VERSION 5.8 ;
BUSBITCHARS "[]" ;
DIVIDERCHAR "/" ;
UNITS
    DATABASE MICRONS 1000 ;
END UNITS

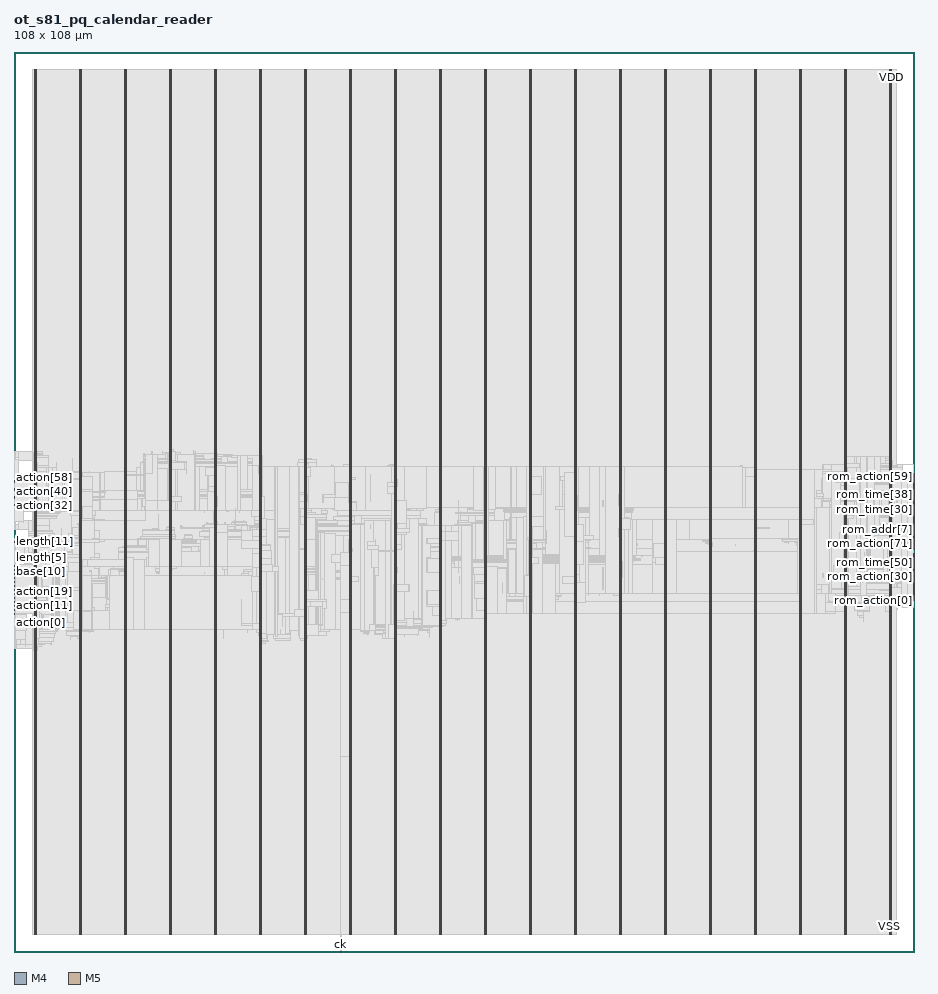
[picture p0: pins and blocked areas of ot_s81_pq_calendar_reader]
MACRO ot_s81_pq_calendar_reader
  FOREIGN ot_s81_pq_calendar_reader 0 0 ;
  CLASS BLOCK ;
  SIZE 108 BY 108 ;
  PIN action[0]
    DIRECTION OUTPUT ;
    USE SIGNAL ;
    PORT
      LAYER M4 ;
        RECT  0 40.464 0.084 40.488 ;
    END
  END action[0]
  PIN action[10]
    DIRECTION OUTPUT ;
    USE SIGNAL ;
    PORT
      LAYER M4 ;
        RECT  0 41.424 0.084 41.448 ;
    END
  END action[10]
  PIN action[11]
    DIRECTION OUTPUT ;
    USE SIGNAL ;
    PORT
      LAYER M4 ;
        RECT  0 41.52 0.084 41.544 ;
    END
  END action[11]
  PIN action[12]
    DIRECTION OUTPUT ;
    USE SIGNAL ;
    PORT
      LAYER M4 ;
        RECT  0 41.616 0.084 41.64 ;
    END
  END action[12]
  PIN action[13]
    DIRECTION OUTPUT ;
    USE SIGNAL ;
    PORT
      LAYER M4 ;
        RECT  0 41.712 0.084 41.736 ;
    END
  END action[13]
  PIN action[14]
    DIRECTION OUTPUT ;
    USE SIGNAL ;
    PORT
      LAYER M4 ;
        RECT  0 41.808 0.084 41.832 ;
    END
  END action[14]
  PIN action[15]
    DIRECTION OUTPUT ;
    USE SIGNAL ;
    PORT
      LAYER M4 ;
        RECT  0 41.904 0.084 41.928 ;
    END
  END action[15]
  PIN action[16]
    DIRECTION OUTPUT ;
    USE SIGNAL ;
    PORT
      LAYER M4 ;
        RECT  0 42 0.084 42.024 ;
    END
  END action[16]
  PIN action[17]
    DIRECTION OUTPUT ;
    USE SIGNAL ;
    PORT
      LAYER M4 ;
        RECT  0 42.096 0.084 42.12 ;
    END
  END action[17]
  PIN action[18]
    DIRECTION OUTPUT ;
    USE SIGNAL ;
    PORT
      LAYER M4 ;
        RECT  0 42.192 0.084 42.216 ;
    END
  END action[18]
  PIN action[19]
    DIRECTION OUTPUT ;
    USE SIGNAL ;
    PORT
      LAYER M4 ;
        RECT  0 42.288 0.084 42.312 ;
    END
  END action[19]
  PIN action[1]
    DIRECTION OUTPUT ;
    USE SIGNAL ;
    PORT
      LAYER M4 ;
        RECT  0 40.56 0.084 40.584 ;
    END
  END action[1]
  PIN action[20]
    DIRECTION OUTPUT ;
    USE SIGNAL ;
    PORT
      LAYER M4 ;
        RECT  0 42.384 0.084 42.408 ;
    END
  END action[20]
  PIN action[21]
    DIRECTION OUTPUT ;
    USE SIGNAL ;
    PORT
      LAYER M4 ;
        RECT  0 42.48 0.084 42.504 ;
    END
  END action[21]
  PIN action[22]
    DIRECTION OUTPUT ;
    USE SIGNAL ;
    PORT
      LAYER M4 ;
        RECT  0 42.576 0.084 42.6 ;
    END
  END action[22]
  PIN action[23]
    DIRECTION OUTPUT ;
    USE SIGNAL ;
    PORT
      LAYER M4 ;
        RECT  0 42.672 0.084 42.696 ;
    END
  END action[23]
  PIN action[24]
    DIRECTION OUTPUT ;
    USE SIGNAL ;
    PORT
      LAYER M4 ;
        RECT  0 42.768 0.084 42.792 ;
    END
  END action[24]
  PIN action[25]
    DIRECTION OUTPUT ;
    USE SIGNAL ;
    PORT
      LAYER M4 ;
        RECT  0 42.864 0.084 42.888 ;
    END
  END action[25]
  PIN action[26]
    DIRECTION OUTPUT ;
    USE SIGNAL ;
    PORT
      LAYER M4 ;
        RECT  0 42.96 0.084 42.984 ;
    END
  END action[26]
  PIN action[27]
    DIRECTION OUTPUT ;
    USE SIGNAL ;
    PORT
      LAYER M4 ;
        RECT  0 43.056 0.084 43.08 ;
    END
  END action[27]
  PIN action[28]
    DIRECTION OUTPUT ;
    USE SIGNAL ;
    PORT
      LAYER M4 ;
        RECT  0 43.152 0.084 43.176 ;
    END
  END action[28]
  PIN action[29]
    DIRECTION OUTPUT ;
    USE SIGNAL ;
    PORT
      LAYER M4 ;
        RECT  0 43.248 0.084 43.272 ;
    END
  END action[29]
  PIN action[2]
    DIRECTION OUTPUT ;
    USE SIGNAL ;
    PORT
      LAYER M4 ;
        RECT  0 40.656 0.084 40.68 ;
    END
  END action[2]
  PIN action[30]
    DIRECTION OUTPUT ;
    USE SIGNAL ;
    PORT
      LAYER M4 ;
        RECT  0 43.344 0.084 43.368 ;
    END
  END action[30]
  PIN action[31]
    DIRECTION OUTPUT ;
    USE SIGNAL ;
    PORT
      LAYER M4 ;
        RECT  0 43.44 0.084 43.464 ;
    END
  END action[31]
  PIN action[32]
    DIRECTION OUTPUT ;
    USE SIGNAL ;
    PORT
      LAYER M4 ;
        RECT  0 53.52 0.084 53.544 ;
    END
  END action[32]
  PIN action[33]
    DIRECTION OUTPUT ;
    USE SIGNAL ;
    PORT
      LAYER M4 ;
        RECT  0 53.616 0.084 53.64 ;
    END
  END action[33]
  PIN action[34]
    DIRECTION OUTPUT ;
    USE SIGNAL ;
    PORT
      LAYER M4 ;
        RECT  0 53.712 0.084 53.736 ;
    END
  END action[34]
  PIN action[35]
    DIRECTION OUTPUT ;
    USE SIGNAL ;
    PORT
      LAYER M4 ;
        RECT  0 53.808 0.084 53.832 ;
    END
  END action[35]
  PIN action[36]
    DIRECTION OUTPUT ;
    USE SIGNAL ;
    PORT
      LAYER M4 ;
        RECT  0 53.904 0.084 53.928 ;
    END
  END action[36]
  PIN action[37]
    DIRECTION OUTPUT ;
    USE SIGNAL ;
    PORT
      LAYER M4 ;
        RECT  0 54 0.084 54.024 ;
    END
  END action[37]
  PIN action[38]
    DIRECTION OUTPUT ;
    USE SIGNAL ;
    PORT
      LAYER M4 ;
        RECT  0 54.096 0.084 54.12 ;
    END
  END action[38]
  PIN action[39]
    DIRECTION OUTPUT ;
    USE SIGNAL ;
    PORT
      LAYER M4 ;
        RECT  0 54.192 0.084 54.216 ;
    END
  END action[39]
  PIN action[3]
    DIRECTION OUTPUT ;
    USE SIGNAL ;
    PORT
      LAYER M4 ;
        RECT  0 40.752 0.084 40.776 ;
    END
  END action[3]
  PIN action[40]
    DIRECTION OUTPUT ;
    USE SIGNAL ;
    PORT
      LAYER M4 ;
        RECT  0 54.288 0.084 54.312 ;
    END
  END action[40]
  PIN action[41]
    DIRECTION OUTPUT ;
    USE SIGNAL ;
    PORT
      LAYER M4 ;
        RECT  0 54.384 0.084 54.408 ;
    END
  END action[41]
  PIN action[42]
    DIRECTION OUTPUT ;
    USE SIGNAL ;
    PORT
      LAYER M4 ;
        RECT  0 54.48 0.084 54.504 ;
    END
  END action[42]
  PIN action[43]
    DIRECTION OUTPUT ;
    USE SIGNAL ;
    PORT
      LAYER M4 ;
        RECT  0 54.576 0.084 54.6 ;
    END
  END action[43]
  PIN action[44]
    DIRECTION OUTPUT ;
    USE SIGNAL ;
    PORT
      LAYER M4 ;
        RECT  0 54.672 0.084 54.696 ;
    END
  END action[44]
  PIN action[45]
    DIRECTION OUTPUT ;
    USE SIGNAL ;
    PORT
      LAYER M4 ;
        RECT  0 54.768 0.084 54.792 ;
    END
  END action[45]
  PIN action[46]
    DIRECTION OUTPUT ;
    USE SIGNAL ;
    PORT
      LAYER M4 ;
        RECT  0 54.864 0.084 54.888 ;
    END
  END action[46]
  PIN action[47]
    DIRECTION OUTPUT ;
    USE SIGNAL ;
    PORT
      LAYER M4 ;
        RECT  0 54.96 0.084 54.984 ;
    END
  END action[47]
  PIN action[48]
    DIRECTION OUTPUT ;
    USE SIGNAL ;
    PORT
      LAYER M4 ;
        RECT  0 55.056 0.084 55.08 ;
    END
  END action[48]
  PIN action[49]
    DIRECTION OUTPUT ;
    USE SIGNAL ;
    PORT
      LAYER M4 ;
        RECT  0 55.152 0.084 55.176 ;
    END
  END action[49]
  PIN action[4]
    DIRECTION OUTPUT ;
    USE SIGNAL ;
    PORT
      LAYER M4 ;
        RECT  0 40.848 0.084 40.872 ;
    END
  END action[4]
  PIN action[50]
    DIRECTION OUTPUT ;
    USE SIGNAL ;
    PORT
      LAYER M4 ;
        RECT  0 55.248 0.084 55.272 ;
    END
  END action[50]
  PIN action[51]
    DIRECTION OUTPUT ;
    USE SIGNAL ;
    PORT
      LAYER M4 ;
        RECT  0 55.344 0.084 55.368 ;
    END
  END action[51]
  PIN action[52]
    DIRECTION OUTPUT ;
    USE SIGNAL ;
    PORT
      LAYER M4 ;
        RECT  0 55.44 0.084 55.464 ;
    END
  END action[52]
  PIN action[53]
    DIRECTION OUTPUT ;
    USE SIGNAL ;
    PORT
      LAYER M4 ;
        RECT  0 55.536 0.084 55.56 ;
    END
  END action[53]
  PIN action[54]
    DIRECTION OUTPUT ;
    USE SIGNAL ;
    PORT
      LAYER M4 ;
        RECT  0 55.632 0.084 55.656 ;
    END
  END action[54]
  PIN action[55]
    DIRECTION OUTPUT ;
    USE SIGNAL ;
    PORT
      LAYER M4 ;
        RECT  0 55.728 0.084 55.752 ;
    END
  END action[55]
  PIN action[56]
    DIRECTION OUTPUT ;
    USE SIGNAL ;
    PORT
      LAYER M4 ;
        RECT  0 55.824 0.084 55.848 ;
    END
  END action[56]
  PIN action[57]
    DIRECTION OUTPUT ;
    USE SIGNAL ;
    PORT
      LAYER M4 ;
        RECT  0 55.92 0.084 55.944 ;
    END
  END action[57]
  PIN action[58]
    DIRECTION OUTPUT ;
    USE SIGNAL ;
    PORT
      LAYER M4 ;
        RECT  0 56.016 0.084 56.04 ;
    END
  END action[58]
  PIN action[59]
    DIRECTION OUTPUT ;
    USE SIGNAL ;
    PORT
      LAYER M4 ;
        RECT  0 56.112 0.084 56.136 ;
    END
  END action[59]
  PIN action[5]
    DIRECTION OUTPUT ;
    USE SIGNAL ;
    PORT
      LAYER M4 ;
        RECT  0 40.944 0.084 40.968 ;
    END
  END action[5]
  PIN action[60]
    DIRECTION OUTPUT ;
    USE SIGNAL ;
    PORT
      LAYER M4 ;
        RECT  0 56.208 0.084 56.232 ;
    END
  END action[60]
  PIN action[61]
    DIRECTION OUTPUT ;
    USE SIGNAL ;
    PORT
      LAYER M4 ;
        RECT  0 56.304 0.084 56.328 ;
    END
  END action[61]
  PIN action[62]
    DIRECTION OUTPUT ;
    USE SIGNAL ;
    PORT
      LAYER M4 ;
        RECT  0 56.4 0.084 56.424 ;
    END
  END action[62]
  PIN action[63]
    DIRECTION OUTPUT ;
    USE SIGNAL ;
    PORT
      LAYER M4 ;
        RECT  0 56.496 0.084 56.52 ;
    END
  END action[63]
  PIN action[64]
    DIRECTION OUTPUT ;
    USE SIGNAL ;
    PORT
      LAYER M4 ;
        RECT  0 43.536 0.084 43.56 ;
    END
  END action[64]
  PIN action[65]
    DIRECTION OUTPUT ;
    USE SIGNAL ;
    PORT
      LAYER M4 ;
        RECT  0 43.632 0.084 43.656 ;
    END
  END action[65]
  PIN action[66]
    DIRECTION OUTPUT ;
    USE SIGNAL ;
    PORT
      LAYER M4 ;
        RECT  0 43.728 0.084 43.752 ;
    END
  END action[66]
  PIN action[67]
    DIRECTION OUTPUT ;
    USE SIGNAL ;
    PORT
      LAYER M4 ;
        RECT  0 43.824 0.084 43.848 ;
    END
  END action[67]
  PIN action[68]
    DIRECTION OUTPUT ;
    USE SIGNAL ;
    PORT
      LAYER M4 ;
        RECT  0 43.92 0.084 43.944 ;
    END
  END action[68]
  PIN action[69]
    DIRECTION OUTPUT ;
    USE SIGNAL ;
    PORT
      LAYER M4 ;
        RECT  0 44.016 0.084 44.04 ;
    END
  END action[69]
  PIN action[6]
    DIRECTION OUTPUT ;
    USE SIGNAL ;
    PORT
      LAYER M4 ;
        RECT  0 41.04 0.084 41.064 ;
    END
  END action[6]
  PIN action[70]
    DIRECTION OUTPUT ;
    USE SIGNAL ;
    PORT
      LAYER M4 ;
        RECT  0 44.112 0.084 44.136 ;
    END
  END action[70]
  PIN action[71]
    DIRECTION OUTPUT ;
    USE SIGNAL ;
    PORT
      LAYER M4 ;
        RECT  0 44.208 0.084 44.232 ;
    END
  END action[71]
  PIN action[72]
    DIRECTION OUTPUT ;
    USE SIGNAL ;
    PORT
      LAYER M4 ;
        RECT  0 44.304 0.084 44.328 ;
    END
  END action[72]
  PIN action[73]
    DIRECTION OUTPUT ;
    USE SIGNAL ;
    PORT
      LAYER M4 ;
        RECT  0 44.4 0.084 44.424 ;
    END
  END action[73]
  PIN action[74]
    DIRECTION OUTPUT ;
    USE SIGNAL ;
    PORT
      LAYER M4 ;
        RECT  0 44.496 0.084 44.52 ;
    END
  END action[74]
  PIN action[7]
    DIRECTION OUTPUT ;
    USE SIGNAL ;
    PORT
      LAYER M4 ;
        RECT  0 41.136 0.084 41.16 ;
    END
  END action[7]
  PIN action[8]
    DIRECTION OUTPUT ;
    USE SIGNAL ;
    PORT
      LAYER M4 ;
        RECT  0 41.232 0.084 41.256 ;
    END
  END action[8]
  PIN action[9]
    DIRECTION OUTPUT ;
    USE SIGNAL ;
    PORT
      LAYER M4 ;
        RECT  0 41.328 0.084 41.352 ;
    END
  END action[9]
  PIN active
    DIRECTION OUTPUT ;
    USE SIGNAL ;
    PORT
      LAYER M4 ;
        RECT  0 44.592 0.084 44.616 ;
    END
  END active
  PIN base[0]
    DIRECTION INPUT ;
    USE SIGNAL ;
    PORT
      LAYER M4 ;
        RECT  0 44.688 0.084 44.712 ;
    END
  END base[0]
  PIN base[10]
    DIRECTION INPUT ;
    USE SIGNAL ;
    PORT
      LAYER M4 ;
        RECT  0 45.648 0.084 45.672 ;
    END
  END base[10]
  PIN base[11]
    DIRECTION INPUT ;
    USE SIGNAL ;
    PORT
      LAYER M4 ;
        RECT  0 45.744 0.084 45.768 ;
    END
  END base[11]
  PIN base[1]
    DIRECTION INPUT ;
    USE SIGNAL ;
    PORT
      LAYER M4 ;
        RECT  0 44.784 0.084 44.808 ;
    END
  END base[1]
  PIN base[2]
    DIRECTION INPUT ;
    USE SIGNAL ;
    PORT
      LAYER M4 ;
        RECT  0 44.88 0.084 44.904 ;
    END
  END base[2]
  PIN base[3]
    DIRECTION INPUT ;
    USE SIGNAL ;
    PORT
      LAYER M4 ;
        RECT  0 44.976 0.084 45 ;
    END
  END base[3]
  PIN base[4]
    DIRECTION INPUT ;
    USE SIGNAL ;
    PORT
      LAYER M4 ;
        RECT  0 45.072 0.084 45.096 ;
    END
  END base[4]
  PIN base[5]
    DIRECTION INPUT ;
    USE SIGNAL ;
    PORT
      LAYER M4 ;
        RECT  0 45.168 0.084 45.192 ;
    END
  END base[5]
  PIN base[6]
    DIRECTION INPUT ;
    USE SIGNAL ;
    PORT
      LAYER M4 ;
        RECT  0 45.264 0.084 45.288 ;
    END
  END base[6]
  PIN base[7]
    DIRECTION INPUT ;
    USE SIGNAL ;
    PORT
      LAYER M4 ;
        RECT  0 45.36 0.084 45.384 ;
    END
  END base[7]
  PIN base[8]
    DIRECTION INPUT ;
    USE SIGNAL ;
    PORT
      LAYER M4 ;
        RECT  0 45.456 0.084 45.48 ;
    END
  END base[8]
  PIN base[9]
    DIRECTION INPUT ;
    USE SIGNAL ;
    PORT
      LAYER M4 ;
        RECT  0 45.552 0.084 45.576 ;
    END
  END base[9]
  PIN ck
    DIRECTION INPUT ;
    USE SIGNAL ;
    PORT
      LAYER M5 ;
        RECT  39.12 0 39.144 0.084 ;
    END
  END ck
  PIN fault
    DIRECTION OUTPUT ;
    USE SIGNAL ;
    PORT
      LAYER M4 ;
        RECT  0 45.84 0.084 45.864 ;
    END
  END fault
  PIN length[0]
    DIRECTION INPUT ;
    USE SIGNAL ;
    PORT
      LAYER M4 ;
        RECT  0 45.936 0.084 45.96 ;
    END
  END length[0]
  PIN length[10]
    DIRECTION INPUT ;
    USE SIGNAL ;
    PORT
      LAYER M4 ;
        RECT  0 49.104 0.084 49.128 ;
    END
  END length[10]
  PIN length[11]
    DIRECTION INPUT ;
    USE SIGNAL ;
    PORT
      LAYER M4 ;
        RECT  0 49.2 0.084 49.224 ;
    END
  END length[11]
  PIN length[12]
    DIRECTION INPUT ;
    USE SIGNAL ;
    PORT
      LAYER M4 ;
        RECT  0 49.296 0.084 49.32 ;
    END
  END length[12]
  PIN length[1]
    DIRECTION INPUT ;
    USE SIGNAL ;
    PORT
      LAYER M4 ;
        RECT  0 46.032 0.084 46.056 ;
    END
  END length[1]
  PIN length[2]
    DIRECTION INPUT ;
    USE SIGNAL ;
    PORT
      LAYER M4 ;
        RECT  0 46.128 0.084 46.152 ;
    END
  END length[2]
  PIN length[3]
    DIRECTION INPUT ;
    USE SIGNAL ;
    PORT
      LAYER M4 ;
        RECT  0 46.224 0.084 46.248 ;
    END
  END length[3]
  PIN length[4]
    DIRECTION INPUT ;
    USE SIGNAL ;
    PORT
      LAYER M4 ;
        RECT  0 46.32 0.084 46.344 ;
    END
  END length[4]
  PIN length[5]
    DIRECTION INPUT ;
    USE SIGNAL ;
    PORT
      LAYER M4 ;
        RECT  0 46.416 0.084 46.44 ;
    END
  END length[5]
  PIN length[6]
    DIRECTION INPUT ;
    USE SIGNAL ;
    PORT
      LAYER M4 ;
        RECT  0 46.512 0.084 46.536 ;
    END
  END length[6]
  PIN length[7]
    DIRECTION INPUT ;
    USE SIGNAL ;
    PORT
      LAYER M4 ;
        RECT  0 48.816 0.084 48.84 ;
    END
  END length[7]
  PIN length[8]
    DIRECTION INPUT ;
    USE SIGNAL ;
    PORT
      LAYER M4 ;
        RECT  0 48.912 0.084 48.936 ;
    END
  END length[8]
  PIN length[9]
    DIRECTION INPUT ;
    USE SIGNAL ;
    PORT
      LAYER M4 ;
        RECT  0 49.008 0.084 49.032 ;
    END
  END length[9]
  PIN prime
    DIRECTION INPUT ;
    USE SIGNAL ;
    PORT
      LAYER M4 ;
        RECT  0 49.392 0.084 49.416 ;
    END
  END prime
  PIN primed
    DIRECTION OUTPUT ;
    USE SIGNAL ;
    PORT
      LAYER M4 ;
        RECT  0 49.488 0.084 49.512 ;
    END
  END primed
  PIN rom_action[0]
    DIRECTION INPUT ;
    USE SIGNAL ;
    PORT
      LAYER M4 ;
        RECT  107.916 42.192 108 42.216 ;
    END
  END rom_action[0]
  PIN rom_action[10]
    DIRECTION INPUT ;
    USE SIGNAL ;
    PORT
      LAYER M4 ;
        RECT  107.916 43.152 108 43.176 ;
    END
  END rom_action[10]
  PIN rom_action[11]
    DIRECTION INPUT ;
    USE SIGNAL ;
    PORT
      LAYER M4 ;
        RECT  107.916 43.248 108 43.272 ;
    END
  END rom_action[11]
  PIN rom_action[12]
    DIRECTION INPUT ;
    USE SIGNAL ;
    PORT
      LAYER M4 ;
        RECT  107.916 43.344 108 43.368 ;
    END
  END rom_action[12]
  PIN rom_action[13]
    DIRECTION INPUT ;
    USE SIGNAL ;
    PORT
      LAYER M4 ;
        RECT  107.916 43.44 108 43.464 ;
    END
  END rom_action[13]
  PIN rom_action[14]
    DIRECTION INPUT ;
    USE SIGNAL ;
    PORT
      LAYER M4 ;
        RECT  107.916 43.536 108 43.56 ;
    END
  END rom_action[14]
  PIN rom_action[15]
    DIRECTION INPUT ;
    USE SIGNAL ;
    PORT
      LAYER M4 ;
        RECT  107.916 43.632 108 43.656 ;
    END
  END rom_action[15]
  PIN rom_action[16]
    DIRECTION INPUT ;
    USE SIGNAL ;
    PORT
      LAYER M4 ;
        RECT  107.916 43.728 108 43.752 ;
    END
  END rom_action[16]
  PIN rom_action[17]
    DIRECTION INPUT ;
    USE SIGNAL ;
    PORT
      LAYER M4 ;
        RECT  107.916 43.824 108 43.848 ;
    END
  END rom_action[17]
  PIN rom_action[18]
    DIRECTION INPUT ;
    USE SIGNAL ;
    PORT
      LAYER M4 ;
        RECT  107.916 43.92 108 43.944 ;
    END
  END rom_action[18]
  PIN rom_action[19]
    DIRECTION INPUT ;
    USE SIGNAL ;
    PORT
      LAYER M4 ;
        RECT  107.916 44.016 108 44.04 ;
    END
  END rom_action[19]
  PIN rom_action[1]
    DIRECTION INPUT ;
    USE SIGNAL ;
    PORT
      LAYER M4 ;
        RECT  107.916 42.288 108 42.312 ;
    END
  END rom_action[1]
  PIN rom_action[20]
    DIRECTION INPUT ;
    USE SIGNAL ;
    PORT
      LAYER M4 ;
        RECT  107.916 44.112 108 44.136 ;
    END
  END rom_action[20]
  PIN rom_action[21]
    DIRECTION INPUT ;
    USE SIGNAL ;
    PORT
      LAYER M4 ;
        RECT  107.916 44.208 108 44.232 ;
    END
  END rom_action[21]
  PIN rom_action[22]
    DIRECTION INPUT ;
    USE SIGNAL ;
    PORT
      LAYER M4 ;
        RECT  107.916 44.304 108 44.328 ;
    END
  END rom_action[22]
  PIN rom_action[23]
    DIRECTION INPUT ;
    USE SIGNAL ;
    PORT
      LAYER M4 ;
        RECT  107.916 44.4 108 44.424 ;
    END
  END rom_action[23]
  PIN rom_action[24]
    DIRECTION INPUT ;
    USE SIGNAL ;
    PORT
      LAYER M4 ;
        RECT  107.916 44.496 108 44.52 ;
    END
  END rom_action[24]
  PIN rom_action[25]
    DIRECTION INPUT ;
    USE SIGNAL ;
    PORT
      LAYER M4 ;
        RECT  107.916 44.592 108 44.616 ;
    END
  END rom_action[25]
  PIN rom_action[26]
    DIRECTION INPUT ;
    USE SIGNAL ;
    PORT
      LAYER M4 ;
        RECT  107.916 44.688 108 44.712 ;
    END
  END rom_action[26]
  PIN rom_action[27]
    DIRECTION INPUT ;
    USE SIGNAL ;
    PORT
      LAYER M4 ;
        RECT  107.916 44.784 108 44.808 ;
    END
  END rom_action[27]
  PIN rom_action[28]
    DIRECTION INPUT ;
    USE SIGNAL ;
    PORT
      LAYER M4 ;
        RECT  107.916 44.88 108 44.904 ;
    END
  END rom_action[28]
  PIN rom_action[29]
    DIRECTION INPUT ;
    USE SIGNAL ;
    PORT
      LAYER M4 ;
        RECT  107.916 44.976 108 45 ;
    END
  END rom_action[29]
  PIN rom_action[2]
    DIRECTION INPUT ;
    USE SIGNAL ;
    PORT
      LAYER M4 ;
        RECT  107.916 42.384 108 42.408 ;
    END
  END rom_action[2]
  PIN rom_action[30]
    DIRECTION INPUT ;
    USE SIGNAL ;
    PORT
      LAYER M4 ;
        RECT  107.916 45.072 108 45.096 ;
    END
  END rom_action[30]
  PIN rom_action[31]
    DIRECTION INPUT ;
    USE SIGNAL ;
    PORT
      LAYER M4 ;
        RECT  107.916 45.168 108 45.192 ;
    END
  END rom_action[31]
  PIN rom_action[32]
    DIRECTION INPUT ;
    USE SIGNAL ;
    PORT
      LAYER M4 ;
        RECT  107.916 54.48 108 54.504 ;
    END
  END rom_action[32]
  PIN rom_action[33]
    DIRECTION INPUT ;
    USE SIGNAL ;
    PORT
      LAYER M4 ;
        RECT  107.916 54.576 108 54.6 ;
    END
  END rom_action[33]
  PIN rom_action[34]
    DIRECTION INPUT ;
    USE SIGNAL ;
    PORT
      LAYER M4 ;
        RECT  107.916 54.672 108 54.696 ;
    END
  END rom_action[34]
  PIN rom_action[35]
    DIRECTION INPUT ;
    USE SIGNAL ;
    PORT
      LAYER M4 ;
        RECT  107.916 54.768 108 54.792 ;
    END
  END rom_action[35]
  PIN rom_action[36]
    DIRECTION INPUT ;
    USE SIGNAL ;
    PORT
      LAYER M4 ;
        RECT  107.916 54.864 108 54.888 ;
    END
  END rom_action[36]
  PIN rom_action[37]
    DIRECTION INPUT ;
    USE SIGNAL ;
    PORT
      LAYER M4 ;
        RECT  107.916 54.96 108 54.984 ;
    END
  END rom_action[37]
  PIN rom_action[38]
    DIRECTION INPUT ;
    USE SIGNAL ;
    PORT
      LAYER M4 ;
        RECT  107.916 55.056 108 55.08 ;
    END
  END rom_action[38]
  PIN rom_action[39]
    DIRECTION INPUT ;
    USE SIGNAL ;
    PORT
      LAYER M4 ;
        RECT  107.916 55.152 108 55.176 ;
    END
  END rom_action[39]
  PIN rom_action[3]
    DIRECTION INPUT ;
    USE SIGNAL ;
    PORT
      LAYER M4 ;
        RECT  107.916 42.48 108 42.504 ;
    END
  END rom_action[3]
  PIN rom_action[40]
    DIRECTION INPUT ;
    USE SIGNAL ;
    PORT
      LAYER M4 ;
        RECT  107.916 55.248 108 55.272 ;
    END
  END rom_action[40]
  PIN rom_action[41]
    DIRECTION INPUT ;
    USE SIGNAL ;
    PORT
      LAYER M4 ;
        RECT  107.916 55.344 108 55.368 ;
    END
  END rom_action[41]
  PIN rom_action[42]
    DIRECTION INPUT ;
    USE SIGNAL ;
    PORT
      LAYER M4 ;
        RECT  107.916 55.44 108 55.464 ;
    END
  END rom_action[42]
  PIN rom_action[43]
    DIRECTION INPUT ;
    USE SIGNAL ;
    PORT
      LAYER M4 ;
        RECT  107.916 55.536 108 55.56 ;
    END
  END rom_action[43]
  PIN rom_action[44]
    DIRECTION INPUT ;
    USE SIGNAL ;
    PORT
      LAYER M4 ;
        RECT  107.916 55.632 108 55.656 ;
    END
  END rom_action[44]
  PIN rom_action[45]
    DIRECTION INPUT ;
    USE SIGNAL ;
    PORT
      LAYER M4 ;
        RECT  107.916 55.728 108 55.752 ;
    END
  END rom_action[45]
  PIN rom_action[46]
    DIRECTION INPUT ;
    USE SIGNAL ;
    PORT
      LAYER M4 ;
        RECT  107.916 55.824 108 55.848 ;
    END
  END rom_action[46]
  PIN rom_action[47]
    DIRECTION INPUT ;
    USE SIGNAL ;
    PORT
      LAYER M4 ;
        RECT  107.916 55.92 108 55.944 ;
    END
  END rom_action[47]
  PIN rom_action[48]
    DIRECTION INPUT ;
    USE SIGNAL ;
    PORT
      LAYER M4 ;
        RECT  107.916 56.016 108 56.04 ;
    END
  END rom_action[48]
  PIN rom_action[49]
    DIRECTION INPUT ;
    USE SIGNAL ;
    PORT
      LAYER M4 ;
        RECT  107.916 56.112 108 56.136 ;
    END
  END rom_action[49]
  PIN rom_action[4]
    DIRECTION INPUT ;
    USE SIGNAL ;
    PORT
      LAYER M4 ;
        RECT  107.916 42.576 108 42.6 ;
    END
  END rom_action[4]
  PIN rom_action[50]
    DIRECTION INPUT ;
    USE SIGNAL ;
    PORT
      LAYER M4 ;
        RECT  107.916 56.208 108 56.232 ;
    END
  END rom_action[50]
  PIN rom_action[51]
    DIRECTION INPUT ;
    USE SIGNAL ;
    PORT
      LAYER M4 ;
        RECT  107.916 56.304 108 56.328 ;
    END
  END rom_action[51]
  PIN rom_action[52]
    DIRECTION INPUT ;
    USE SIGNAL ;
    PORT
      LAYER M4 ;
        RECT  107.916 56.4 108 56.424 ;
    END
  END rom_action[52]
  PIN rom_action[53]
    DIRECTION INPUT ;
    USE SIGNAL ;
    PORT
      LAYER M4 ;
        RECT  107.916 56.496 108 56.52 ;
    END
  END rom_action[53]
  PIN rom_action[54]
    DIRECTION INPUT ;
    USE SIGNAL ;
    PORT
      LAYER M4 ;
        RECT  107.916 56.592 108 56.616 ;
    END
  END rom_action[54]
  PIN rom_action[55]
    DIRECTION INPUT ;
    USE SIGNAL ;
    PORT
      LAYER M4 ;
        RECT  107.916 56.688 108 56.712 ;
    END
  END rom_action[55]
  PIN rom_action[56]
    DIRECTION INPUT ;
    USE SIGNAL ;
    PORT
      LAYER M4 ;
        RECT  107.916 56.784 108 56.808 ;
    END
  END rom_action[56]
  PIN rom_action[57]
    DIRECTION INPUT ;
    USE SIGNAL ;
    PORT
      LAYER M4 ;
        RECT  107.916 56.88 108 56.904 ;
    END
  END rom_action[57]
  PIN rom_action[58]
    DIRECTION INPUT ;
    USE SIGNAL ;
    PORT
      LAYER M4 ;
        RECT  107.916 56.976 108 57 ;
    END
  END rom_action[58]
  PIN rom_action[59]
    DIRECTION INPUT ;
    USE SIGNAL ;
    PORT
      LAYER M4 ;
        RECT  107.916 57.072 108 57.096 ;
    END
  END rom_action[59]
  PIN rom_action[5]
    DIRECTION INPUT ;
    USE SIGNAL ;
    PORT
      LAYER M4 ;
        RECT  107.916 42.672 108 42.696 ;
    END
  END rom_action[5]
  PIN rom_action[60]
    DIRECTION INPUT ;
    USE SIGNAL ;
    PORT
      LAYER M4 ;
        RECT  107.916 57.168 108 57.192 ;
    END
  END rom_action[60]
  PIN rom_action[61]
    DIRECTION INPUT ;
    USE SIGNAL ;
    PORT
      LAYER M4 ;
        RECT  107.916 57.264 108 57.288 ;
    END
  END rom_action[61]
  PIN rom_action[62]
    DIRECTION INPUT ;
    USE SIGNAL ;
    PORT
      LAYER M4 ;
        RECT  107.916 57.36 108 57.384 ;
    END
  END rom_action[62]
  PIN rom_action[63]
    DIRECTION INPUT ;
    USE SIGNAL ;
    PORT
      LAYER M4 ;
        RECT  107.916 57.456 108 57.48 ;
    END
  END rom_action[63]
  PIN rom_action[64]
    DIRECTION INPUT ;
    USE SIGNAL ;
    PORT
      LAYER M4 ;
        RECT  107.916 48.336 108 48.36 ;
    END
  END rom_action[64]
  PIN rom_action[65]
    DIRECTION INPUT ;
    USE SIGNAL ;
    PORT
      LAYER M4 ;
        RECT  107.916 48.432 108 48.456 ;
    END
  END rom_action[65]
  PIN rom_action[66]
    DIRECTION INPUT ;
    USE SIGNAL ;
    PORT
      LAYER M4 ;
        RECT  107.916 48.528 108 48.552 ;
    END
  END rom_action[66]
  PIN rom_action[67]
    DIRECTION INPUT ;
    USE SIGNAL ;
    PORT
      LAYER M4 ;
        RECT  107.916 48.624 108 48.648 ;
    END
  END rom_action[67]
  PIN rom_action[68]
    DIRECTION INPUT ;
    USE SIGNAL ;
    PORT
      LAYER M4 ;
        RECT  107.916 48.72 108 48.744 ;
    END
  END rom_action[68]
  PIN rom_action[69]
    DIRECTION INPUT ;
    USE SIGNAL ;
    PORT
      LAYER M4 ;
        RECT  107.916 48.816 108 48.84 ;
    END
  END rom_action[69]
  PIN rom_action[6]
    DIRECTION INPUT ;
    USE SIGNAL ;
    PORT
      LAYER M4 ;
        RECT  107.916 42.768 108 42.792 ;
    END
  END rom_action[6]
  PIN rom_action[70]
    DIRECTION INPUT ;
    USE SIGNAL ;
    PORT
      LAYER M4 ;
        RECT  107.916 48.912 108 48.936 ;
    END
  END rom_action[70]
  PIN rom_action[71]
    DIRECTION INPUT ;
    USE SIGNAL ;
    PORT
      LAYER M4 ;
        RECT  107.916 49.008 108 49.032 ;
    END
  END rom_action[71]
  PIN rom_action[7]
    DIRECTION INPUT ;
    USE SIGNAL ;
    PORT
      LAYER M4 ;
        RECT  107.916 42.864 108 42.888 ;
    END
  END rom_action[7]
  PIN rom_action[8]
    DIRECTION INPUT ;
    USE SIGNAL ;
    PORT
      LAYER M4 ;
        RECT  107.916 42.96 108 42.984 ;
    END
  END rom_action[8]
  PIN rom_action[9]
    DIRECTION INPUT ;
    USE SIGNAL ;
    PORT
      LAYER M4 ;
        RECT  107.916 43.056 108 43.08 ;
    END
  END rom_action[9]
  PIN rom_addr[0]
    DIRECTION OUTPUT ;
    USE SIGNAL ;
    PORT
      LAYER M4 ;
        RECT  107.916 49.104 108 49.128 ;
    END
  END rom_addr[0]
  PIN rom_addr[10]
    DIRECTION OUTPUT ;
    USE SIGNAL ;
    PORT
      LAYER M4 ;
        RECT  107.916 50.064 108 50.088 ;
    END
  END rom_addr[10]
  PIN rom_addr[11]
    DIRECTION OUTPUT ;
    USE SIGNAL ;
    PORT
      LAYER M4 ;
        RECT  107.916 50.16 108 50.184 ;
    END
  END rom_addr[11]
  PIN rom_addr[1]
    DIRECTION OUTPUT ;
    USE SIGNAL ;
    PORT
      LAYER M4 ;
        RECT  107.916 49.2 108 49.224 ;
    END
  END rom_addr[1]
  PIN rom_addr[2]
    DIRECTION OUTPUT ;
    USE SIGNAL ;
    PORT
      LAYER M4 ;
        RECT  107.916 49.296 108 49.32 ;
    END
  END rom_addr[2]
  PIN rom_addr[3]
    DIRECTION OUTPUT ;
    USE SIGNAL ;
    PORT
      LAYER M4 ;
        RECT  107.916 49.392 108 49.416 ;
    END
  END rom_addr[3]
  PIN rom_addr[4]
    DIRECTION OUTPUT ;
    USE SIGNAL ;
    PORT
      LAYER M4 ;
        RECT  107.916 49.488 108 49.512 ;
    END
  END rom_addr[4]
  PIN rom_addr[5]
    DIRECTION OUTPUT ;
    USE SIGNAL ;
    PORT
      LAYER M4 ;
        RECT  107.916 49.584 108 49.608 ;
    END
  END rom_addr[5]
  PIN rom_addr[6]
    DIRECTION OUTPUT ;
    USE SIGNAL ;
    PORT
      LAYER M4 ;
        RECT  107.916 49.68 108 49.704 ;
    END
  END rom_addr[6]
  PIN rom_addr[7]
    DIRECTION OUTPUT ;
    USE SIGNAL ;
    PORT
      LAYER M4 ;
        RECT  107.916 49.776 108 49.8 ;
    END
  END rom_addr[7]
  PIN rom_addr[8]
    DIRECTION OUTPUT ;
    USE SIGNAL ;
    PORT
      LAYER M4 ;
        RECT  107.916 49.872 108 49.896 ;
    END
  END rom_addr[8]
  PIN rom_addr[9]
    DIRECTION OUTPUT ;
    USE SIGNAL ;
    PORT
      LAYER M4 ;
        RECT  107.916 49.968 108 49.992 ;
    END
  END rom_addr[9]
  PIN rom_time[0]
    DIRECTION INPUT ;
    USE SIGNAL ;
    PORT
      LAYER M4 ;
        RECT  107.916 50.256 108 50.28 ;
    END
  END rom_time[0]
  PIN rom_time[10]
    DIRECTION INPUT ;
    USE SIGNAL ;
    PORT
      LAYER M4 ;
        RECT  107.916 51.216 108 51.24 ;
    END
  END rom_time[10]
  PIN rom_time[11]
    DIRECTION INPUT ;
    USE SIGNAL ;
    PORT
      LAYER M4 ;
        RECT  107.916 51.312 108 51.336 ;
    END
  END rom_time[11]
  PIN rom_time[12]
    DIRECTION INPUT ;
    USE SIGNAL ;
    PORT
      LAYER M4 ;
        RECT  107.916 51.408 108 51.432 ;
    END
  END rom_time[12]
  PIN rom_time[13]
    DIRECTION INPUT ;
    USE SIGNAL ;
    PORT
      LAYER M4 ;
        RECT  107.916 51.504 108 51.528 ;
    END
  END rom_time[13]
  PIN rom_time[14]
    DIRECTION INPUT ;
    USE SIGNAL ;
    PORT
      LAYER M4 ;
        RECT  107.916 51.6 108 51.624 ;
    END
  END rom_time[14]
  PIN rom_time[15]
    DIRECTION INPUT ;
    USE SIGNAL ;
    PORT
      LAYER M4 ;
        RECT  107.916 51.696 108 51.72 ;
    END
  END rom_time[15]
  PIN rom_time[16]
    DIRECTION INPUT ;
    USE SIGNAL ;
    PORT
      LAYER M4 ;
        RECT  107.916 51.792 108 51.816 ;
    END
  END rom_time[16]
  PIN rom_time[17]
    DIRECTION INPUT ;
    USE SIGNAL ;
    PORT
      LAYER M4 ;
        RECT  107.916 51.888 108 51.912 ;
    END
  END rom_time[17]
  PIN rom_time[18]
    DIRECTION INPUT ;
    USE SIGNAL ;
    PORT
      LAYER M4 ;
        RECT  107.916 51.984 108 52.008 ;
    END
  END rom_time[18]
  PIN rom_time[19]
    DIRECTION INPUT ;
    USE SIGNAL ;
    PORT
      LAYER M4 ;
        RECT  107.916 52.08 108 52.104 ;
    END
  END rom_time[19]
  PIN rom_time[1]
    DIRECTION INPUT ;
    USE SIGNAL ;
    PORT
      LAYER M4 ;
        RECT  107.916 50.352 108 50.376 ;
    END
  END rom_time[1]
  PIN rom_time[20]
    DIRECTION INPUT ;
    USE SIGNAL ;
    PORT
      LAYER M4 ;
        RECT  107.916 52.176 108 52.2 ;
    END
  END rom_time[20]
  PIN rom_time[21]
    DIRECTION INPUT ;
    USE SIGNAL ;
    PORT
      LAYER M4 ;
        RECT  107.916 52.272 108 52.296 ;
    END
  END rom_time[21]
  PIN rom_time[22]
    DIRECTION INPUT ;
    USE SIGNAL ;
    PORT
      LAYER M4 ;
        RECT  107.916 52.368 108 52.392 ;
    END
  END rom_time[22]
  PIN rom_time[23]
    DIRECTION INPUT ;
    USE SIGNAL ;
    PORT
      LAYER M4 ;
        RECT  107.916 52.464 108 52.488 ;
    END
  END rom_time[23]
  PIN rom_time[24]
    DIRECTION INPUT ;
    USE SIGNAL ;
    PORT
      LAYER M4 ;
        RECT  107.916 52.56 108 52.584 ;
    END
  END rom_time[24]
  PIN rom_time[25]
    DIRECTION INPUT ;
    USE SIGNAL ;
    PORT
      LAYER M4 ;
        RECT  107.916 52.656 108 52.68 ;
    END
  END rom_time[25]
  PIN rom_time[26]
    DIRECTION INPUT ;
    USE SIGNAL ;
    PORT
      LAYER M4 ;
        RECT  107.916 52.752 108 52.776 ;
    END
  END rom_time[26]
  PIN rom_time[27]
    DIRECTION INPUT ;
    USE SIGNAL ;
    PORT
      LAYER M4 ;
        RECT  107.916 52.848 108 52.872 ;
    END
  END rom_time[27]
  PIN rom_time[28]
    DIRECTION INPUT ;
    USE SIGNAL ;
    PORT
      LAYER M4 ;
        RECT  107.916 52.944 108 52.968 ;
    END
  END rom_time[28]
  PIN rom_time[29]
    DIRECTION INPUT ;
    USE SIGNAL ;
    PORT
      LAYER M4 ;
        RECT  107.916 53.04 108 53.064 ;
    END
  END rom_time[29]
  PIN rom_time[2]
    DIRECTION INPUT ;
    USE SIGNAL ;
    PORT
      LAYER M4 ;
        RECT  107.916 50.448 108 50.472 ;
    END
  END rom_time[2]
  PIN rom_time[30]
    DIRECTION INPUT ;
    USE SIGNAL ;
    PORT
      LAYER M4 ;
        RECT  107.916 53.136 108 53.16 ;
    END
  END rom_time[30]
  PIN rom_time[31]
    DIRECTION INPUT ;
    USE SIGNAL ;
    PORT
      LAYER M4 ;
        RECT  107.916 53.232 108 53.256 ;
    END
  END rom_time[31]
  PIN rom_time[32]
    DIRECTION INPUT ;
    USE SIGNAL ;
    PORT
      LAYER M4 ;
        RECT  107.916 53.328 108 53.352 ;
    END
  END rom_time[32]
  PIN rom_time[33]
    DIRECTION INPUT ;
    USE SIGNAL ;
    PORT
      LAYER M4 ;
        RECT  107.916 53.424 108 53.448 ;
    END
  END rom_time[33]
  PIN rom_time[34]
    DIRECTION INPUT ;
    USE SIGNAL ;
    PORT
      LAYER M4 ;
        RECT  107.916 53.52 108 53.544 ;
    END
  END rom_time[34]
  PIN rom_time[35]
    DIRECTION INPUT ;
    USE SIGNAL ;
    PORT
      LAYER M4 ;
        RECT  107.916 53.616 108 53.64 ;
    END
  END rom_time[35]
  PIN rom_time[36]
    DIRECTION INPUT ;
    USE SIGNAL ;
    PORT
      LAYER M4 ;
        RECT  107.916 53.712 108 53.736 ;
    END
  END rom_time[36]
  PIN rom_time[37]
    DIRECTION INPUT ;
    USE SIGNAL ;
    PORT
      LAYER M4 ;
        RECT  107.916 53.808 108 53.832 ;
    END
  END rom_time[37]
  PIN rom_time[38]
    DIRECTION INPUT ;
    USE SIGNAL ;
    PORT
      LAYER M4 ;
        RECT  107.916 53.904 108 53.928 ;
    END
  END rom_time[38]
  PIN rom_time[39]
    DIRECTION INPUT ;
    USE SIGNAL ;
    PORT
      LAYER M4 ;
        RECT  107.916 54 108 54.024 ;
    END
  END rom_time[39]
  PIN rom_time[3]
    DIRECTION INPUT ;
    USE SIGNAL ;
    PORT
      LAYER M4 ;
        RECT  107.916 50.544 108 50.568 ;
    END
  END rom_time[3]
  PIN rom_time[40]
    DIRECTION INPUT ;
    USE SIGNAL ;
    PORT
      LAYER M4 ;
        RECT  107.916 54.096 108 54.12 ;
    END
  END rom_time[40]
  PIN rom_time[41]
    DIRECTION INPUT ;
    USE SIGNAL ;
    PORT
      LAYER M4 ;
        RECT  107.916 54.192 108 54.216 ;
    END
  END rom_time[41]
  PIN rom_time[42]
    DIRECTION INPUT ;
    USE SIGNAL ;
    PORT
      LAYER M4 ;
        RECT  107.916 54.288 108 54.312 ;
    END
  END rom_time[42]
  PIN rom_time[43]
    DIRECTION INPUT ;
    USE SIGNAL ;
    PORT
      LAYER M4 ;
        RECT  107.916 54.384 108 54.408 ;
    END
  END rom_time[43]
  PIN rom_time[44]
    DIRECTION INPUT ;
    USE SIGNAL ;
    PORT
      LAYER M4 ;
        RECT  107.916 45.264 108 45.288 ;
    END
  END rom_time[44]
  PIN rom_time[45]
    DIRECTION INPUT ;
    USE SIGNAL ;
    PORT
      LAYER M4 ;
        RECT  107.916 45.36 108 45.384 ;
    END
  END rom_time[45]
  PIN rom_time[46]
    DIRECTION INPUT ;
    USE SIGNAL ;
    PORT
      LAYER M4 ;
        RECT  107.916 45.456 108 45.48 ;
    END
  END rom_time[46]
  PIN rom_time[47]
    DIRECTION INPUT ;
    USE SIGNAL ;
    PORT
      LAYER M4 ;
        RECT  107.916 45.552 108 45.576 ;
    END
  END rom_time[47]
  PIN rom_time[48]
    DIRECTION INPUT ;
    USE SIGNAL ;
    PORT
      LAYER M4 ;
        RECT  107.916 45.648 108 45.672 ;
    END
  END rom_time[48]
  PIN rom_time[49]
    DIRECTION INPUT ;
    USE SIGNAL ;
    PORT
      LAYER M4 ;
        RECT  107.916 45.744 108 45.768 ;
    END
  END rom_time[49]
  PIN rom_time[4]
    DIRECTION INPUT ;
    USE SIGNAL ;
    PORT
      LAYER M4 ;
        RECT  107.916 50.64 108 50.664 ;
    END
  END rom_time[4]
  PIN rom_time[50]
    DIRECTION INPUT ;
    USE SIGNAL ;
    PORT
      LAYER M4 ;
        RECT  107.916 45.84 108 45.864 ;
    END
  END rom_time[50]
  PIN rom_time[51]
    DIRECTION INPUT ;
    USE SIGNAL ;
    PORT
      LAYER M4 ;
        RECT  107.916 45.936 108 45.96 ;
    END
  END rom_time[51]
  PIN rom_time[52]
    DIRECTION INPUT ;
    USE SIGNAL ;
    PORT
      LAYER M4 ;
        RECT  107.916 46.032 108 46.056 ;
    END
  END rom_time[52]
  PIN rom_time[53]
    DIRECTION INPUT ;
    USE SIGNAL ;
    PORT
      LAYER M4 ;
        RECT  107.916 46.128 108 46.152 ;
    END
  END rom_time[53]
  PIN rom_time[54]
    DIRECTION INPUT ;
    USE SIGNAL ;
    PORT
      LAYER M4 ;
        RECT  107.916 46.224 108 46.248 ;
    END
  END rom_time[54]
  PIN rom_time[55]
    DIRECTION INPUT ;
    USE SIGNAL ;
    PORT
      LAYER M4 ;
        RECT  107.916 46.32 108 46.344 ;
    END
  END rom_time[55]
  PIN rom_time[56]
    DIRECTION INPUT ;
    USE SIGNAL ;
    PORT
      LAYER M4 ;
        RECT  107.916 46.416 108 46.44 ;
    END
  END rom_time[56]
  PIN rom_time[57]
    DIRECTION INPUT ;
    USE SIGNAL ;
    PORT
      LAYER M4 ;
        RECT  107.916 46.512 108 46.536 ;
    END
  END rom_time[57]
  PIN rom_time[58]
    DIRECTION INPUT ;
    USE SIGNAL ;
    PORT
      LAYER M4 ;
        RECT  107.916 46.608 108 46.632 ;
    END
  END rom_time[58]
  PIN rom_time[59]
    DIRECTION INPUT ;
    USE SIGNAL ;
    PORT
      LAYER M4 ;
        RECT  107.916 46.704 108 46.728 ;
    END
  END rom_time[59]
  PIN rom_time[5]
    DIRECTION INPUT ;
    USE SIGNAL ;
    PORT
      LAYER M4 ;
        RECT  107.916 50.736 108 50.76 ;
    END
  END rom_time[5]
  PIN rom_time[60]
    DIRECTION INPUT ;
    USE SIGNAL ;
    PORT
      LAYER M4 ;
        RECT  107.916 46.8 108 46.824 ;
    END
  END rom_time[60]
  PIN rom_time[61]
    DIRECTION INPUT ;
    USE SIGNAL ;
    PORT
      LAYER M4 ;
        RECT  107.916 46.896 108 46.92 ;
    END
  END rom_time[61]
  PIN rom_time[62]
    DIRECTION INPUT ;
    USE SIGNAL ;
    PORT
      LAYER M4 ;
        RECT  107.916 46.992 108 47.016 ;
    END
  END rom_time[62]
  PIN rom_time[63]
    DIRECTION INPUT ;
    USE SIGNAL ;
    PORT
      LAYER M4 ;
        RECT  107.916 47.088 108 47.112 ;
    END
  END rom_time[63]
  PIN rom_time[64]
    DIRECTION INPUT ;
    USE SIGNAL ;
    PORT
      LAYER M4 ;
        RECT  107.916 47.184 108 47.208 ;
    END
  END rom_time[64]
  PIN rom_time[65]
    DIRECTION INPUT ;
    USE SIGNAL ;
    PORT
      LAYER M4 ;
        RECT  107.916 47.28 108 47.304 ;
    END
  END rom_time[65]
  PIN rom_time[66]
    DIRECTION INPUT ;
    USE SIGNAL ;
    PORT
      LAYER M4 ;
        RECT  107.916 47.376 108 47.4 ;
    END
  END rom_time[66]
  PIN rom_time[67]
    DIRECTION INPUT ;
    USE SIGNAL ;
    PORT
      LAYER M4 ;
        RECT  107.916 47.472 108 47.496 ;
    END
  END rom_time[67]
  PIN rom_time[68]
    DIRECTION INPUT ;
    USE SIGNAL ;
    PORT
      LAYER M4 ;
        RECT  107.916 47.568 108 47.592 ;
    END
  END rom_time[68]
  PIN rom_time[69]
    DIRECTION INPUT ;
    USE SIGNAL ;
    PORT
      LAYER M4 ;
        RECT  107.916 47.664 108 47.688 ;
    END
  END rom_time[69]
  PIN rom_time[6]
    DIRECTION INPUT ;
    USE SIGNAL ;
    PORT
      LAYER M4 ;
        RECT  107.916 50.832 108 50.856 ;
    END
  END rom_time[6]
  PIN rom_time[70]
    DIRECTION INPUT ;
    USE SIGNAL ;
    PORT
      LAYER M4 ;
        RECT  107.916 47.76 108 47.784 ;
    END
  END rom_time[70]
  PIN rom_time[71]
    DIRECTION INPUT ;
    USE SIGNAL ;
    PORT
      LAYER M4 ;
        RECT  107.916 47.856 108 47.88 ;
    END
  END rom_time[71]
  PIN rom_time[7]
    DIRECTION INPUT ;
    USE SIGNAL ;
    PORT
      LAYER M4 ;
        RECT  107.916 50.928 108 50.952 ;
    END
  END rom_time[7]
  PIN rom_time[8]
    DIRECTION INPUT ;
    USE SIGNAL ;
    PORT
      LAYER M4 ;
        RECT  107.916 51.024 108 51.048 ;
    END
  END rom_time[8]
  PIN rom_time[9]
    DIRECTION INPUT ;
    USE SIGNAL ;
    PORT
      LAYER M4 ;
        RECT  107.916 51.12 108 51.144 ;
    END
  END rom_time[9]
  PIN rst_n
    DIRECTION INPUT ;
    USE SIGNAL ;
    PORT
      LAYER M5 ;
        RECT  39.216 0 39.24 0.084 ;
    END
  END rst_n
  PIN stage_start
    DIRECTION INPUT ;
    USE SIGNAL ;
    PORT
      LAYER M4 ;
        RECT  0 49.584 0.084 49.608 ;
    END
  END stage_start
  PIN VDD
    DIRECTION INOUT ;
    USE POWER ;
    PORT
      LAYER M5 ;
        RECT  105.192 2.151 105.312 105.849 ;
        RECT  99.792 2.151 99.912 105.849 ;
        RECT  94.392 2.151 94.512 105.849 ;
        RECT  88.992 2.151 89.112 105.849 ;
        RECT  83.592 2.151 83.712 105.849 ;
        RECT  78.192 2.151 78.312 105.849 ;
        RECT  72.792 2.151 72.912 105.849 ;
        RECT  67.392 2.151 67.512 105.849 ;
        RECT  61.992 2.151 62.112 105.849 ;
        RECT  56.592 2.151 56.712 105.849 ;
        RECT  51.192 2.151 51.312 105.849 ;
        RECT  45.792 2.151 45.912 105.849 ;
        RECT  40.392 2.151 40.512 105.849 ;
        RECT  34.992 2.151 35.112 105.849 ;
        RECT  29.592 2.151 29.712 105.849 ;
        RECT  24.192 2.151 24.312 105.849 ;
        RECT  18.792 2.151 18.912 105.849 ;
        RECT  13.392 2.151 13.512 105.849 ;
        RECT  7.992 2.151 8.112 105.849 ;
        RECT  2.592 2.151 2.712 105.849 ;
    END
  END VDD
  PIN VSS
    DIRECTION INOUT ;
    USE GROUND ;
    PORT
      LAYER M5 ;
        RECT  105 2.137 105.12 105.863 ;
        RECT  99.6 2.137 99.72 105.863 ;
        RECT  94.2 2.137 94.32 105.863 ;
        RECT  88.8 2.137 88.92 105.863 ;
        RECT  83.4 2.137 83.52 105.863 ;
        RECT  78 2.137 78.12 105.863 ;
        RECT  72.6 2.137 72.72 105.863 ;
        RECT  67.2 2.137 67.32 105.863 ;
        RECT  61.8 2.137 61.92 105.863 ;
        RECT  56.4 2.137 56.52 105.863 ;
        RECT  51 2.137 51.12 105.863 ;
        RECT  45.6 2.137 45.72 105.863 ;
        RECT  40.2 2.137 40.32 105.863 ;
        RECT  34.8 2.137 34.92 105.863 ;
        RECT  29.4 2.137 29.52 105.863 ;
        RECT  24 2.137 24.12 105.863 ;
        RECT  18.6 2.137 18.72 105.863 ;
        RECT  13.2 2.137 13.32 105.863 ;
        RECT  7.8 2.137 7.92 105.863 ;
        RECT  2.4 2.137 2.52 105.863 ;
    END
  END VSS
  # OT_OBS_CLOSED layer=M5 d_um=1.536 added=90
  OBS
    LAYER RVTN ;
     RECT  2.16 2.16 105.84 2.295 ;
     RECT  2.16 2.565 105.84 2.835 ;
     RECT  2.16 3.105 105.84 3.375 ;
     RECT  2.16 3.645 105.84 3.915 ;
     RECT  2.16 4.185 105.84 4.455 ;
     RECT  2.16 4.725 105.84 4.995 ;
     RECT  2.16 5.265 105.84 5.535 ;
     RECT  2.16 5.805 105.84 6.075 ;
     RECT  2.16 6.345 105.84 6.615 ;
     RECT  2.16 6.885 105.84 7.155 ;
     RECT  2.16 7.425 105.84 7.695 ;
     RECT  2.16 7.965 105.84 8.235 ;
     RECT  2.16 8.505 105.84 8.775 ;
     RECT  2.16 9.045 105.84 9.315 ;
     RECT  2.16 9.585 105.84 9.855 ;
     RECT  2.16 10.125 105.84 10.395 ;
     RECT  2.16 10.665 105.84 10.935 ;
     RECT  2.16 11.205 105.84 11.475 ;
     RECT  2.16 11.745 105.84 12.015 ;
     RECT  2.16 12.285 105.84 12.555 ;
     RECT  2.16 12.825 105.84 13.095 ;
     RECT  2.16 13.365 105.84 13.635 ;
     RECT  2.16 13.905 105.84 14.175 ;
     RECT  2.16 14.445 105.84 14.715 ;
     RECT  2.16 14.985 105.84 15.255 ;
     RECT  2.16 15.525 105.84 15.795 ;
     RECT  2.16 16.065 105.84 16.335 ;
     RECT  2.16 16.605 105.84 16.875 ;
     RECT  2.16 17.145 105.84 17.415 ;
     RECT  2.16 17.685 105.84 17.955 ;
     RECT  2.16 18.225 105.84 18.495 ;
     RECT  2.16 18.765 105.84 19.035 ;
     RECT  2.16 19.305 105.84 19.575 ;
     RECT  2.16 19.845 105.84 20.115 ;
     RECT  2.16 20.385 105.84 20.655 ;
     RECT  2.16 20.925 105.84 21.195 ;
     RECT  2.16 21.465 105.84 21.735 ;
     RECT  2.16 22.005 105.84 22.275 ;
     RECT  2.16 22.545 105.84 22.815 ;
     RECT  2.16 23.085 105.84 23.355 ;
     RECT  2.16 23.625 105.84 23.895 ;
     RECT  2.16 24.165 105.84 24.435 ;
     RECT  2.16 24.705 105.84 24.975 ;
     RECT  2.16 25.245 105.84 25.515 ;
     RECT  2.16 25.785 105.84 26.055 ;
     RECT  2.16 26.325 105.84 26.595 ;
     RECT  2.16 26.865 105.84 27.135 ;
     RECT  2.16 27.405 105.84 27.675 ;
     RECT  2.16 27.945 105.84 28.215 ;
     RECT  2.16 28.485 105.84 28.755 ;
     RECT  2.16 29.025 105.84 29.295 ;
     RECT  2.16 29.565 105.84 29.835 ;
     RECT  2.16 30.105 105.84 30.375 ;
     RECT  2.16 30.645 105.84 30.915 ;
     RECT  2.16 31.185 105.84 31.455 ;
     RECT  2.16 31.725 105.84 31.995 ;
     RECT  2.16 32.265 105.84 32.535 ;
     RECT  2.16 32.805 105.84 33.075 ;
     RECT  2.16 33.345 105.84 33.615 ;
     RECT  2.16 33.885 105.84 34.155 ;
     RECT  2.16 34.425 105.84 34.695 ;
     RECT  2.16 34.965 105.84 35.235 ;
     RECT  2.16 35.505 105.84 35.775 ;
     RECT  2.16 36.045 105.84 36.315 ;
     RECT  2.16 36.585 105.84 36.855 ;
     RECT  2.16 37.125 105.84 37.395 ;
     RECT  2.16 37.665 105.84 37.935 ;
     RECT  2.16 38.205 105.84 38.475 ;
     RECT  2.16 38.745 105.84 39.015 ;
     RECT  2.16 39.285 105.84 39.555 ;
     RECT  2.16 39.825 105.84 40.095 ;
     RECT  2.16 40.365 105.84 40.635 ;
     RECT  2.16 40.905 105.84 41.175 ;
     RECT  2.16 41.445 105.84 41.715 ;
     RECT  2.16 41.985 105.84 42.255 ;
     RECT  2.16 42.525 105.84 42.795 ;
     RECT  2.16 43.065 105.84 43.335 ;
     RECT  2.16 43.605 105.84 43.875 ;
     RECT  2.16 44.145 105.84 44.415 ;
     RECT  2.16 44.685 105.84 44.955 ;
     RECT  2.16 45.225 105.84 45.495 ;
     RECT  2.16 45.765 105.84 46.035 ;
     RECT  2.16 46.305 105.84 46.575 ;
     RECT  2.16 46.845 105.84 47.115 ;
     RECT  2.16 47.385 105.84 47.655 ;
     RECT  2.16 47.925 105.84 48.195 ;
     RECT  2.16 48.465 105.84 48.735 ;
     RECT  2.16 49.005 105.84 49.275 ;
     RECT  2.16 49.545 105.84 49.815 ;
     RECT  2.16 50.085 105.84 50.355 ;
     RECT  2.16 50.625 105.84 50.895 ;
     RECT  2.16 51.165 105.84 51.435 ;
     RECT  2.16 51.705 105.84 51.975 ;
     RECT  2.16 52.245 105.84 52.515 ;
     RECT  2.16 52.785 105.84 53.055 ;
     RECT  2.16 53.325 105.84 53.595 ;
     RECT  2.16 53.865 105.84 54.135 ;
     RECT  2.16 54.405 105.84 54.675 ;
     RECT  2.16 54.945 105.84 55.215 ;
     RECT  2.16 55.485 105.84 55.755 ;
     RECT  2.16 56.025 105.84 56.295 ;
     RECT  2.16 56.565 105.84 56.835 ;
     RECT  2.16 57.105 105.84 57.375 ;
     RECT  2.16 57.645 105.84 57.915 ;
     RECT  2.16 58.185 105.84 58.455 ;
     RECT  2.16 58.725 105.84 58.995 ;
     RECT  2.16 59.265 105.84 59.535 ;
     RECT  2.16 59.805 105.84 60.075 ;
     RECT  2.16 60.345 105.84 60.615 ;
     RECT  2.16 60.885 105.84 61.155 ;
     RECT  2.16 61.425 105.84 61.695 ;
     RECT  2.16 61.965 105.84 62.235 ;
     RECT  2.16 62.505 105.84 62.775 ;
     RECT  2.16 63.045 105.84 63.315 ;
     RECT  2.16 63.585 105.84 63.855 ;
     RECT  2.16 64.125 105.84 64.395 ;
     RECT  2.16 64.665 105.84 64.935 ;
     RECT  2.16 65.205 105.84 65.475 ;
     RECT  2.16 65.745 105.84 66.015 ;
     RECT  2.16 66.285 105.84 66.555 ;
     RECT  2.16 66.825 105.84 67.095 ;
     RECT  2.16 67.365 105.84 67.635 ;
     RECT  2.16 67.905 105.84 68.175 ;
     RECT  2.16 68.445 105.84 68.715 ;
     RECT  2.16 68.985 105.84 69.255 ;
     RECT  2.16 69.525 105.84 69.795 ;
     RECT  2.16 70.065 105.84 70.335 ;
     RECT  2.16 70.605 105.84 70.875 ;
     RECT  2.16 71.145 105.84 71.415 ;
     RECT  2.16 71.685 105.84 71.955 ;
     RECT  2.16 72.225 105.84 72.495 ;
     RECT  2.16 72.765 105.84 73.035 ;
     RECT  2.16 73.305 105.84 73.575 ;
     RECT  2.16 73.845 105.84 74.115 ;
     RECT  2.16 74.385 105.84 74.655 ;
     RECT  2.16 74.925 105.84 75.195 ;
     RECT  2.16 75.465 105.84 75.735 ;
     RECT  2.16 76.005 105.84 76.275 ;
     RECT  2.16 76.545 105.84 76.815 ;
     RECT  2.16 77.085 105.84 77.355 ;
     RECT  2.16 77.625 105.84 77.895 ;
     RECT  2.16 78.165 105.84 78.435 ;
     RECT  2.16 78.705 105.84 78.975 ;
     RECT  2.16 79.245 105.84 79.515 ;
     RECT  2.16 79.785 105.84 80.055 ;
     RECT  2.16 80.325 105.84 80.595 ;
     RECT  2.16 80.865 105.84 81.135 ;
     RECT  2.16 81.405 105.84 81.675 ;
     RECT  2.16 81.945 105.84 82.215 ;
     RECT  2.16 82.485 105.84 82.755 ;
     RECT  2.16 83.025 105.84 83.295 ;
     RECT  2.16 83.565 105.84 83.835 ;
     RECT  2.16 84.105 105.84 84.375 ;
     RECT  2.16 84.645 105.84 84.915 ;
     RECT  2.16 85.185 105.84 85.455 ;
     RECT  2.16 85.725 105.84 85.995 ;
     RECT  2.16 86.265 105.84 86.535 ;
     RECT  2.16 86.805 105.84 87.075 ;
     RECT  2.16 87.345 105.84 87.615 ;
     RECT  2.16 87.885 105.84 88.155 ;
     RECT  2.16 88.425 105.84 88.695 ;
     RECT  2.16 88.965 105.84 89.235 ;
     RECT  2.16 89.505 105.84 89.775 ;
     RECT  2.16 90.045 105.84 90.315 ;
     RECT  2.16 90.585 105.84 90.855 ;
     RECT  2.16 91.125 105.84 91.395 ;
     RECT  2.16 91.665 105.84 91.935 ;
     RECT  2.16 92.205 105.84 92.475 ;
     RECT  2.16 92.745 105.84 93.015 ;
     RECT  2.16 93.285 105.84 93.555 ;
     RECT  2.16 93.825 105.84 94.095 ;
     RECT  2.16 94.365 105.84 94.635 ;
     RECT  2.16 94.905 105.84 95.175 ;
     RECT  2.16 95.445 105.84 95.715 ;
     RECT  2.16 95.985 105.84 96.255 ;
     RECT  2.16 96.525 105.84 96.795 ;
     RECT  2.16 97.065 105.84 97.335 ;
     RECT  2.16 97.605 105.84 97.875 ;
     RECT  2.16 98.145 105.84 98.415 ;
     RECT  2.16 98.685 105.84 98.955 ;
     RECT  2.16 99.225 105.84 99.495 ;
     RECT  2.16 99.765 105.84 100.035 ;
     RECT  2.16 100.305 105.84 100.575 ;
     RECT  2.16 100.845 105.84 101.115 ;
     RECT  2.16 101.385 105.84 101.655 ;
     RECT  2.16 101.925 105.84 102.195 ;
     RECT  2.16 102.465 105.84 102.735 ;
     RECT  2.16 103.005 105.84 103.275 ;
     RECT  2.16 103.545 105.84 103.815 ;
     RECT  2.16 104.085 105.84 104.355 ;
     RECT  2.16 104.625 105.84 104.895 ;
     RECT  2.16 105.165 105.84 105.435 ;
     RECT  2.16 105.705 105.84 105.84 ;
    LAYER RVTP ;
     RECT  2.16 2.295 105.84 2.565 ;
     RECT  2.16 2.835 105.84 3.105 ;
     RECT  2.16 3.375 105.84 3.645 ;
     RECT  2.16 3.915 105.84 4.185 ;
     RECT  2.16 4.455 105.84 4.725 ;
     RECT  2.16 4.995 105.84 5.265 ;
     RECT  2.16 5.535 105.84 5.805 ;
     RECT  2.16 6.075 105.84 6.345 ;
     RECT  2.16 6.615 105.84 6.885 ;
     RECT  2.16 7.155 105.84 7.425 ;
     RECT  2.16 7.695 105.84 7.965 ;
     RECT  2.16 8.235 105.84 8.505 ;
     RECT  2.16 8.775 105.84 9.045 ;
     RECT  2.16 9.315 105.84 9.585 ;
     RECT  2.16 9.855 105.84 10.125 ;
     RECT  2.16 10.395 105.84 10.665 ;
     RECT  2.16 10.935 105.84 11.205 ;
     RECT  2.16 11.475 105.84 11.745 ;
     RECT  2.16 12.015 105.84 12.285 ;
     RECT  2.16 12.555 105.84 12.825 ;
     RECT  2.16 13.095 105.84 13.365 ;
     RECT  2.16 13.635 105.84 13.905 ;
     RECT  2.16 14.175 105.84 14.445 ;
     RECT  2.16 14.715 105.84 14.985 ;
     RECT  2.16 15.255 105.84 15.525 ;
     RECT  2.16 15.795 105.84 16.065 ;
     RECT  2.16 16.335 105.84 16.605 ;
     RECT  2.16 16.875 105.84 17.145 ;
     RECT  2.16 17.415 105.84 17.685 ;
     RECT  2.16 17.955 105.84 18.225 ;
     RECT  2.16 18.495 105.84 18.765 ;
     RECT  2.16 19.035 105.84 19.305 ;
     RECT  2.16 19.575 105.84 19.845 ;
     RECT  2.16 20.115 105.84 20.385 ;
     RECT  2.16 20.655 105.84 20.925 ;
     RECT  2.16 21.195 105.84 21.465 ;
     RECT  2.16 21.735 105.84 22.005 ;
     RECT  2.16 22.275 105.84 22.545 ;
     RECT  2.16 22.815 105.84 23.085 ;
     RECT  2.16 23.355 105.84 23.625 ;
     RECT  2.16 23.895 105.84 24.165 ;
     RECT  2.16 24.435 105.84 24.705 ;
     RECT  2.16 24.975 105.84 25.245 ;
     RECT  2.16 25.515 105.84 25.785 ;
     RECT  2.16 26.055 105.84 26.325 ;
     RECT  2.16 26.595 105.84 26.865 ;
     RECT  2.16 27.135 105.84 27.405 ;
     RECT  2.16 27.675 105.84 27.945 ;
     RECT  2.16 28.215 105.84 28.485 ;
     RECT  2.16 28.755 105.84 29.025 ;
     RECT  2.16 29.295 105.84 29.565 ;
     RECT  2.16 29.835 105.84 30.105 ;
     RECT  2.16 30.375 105.84 30.645 ;
     RECT  2.16 30.915 105.84 31.185 ;
     RECT  2.16 31.455 105.84 31.725 ;
     RECT  2.16 31.995 105.84 32.265 ;
     RECT  2.16 32.535 105.84 32.805 ;
     RECT  2.16 33.075 105.84 33.345 ;
     RECT  2.16 33.615 105.84 33.885 ;
     RECT  2.16 34.155 105.84 34.425 ;
     RECT  2.16 34.695 105.84 34.965 ;
     RECT  2.16 35.235 105.84 35.505 ;
     RECT  2.16 35.775 105.84 36.045 ;
     RECT  2.16 36.315 105.84 36.585 ;
     RECT  2.16 36.855 105.84 37.125 ;
     RECT  2.16 37.395 105.84 37.665 ;
     RECT  2.16 37.935 105.84 38.205 ;
     RECT  2.16 38.475 105.84 38.745 ;
     RECT  2.16 39.015 105.84 39.285 ;
     RECT  2.16 39.555 105.84 39.825 ;
     RECT  2.16 40.095 105.84 40.365 ;
     RECT  2.16 40.635 105.84 40.905 ;
     RECT  2.16 41.175 105.84 41.445 ;
     RECT  2.16 41.715 105.84 41.985 ;
     RECT  2.16 42.255 105.84 42.525 ;
     RECT  2.16 42.795 105.84 43.065 ;
     RECT  2.16 43.335 105.84 43.605 ;
     RECT  2.16 43.875 105.84 44.145 ;
     RECT  2.16 44.415 105.84 44.685 ;
     RECT  2.16 44.955 105.84 45.225 ;
     RECT  2.16 45.495 105.84 45.765 ;
     RECT  2.16 46.035 105.84 46.305 ;
     RECT  2.16 46.575 105.84 46.845 ;
     RECT  2.16 47.115 105.84 47.385 ;
     RECT  2.16 47.655 105.84 47.925 ;
     RECT  2.16 48.195 105.84 48.465 ;
     RECT  2.16 48.735 105.84 49.005 ;
     RECT  2.16 49.275 105.84 49.545 ;
     RECT  2.16 49.815 105.84 50.085 ;
     RECT  2.16 50.355 105.84 50.625 ;
     RECT  2.16 50.895 105.84 51.165 ;
     RECT  2.16 51.435 105.84 51.705 ;
     RECT  2.16 51.975 105.84 52.245 ;
     RECT  2.16 52.515 105.84 52.785 ;
     RECT  2.16 53.055 105.84 53.325 ;
     RECT  2.16 53.595 105.84 53.865 ;
     RECT  2.16 54.135 105.84 54.405 ;
     RECT  2.16 54.675 105.84 54.945 ;
     RECT  2.16 55.215 105.84 55.485 ;
     RECT  2.16 55.755 105.84 56.025 ;
     RECT  2.16 56.295 105.84 56.565 ;
     RECT  2.16 56.835 105.84 57.105 ;
     RECT  2.16 57.375 105.84 57.645 ;
     RECT  2.16 57.915 105.84 58.185 ;
     RECT  2.16 58.455 105.84 58.725 ;
     RECT  2.16 58.995 105.84 59.265 ;
     RECT  2.16 59.535 105.84 59.805 ;
     RECT  2.16 60.075 105.84 60.345 ;
     RECT  2.16 60.615 105.84 60.885 ;
     RECT  2.16 61.155 105.84 61.425 ;
     RECT  2.16 61.695 105.84 61.965 ;
     RECT  2.16 62.235 105.84 62.505 ;
     RECT  2.16 62.775 105.84 63.045 ;
     RECT  2.16 63.315 105.84 63.585 ;
     RECT  2.16 63.855 105.84 64.125 ;
     RECT  2.16 64.395 105.84 64.665 ;
     RECT  2.16 64.935 105.84 65.205 ;
     RECT  2.16 65.475 105.84 65.745 ;
     RECT  2.16 66.015 105.84 66.285 ;
     RECT  2.16 66.555 105.84 66.825 ;
     RECT  2.16 67.095 105.84 67.365 ;
     RECT  2.16 67.635 105.84 67.905 ;
     RECT  2.16 68.175 105.84 68.445 ;
     RECT  2.16 68.715 105.84 68.985 ;
     RECT  2.16 69.255 105.84 69.525 ;
     RECT  2.16 69.795 105.84 70.065 ;
     RECT  2.16 70.335 105.84 70.605 ;
     RECT  2.16 70.875 105.84 71.145 ;
     RECT  2.16 71.415 105.84 71.685 ;
     RECT  2.16 71.955 105.84 72.225 ;
     RECT  2.16 72.495 105.84 72.765 ;
     RECT  2.16 73.035 105.84 73.305 ;
     RECT  2.16 73.575 105.84 73.845 ;
     RECT  2.16 74.115 105.84 74.385 ;
     RECT  2.16 74.655 105.84 74.925 ;
     RECT  2.16 75.195 105.84 75.465 ;
     RECT  2.16 75.735 105.84 76.005 ;
     RECT  2.16 76.275 105.84 76.545 ;
     RECT  2.16 76.815 105.84 77.085 ;
     RECT  2.16 77.355 105.84 77.625 ;
     RECT  2.16 77.895 105.84 78.165 ;
     RECT  2.16 78.435 105.84 78.705 ;
     RECT  2.16 78.975 105.84 79.245 ;
     RECT  2.16 79.515 105.84 79.785 ;
     RECT  2.16 80.055 105.84 80.325 ;
     RECT  2.16 80.595 105.84 80.865 ;
     RECT  2.16 81.135 105.84 81.405 ;
     RECT  2.16 81.675 105.84 81.945 ;
     RECT  2.16 82.215 105.84 82.485 ;
     RECT  2.16 82.755 105.84 83.025 ;
     RECT  2.16 83.295 105.84 83.565 ;
     RECT  2.16 83.835 105.84 84.105 ;
     RECT  2.16 84.375 105.84 84.645 ;
     RECT  2.16 84.915 105.84 85.185 ;
     RECT  2.16 85.455 105.84 85.725 ;
     RECT  2.16 85.995 105.84 86.265 ;
     RECT  2.16 86.535 105.84 86.805 ;
     RECT  2.16 87.075 105.84 87.345 ;
     RECT  2.16 87.615 105.84 87.885 ;
     RECT  2.16 88.155 105.84 88.425 ;
     RECT  2.16 88.695 105.84 88.965 ;
     RECT  2.16 89.235 105.84 89.505 ;
     RECT  2.16 89.775 105.84 90.045 ;
     RECT  2.16 90.315 105.84 90.585 ;
     RECT  2.16 90.855 105.84 91.125 ;
     RECT  2.16 91.395 105.84 91.665 ;
     RECT  2.16 91.935 105.84 92.205 ;
     RECT  2.16 92.475 105.84 92.745 ;
     RECT  2.16 93.015 105.84 93.285 ;
     RECT  2.16 93.555 105.84 93.825 ;
     RECT  2.16 94.095 105.84 94.365 ;
     RECT  2.16 94.635 105.84 94.905 ;
     RECT  2.16 95.175 105.84 95.445 ;
     RECT  2.16 95.715 105.84 95.985 ;
     RECT  2.16 96.255 105.84 96.525 ;
     RECT  2.16 96.795 105.84 97.065 ;
     RECT  2.16 97.335 105.84 97.605 ;
     RECT  2.16 97.875 105.84 98.145 ;
     RECT  2.16 98.415 105.84 98.685 ;
     RECT  2.16 98.955 105.84 99.225 ;
     RECT  2.16 99.495 105.84 99.765 ;
     RECT  2.16 100.035 105.84 100.305 ;
     RECT  2.16 100.575 105.84 100.845 ;
     RECT  2.16 101.115 105.84 101.385 ;
     RECT  2.16 101.655 105.84 101.925 ;
     RECT  2.16 102.195 105.84 102.465 ;
     RECT  2.16 102.735 105.84 103.005 ;
     RECT  2.16 103.275 105.84 103.545 ;
     RECT  2.16 103.815 105.84 104.085 ;
     RECT  2.16 104.355 105.84 104.625 ;
     RECT  2.16 104.895 105.84 105.165 ;
     RECT  2.16 105.435 105.84 105.705 ;
    LAYER M1 ;
     RECT  2.16 2.151 105.84 105.849 ;
    LAYER M2 ;
     RECT  0.031 36.936 0.067 36.954 ;
     RECT  0.031 40.536 0.067 40.554 ;
     RECT  0.067 36.396 0.103 36.954 ;
     RECT  0.067 40.536 0.103 40.86 ;
     RECT  0.103 39.798 0.131 40.86 ;
     RECT  0.131 39.798 0.139 39.888 ;
     RECT  0.031 50.706 0.139 50.769 ;
     RECT  0.103 60.084 0.139 60.102 ;
     RECT  0.131 40.842 0.167 40.86 ;
     RECT  0.067 43.848 0.167 43.866 ;
     RECT  0.139 47.736 0.175 47.754 ;
     RECT  0.103 48.744 0.175 48.762 ;
     RECT  0.139 59.616 0.175 60.102 ;
     RECT  0.103 36.396 0.211 37.584 ;
     RECT  0.175 52.866 0.211 52.884 ;
     RECT  0.103 54.108 0.211 54.702 ;
     RECT  0.211 36.396 0.283 38.034 ;
     RECT  0.139 39.294 0.283 39.888 ;
     RECT  0.211 44.964 0.347 44.982 ;
     RECT  0.103 42.156 0.463 42.174 ;
     RECT  0.463 42.066 0.499 42.75 ;
     RECT  0.175 59.346 0.499 60.102 ;
     RECT  0.139 50.706 0.535 51.264 ;
     RECT  0.499 42.03 0.563 42.75 ;
     RECT  0.067 46.89 1.219 46.908 ;
     RECT  0.175 47.736 1.219 48.762 ;
     RECT  1.363 45.846 1.399 45.864 ;
     RECT  0.535 50.706 1.723 51.732 ;
     RECT  1.399 45.846 1.795 46.062 ;
     RECT  1.219 46.89 1.795 48.762 ;
     RECT  0.283 36.396 2.16 39.888 ;
     RECT  0.563 42.03 2.16 42.174 ;
     RECT  1.795 45.774 2.16 48.762 ;
     RECT  1.723 50.436 2.16 51.732 ;
     RECT  0.211 52.866 2.16 54.702 ;
     RECT  0.499 59.004 2.16 60.102 ;
     RECT  2.16 2.151 105.84 105.849 ;
     RECT  105.84 41.112 106.007 49.5 ;
     RECT  106.007 41.112 106.043 49.464 ;
     RECT  105.84 50.256 106.043 58.482 ;
     RECT  106.043 41.256 106.079 49.464 ;
     RECT  106.079 41.382 106.583 49.464 ;
     RECT  106.043 58.122 106.583 58.482 ;
     RECT  106.583 41.382 106.655 49.194 ;
     RECT  106.655 42.228 106.691 49.194 ;
     RECT  106.043 50.256 107.051 57.33 ;
     RECT  107.051 50.256 107.123 57.096 ;
     RECT  106.691 42.228 107.159 47.574 ;
     RECT  106.691 49.176 107.159 49.194 ;
     RECT  107.123 50.256 107.159 55.512 ;
     RECT  107.159 42.228 107.195 43.29 ;
     RECT  107.159 44.19 107.195 44.514 ;
     RECT  107.159 45.666 107.195 47.574 ;
     RECT  107.123 56.304 107.195 57.096 ;
     RECT  107.195 42.534 107.231 43.29 ;
     RECT  107.195 45.666 107.231 45.828 ;
     RECT  107.159 50.364 107.879 51.264 ;
     RECT  107.159 52.524 107.879 55.512 ;
     RECT  106.655 41.382 107.915 41.4 ;
     RECT  107.195 44.496 107.915 44.514 ;
     RECT  107.231 45.666 107.915 45.684 ;
     RECT  107.195 46.89 107.915 46.908 ;
     RECT  107.879 50.832 107.915 51.264 ;
     RECT  107.879 52.524 107.915 53.154 ;
     RECT  107.879 54.036 107.915 55.278 ;
     RECT  107.195 56.304 107.915 57.024 ;
     RECT  106.583 58.464 107.915 58.482 ;
     RECT  107.231 42.534 107.951 42.786 ;
    LAYER M3 ;
     RECT  2.415 2.143 2.505 2.413 ;
     RECT  7.815 2.143 7.905 2.413 ;
     RECT  13.215 2.143 13.305 2.413 ;
     RECT  18.615 2.143 18.705 2.413 ;
     RECT  24.015 2.143 24.105 2.413 ;
     RECT  29.415 2.143 29.505 2.413 ;
     RECT  34.815 2.143 34.905 2.413 ;
     RECT  40.215 2.143 40.305 2.413 ;
     RECT  45.615 2.143 45.705 2.413 ;
     RECT  51.015 2.143 51.105 2.413 ;
     RECT  56.415 2.143 56.505 2.413 ;
     RECT  61.815 2.143 61.905 2.413 ;
     RECT  67.215 2.143 67.305 2.413 ;
     RECT  72.615 2.143 72.705 2.413 ;
     RECT  78.015 2.143 78.105 2.413 ;
     RECT  83.415 2.143 83.505 2.413 ;
     RECT  88.815 2.143 88.905 2.413 ;
     RECT  94.215 2.143 94.305 2.413 ;
     RECT  99.615 2.143 99.705 2.413 ;
     RECT  105.015 2.143 105.105 2.413 ;
     RECT  40.215 2.413 40.497 23.371 ;
     RECT  39.492 23.371 40.497 23.855 ;
     RECT  2.415 2.413 2.697 36.121 ;
     RECT  2.34 36.121 2.826 36.355 ;
     RECT  2.304 36.355 2.826 36.625 ;
     RECT  1.404 36.661 1.422 36.859 ;
     RECT  2.304 36.625 3.33 36.859 ;
     RECT  0.072 36.391 0.09 36.931 ;
     RECT  2.304 36.859 3.51 36.931 ;
     RECT  4.428 36.859 4.446 36.931 ;
     RECT  2.304 36.931 3.618 37.021 ;
     RECT  4.392 36.931 4.446 37.021 ;
     RECT  29.415 2.413 29.697 37.021 ;
     RECT  2.304 37.021 4.446 37.201 ;
     RECT  29.415 37.021 30.222 37.201 ;
     RECT  29.415 37.201 30.546 37.355 ;
     RECT  34.815 2.413 35.097 37.363 ;
     RECT  31.68 37.363 31.698 37.399 ;
     RECT  31.392 37.399 31.698 37.435 ;
     RECT  32.652 37.399 32.67 37.435 ;
     RECT  0.036 36.931 0.09 37.471 ;
     RECT  0.828 36.859 1.422 37.471 ;
     RECT  31.32 37.435 33.174 37.561 ;
     RECT  34.344 37.363 35.097 37.561 ;
     RECT  45.615 2.413 45.897 37.561 ;
     RECT  34.344 37.561 35.226 37.579 ;
     RECT  44.352 37.561 44.37 37.579 ;
     RECT  31.176 37.561 33.174 37.589 ;
     RECT  7.815 2.413 8.097 37.597 ;
     RECT  44.208 37.579 44.37 37.625 ;
     RECT  2.304 37.201 4.734 37.741 ;
     RECT  25.092 37.669 25.11 37.741 ;
     RECT  44.352 37.625 44.37 37.831 ;
     RECT  45.144 37.561 45.897 37.831 ;
     RECT  6.804 37.471 6.822 37.903 ;
     RECT  7.596 37.597 8.097 37.903 ;
     RECT  6.804 37.903 8.097 37.939 ;
     RECT  34.272 37.579 35.226 37.939 ;
     RECT  34.272 37.939 35.406 37.963 ;
     RECT  34.092 37.963 35.406 37.975 ;
     RECT  29.415 37.355 30.402 38.011 ;
     RECT  34.092 37.975 35.586 38.011 ;
     RECT  36.504 38.005 36.522 38.011 ;
     RECT  44.352 37.831 45.897 38.101 ;
     RECT  46.8 37.903 46.818 38.101 ;
     RECT  42.3 38.101 42.318 38.137 ;
     RECT  44.352 38.101 46.818 38.137 ;
     RECT  29.304 38.011 30.402 38.155 ;
     RECT  31.176 37.589 33.138 38.155 ;
     RECT  48.456 38.011 48.474 38.155 ;
     RECT  2.304 37.741 4.878 38.209 ;
     RECT  42.3 38.137 42.534 38.245 ;
     RECT  41.976 38.245 42.534 38.281 ;
     RECT  44.352 38.137 47.466 38.281 ;
     RECT  48.456 38.155 48.51 38.281 ;
     RECT  49.86 37.741 49.878 38.281 ;
     RECT  29.304 38.155 33.138 38.395 ;
     RECT  2.304 38.209 5.022 38.443 ;
     RECT  34.092 38.011 37.53 38.443 ;
     RECT  2.304 38.443 5.058 38.491 ;
     RECT  6.264 37.939 8.097 38.515 ;
     RECT  9 38.281 9.018 38.515 ;
     RECT  41.976 38.281 42.642 38.515 ;
     RECT  0.036 37.471 1.422 38.551 ;
     RECT  6.264 38.515 9.558 38.551 ;
     RECT  41.616 38.515 42.714 38.551 ;
     RECT  44.352 38.281 48.582 38.551 ;
     RECT  49.572 38.281 49.878 38.551 ;
     RECT  27.972 38.371 27.99 38.641 ;
     RECT  29.088 38.395 33.138 38.641 ;
     RECT  34.092 38.443 37.89 38.641 ;
     RECT  2.304 38.491 5.238 38.677 ;
     RECT  27.756 38.641 27.99 38.677 ;
     RECT  29.088 38.641 37.89 38.677 ;
     RECT  39.744 23.855 40.497 38.749 ;
     RECT  41.616 38.551 49.878 38.749 ;
     RECT  25.092 37.741 25.182 38.779 ;
     RECT  25.092 38.779 25.254 38.818 ;
     RECT  39.744 38.749 49.878 38.911 ;
     RECT  6.12 38.551 9.558 38.939 ;
     RECT  22.86 38.785 22.878 38.939 ;
     RECT  25.092 38.818 25.29 38.939 ;
     RECT  27.684 38.677 37.89 39.019 ;
     RECT  39.744 38.911 50.202 39.055 ;
     RECT  51.015 2.413 51.297 39.055 ;
     RECT  39.672 39.055 51.39 39.083 ;
     RECT  27.612 39.019 37.89 39.091 ;
     RECT  47.88 39.083 51.39 39.091 ;
     RECT  47.88 39.091 51.498 39.181 ;
     RECT  47.88 39.181 51.822 39.209 ;
     RECT  27.612 39.091 37.962 39.211 ;
     RECT  39.672 39.083 47.106 39.217 ;
     RECT  27.36 39.211 37.962 39.251 ;
     RECT  27.576 39.251 37.962 39.289 ;
     RECT  47.988 39.209 51.822 39.361 ;
     RECT  27.576 39.289 38.61 39.499 ;
     RECT  2.304 38.677 5.382 39.595 ;
     RECT  6.12 38.939 8.097 39.595 ;
     RECT  27.576 39.499 38.646 39.595 ;
     RECT  39.456 39.217 47.106 39.595 ;
     RECT  53.172 39.721 53.19 39.865 ;
     RECT  47.988 39.361 51.894 39.901 ;
     RECT  27.576 39.595 47.106 39.979 ;
     RECT  47.988 39.901 51.93 39.979 ;
     RECT  8.892 38.939 9.558 39.991 ;
     RECT  27.576 39.979 51.93 40.019 ;
     RECT  2.304 39.595 8.097 40.063 ;
     RECT  55.548 40.063 55.566 40.075 ;
     RECT  56.415 2.413 56.697 40.075 ;
     RECT  2.304 40.063 8.154 40.099 ;
     RECT  8.892 39.991 9.99 40.099 ;
     RECT  48.312 40.019 51.93 40.123 ;
     RECT  52.92 39.865 53.442 40.123 ;
     RECT  101.916 39.631 101.934 40.171 ;
     RECT  2.304 40.099 9.99 40.199 ;
     RECT  27.576 40.019 47.214 40.289 ;
     RECT  54.684 40.261 54.702 40.297 ;
     RECT  11.016 39.361 11.034 40.333 ;
     RECT  54.36 40.297 54.702 40.369 ;
     RECT  55.548 40.075 56.697 40.369 ;
     RECT  25.092 38.939 25.182 40.397 ;
     RECT  101.484 40.171 101.934 40.405 ;
     RECT  27.576 40.289 33.966 40.441 ;
     RECT  2.304 40.199 9.918 40.469 ;
     RECT  25.092 40.397 25.146 40.469 ;
     RECT  0.036 38.551 1.458 40.559 ;
     RECT  11.016 40.333 11.106 40.603 ;
     RECT  54.36 40.369 56.697 40.639 ;
     RECT  27.468 40.441 33.966 40.675 ;
     RECT  10.8 40.603 11.106 40.711 ;
     RECT  10.8 40.711 11.25 40.733 ;
     RECT  18.615 2.413 18.897 40.795 ;
     RECT  48.312 40.123 53.442 40.795 ;
     RECT  105.015 2.413 105.297 40.801 ;
     RECT  101.16 40.405 101.934 40.837 ;
     RECT  0.072 40.559 1.458 40.865 ;
     RECT  47.952 40.795 53.442 40.873 ;
     RECT  54.216 40.639 56.697 40.873 ;
     RECT  14.832 40.801 14.85 40.877 ;
     RECT  25.092 40.469 25.11 40.877 ;
     RECT  98.604 40.651 98.622 40.891 ;
     RECT  99.615 2.413 99.897 40.891 ;
     RECT  16.38 40.873 16.398 40.925 ;
     RECT  18.615 40.795 18.99 40.925 ;
     RECT  101.16 40.837 102.618 40.981 ;
     RECT  27.18 40.675 33.966 41.009 ;
     RECT  34.776 40.289 47.214 41.071 ;
     RECT  47.952 40.873 56.697 41.071 ;
     RECT  61.815 2.413 62.097 41.071 ;
     RECT  14.904 40.891 14.922 41.099 ;
     RECT  58.572 40.945 58.59 41.135 ;
     RECT  96.516 40.837 96.534 41.179 ;
     RECT  61.815 41.071 62.262 41.215 ;
     RECT  96.516 41.179 96.93 41.227 ;
     RECT  26.136 40.891 26.154 41.251 ;
     RECT  34.776 41.071 56.697 41.251 ;
     RECT  96.516 41.227 97.326 41.251 ;
     RECT  106.02 41.107 106.038 41.251 ;
     RECT  11.016 40.733 11.25 41.341 ;
     RECT  2.304 40.469 9.666 41.369 ;
     RECT  61.632 41.215 62.262 41.413 ;
     RECT  106.02 41.251 106.074 41.413 ;
     RECT  26.136 41.251 26.802 41.477 ;
     RECT  27.612 41.009 33.966 41.521 ;
     RECT  34.74 41.251 56.697 41.521 ;
     RECT  61.344 41.413 62.262 41.521 ;
     RECT  104.544 40.801 105.297 41.521 ;
     RECT  2.304 41.369 9.414 41.611 ;
     RECT  61.272 41.521 62.262 41.611 ;
     RECT  0.108 40.865 1.458 41.645 ;
     RECT  27.612 41.521 56.697 41.647 ;
     RECT  60.624 41.611 62.262 41.647 ;
     RECT  100.872 40.981 102.618 41.647 ;
     RECT  11.016 41.341 11.61 41.675 ;
     RECT  59.904 41.647 62.262 41.683 ;
     RECT  63.036 41.659 63.054 41.683 ;
     RECT  27.612 41.647 56.934 41.719 ;
     RECT  98.604 40.891 99.897 41.755 ;
     RECT  100.872 41.647 103.23 41.755 ;
     RECT  59.904 41.683 63.054 41.791 ;
     RECT  98.604 41.755 103.23 41.791 ;
     RECT  104.4 41.521 105.297 41.791 ;
     RECT  1.44 41.645 1.458 41.837 ;
     RECT  58.896 41.215 58.914 41.881 ;
     RECT  59.868 41.791 63.054 41.881 ;
     RECT  2.268 41.611 9.414 41.909 ;
     RECT  98.604 41.791 105.297 41.909 ;
     RECT  59.868 41.881 63.234 41.917 ;
     RECT  27.612 41.719 57.006 41.947 ;
     RECT  106.02 41.413 106.614 41.953 ;
     RECT  27.612 41.947 57.618 41.989 ;
     RECT  59.724 41.917 63.234 41.989 ;
     RECT  64.476 41.947 64.494 41.989 ;
     RECT  22.824 41.683 22.842 42.017 ;
     RECT  95.796 41.251 97.326 42.025 ;
     RECT  102.564 41.909 105.297 42.025 ;
     RECT  106.02 41.953 106.65 42.025 ;
     RECT  58.716 41.881 58.914 42.061 ;
     RECT  59.724 41.989 64.494 42.061 ;
     RECT  26.136 41.477 26.298 42.179 ;
     RECT  95.796 42.025 97.83 42.179 ;
     RECT  27.36 41.989 57.618 42.215 ;
     RECT  58.716 42.061 64.494 42.215 ;
     RECT  0.108 41.645 0.522 42.221 ;
     RECT  102.564 42.025 106.65 42.223 ;
     RECT  107.892 41.377 107.91 42.223 ;
     RECT  11.088 41.675 11.61 42.259 ;
     RECT  58.716 42.215 63.378 42.259 ;
     RECT  95.796 42.179 97.722 42.259 ;
     RECT  27.36 42.215 53.226 42.331 ;
     RECT  54.072 42.215 57.618 42.331 ;
     RECT  58.464 42.259 63.378 42.331 ;
     RECT  64.404 42.215 64.494 42.331 ;
     RECT  95.436 42.259 97.722 42.427 ;
     RECT  27.144 42.331 53.226 42.457 ;
     RECT  2.268 41.909 9.378 42.521 ;
     RECT  94.215 2.413 94.497 42.529 ;
     RECT  95.292 42.427 97.722 42.529 ;
     RECT  102.564 42.223 107.91 42.529 ;
     RECT  64.404 42.331 65.394 42.601 ;
     RECT  54.072 42.331 63.378 42.719 ;
     RECT  0.468 42.221 0.522 42.727 ;
     RECT  0.468 42.727 0.558 42.755 ;
     RECT  98.604 41.909 101.646 42.763 ;
     RECT  102.564 42.529 107.946 42.763 ;
     RECT  98.604 42.763 107.946 42.791 ;
     RECT  0.54 42.755 0.558 42.797 ;
     RECT  64.404 42.601 65.538 42.799 ;
     RECT  72.615 2.413 72.897 42.799 ;
     RECT  11.088 42.259 11.718 42.871 ;
     RECT  11.088 42.871 11.934 42.961 ;
     RECT  64.404 42.799 65.646 42.961 ;
     RECT  70.236 42.799 70.254 42.961 ;
     RECT  94.215 42.529 97.722 42.989 ;
     RECT  26.784 42.457 53.226 42.995 ;
     RECT  48.168 42.995 53.226 42.997 ;
     RECT  54.072 42.719 59.418 42.997 ;
     RECT  69.948 42.961 70.902 42.997 ;
     RECT  11.052 42.961 11.934 43.003 ;
     RECT  11.052 43.003 11.97 43.033 ;
     RECT  13.215 2.413 13.497 43.033 ;
     RECT  60.156 42.719 63.378 43.033 ;
     RECT  64.404 42.961 66.222 43.033 ;
     RECT  97.704 42.989 97.722 43.051 ;
     RECT  98.604 42.791 107.91 43.051 ;
     RECT  97.704 43.051 107.91 43.061 ;
     RECT  2.268 42.521 9.306 43.099 ;
     RECT  68.976 42.799 68.994 43.105 ;
     RECT  69.768 42.997 70.902 43.105 ;
     RECT  26.784 42.995 47.358 43.181 ;
     RECT  60.156 43.033 66.222 43.195 ;
     RECT  60.156 43.195 66.33 43.231 ;
     RECT  67.215 2.413 67.497 43.231 ;
     RECT  2.232 43.099 9.306 43.277 ;
     RECT  26.784 43.181 43.974 43.295 ;
     RECT  48.168 42.997 59.418 43.295 ;
     RECT  13.032 43.033 13.497 43.331 ;
     RECT  68.976 43.105 70.902 43.339 ;
     RECT  71.964 42.799 72.897 43.339 ;
     RECT  34.272 43.295 43.974 43.373 ;
     RECT  56.376 43.295 59.418 43.403 ;
     RECT  106.524 43.061 107.91 43.469 ;
     RECT  94.215 42.989 96.93 43.529 ;
     RECT  97.704 43.061 105.714 43.529 ;
     RECT  10.836 43.033 11.97 43.537 ;
     RECT  68.976 43.339 72.897 43.609 ;
     RECT  14.796 43.537 14.814 43.645 ;
     RECT  2.268 43.277 9.306 43.681 ;
     RECT  68.94 43.609 72.897 43.681 ;
     RECT  10.836 43.537 12.078 43.682 ;
     RECT  94.215 43.529 95.454 43.709 ;
     RECT  1.368 43.627 1.386 43.723 ;
     RECT  44.856 43.181 47.358 43.771 ;
     RECT  48.168 43.295 54.954 43.771 ;
     RECT  68.544 43.681 72.897 43.835 ;
     RECT  0.144 43.819 0.162 43.843 ;
     RECT  2.268 43.681 9.378 43.867 ;
     RECT  14.652 43.645 14.814 43.871 ;
     RECT  2.268 43.867 9.486 43.879 ;
     RECT  10.836 43.682 12.042 43.879 ;
     RECT  38.52 43.373 43.974 43.951 ;
     RECT  44.856 43.771 54.954 43.951 ;
     RECT  26.784 43.295 33.426 44.041 ;
     RECT  34.272 43.373 37.782 44.041 ;
     RECT  38.52 43.951 54.954 44.041 ;
     RECT  38.52 44.041 55.602 44.059 ;
     RECT  56.376 43.403 59.274 44.059 ;
     RECT  95.292 43.709 95.454 44.069 ;
     RECT  96.228 43.529 96.93 44.069 ;
     RECT  97.704 43.529 97.83 44.069 ;
     RECT  95.292 44.069 95.31 44.105 ;
     RECT  97.812 44.069 97.83 44.105 ;
     RECT  0.072 43.843 0.162 44.107 ;
     RECT  26.784 44.041 37.782 44.113 ;
     RECT  38.52 44.059 59.274 44.113 ;
     RECT  22.86 43.915 22.878 44.141 ;
     RECT  1.368 43.723 1.422 44.203 ;
     RECT  2.268 43.879 12.042 44.203 ;
     RECT  24.015 2.413 24.297 44.203 ;
     RECT  98.604 43.529 105.714 44.221 ;
     RECT  106.524 43.469 107.874 44.221 ;
     RECT  23.904 44.203 24.297 44.249 ;
     RECT  0.072 44.107 0.198 44.299 ;
     RECT  68.544 43.835 69.606 44.299 ;
     RECT  98.604 44.221 107.874 44.299 ;
     RECT  60.156 43.231 67.497 44.347 ;
     RECT  98.604 44.299 107.91 44.347 ;
     RECT  68.508 44.299 69.606 44.375 ;
     RECT  14.796 43.871 14.814 44.381 ;
     RECT  26.784 44.113 59.274 44.455 ;
     RECT  60.084 44.347 67.497 44.455 ;
     RECT  1.368 44.203 12.042 44.483 ;
     RECT  97.848 44.347 107.91 44.519 ;
     RECT  69.012 44.375 69.606 44.581 ;
     RECT  70.344 43.835 72.897 44.581 ;
     RECT  1.368 44.483 12.006 44.587 ;
     RECT  26.784 44.455 67.497 44.681 ;
     RECT  25.632 44.455 25.65 44.725 ;
     RECT  69.012 44.581 72.897 44.725 ;
     RECT  69.012 44.725 73.278 44.761 ;
     RECT  1.224 44.587 12.006 44.789 ;
     RECT  26.784 44.681 28.098 44.789 ;
     RECT  28.944 44.681 67.497 44.879 ;
     RECT  32.904 44.879 67.497 44.915 ;
     RECT  96.66 44.069 96.93 44.917 ;
     RECT  58.644 44.915 67.497 44.923 ;
     RECT  69.012 44.761 73.422 44.923 ;
     RECT  10.116 44.789 11.79 44.951 ;
     RECT  58.644 44.923 67.698 44.971 ;
     RECT  10.116 44.951 10.53 44.987 ;
     RECT  11.376 44.951 11.79 44.987 ;
     RECT  0.072 44.299 0.342 45.005 ;
     RECT  97.848 44.519 107.838 45.005 ;
     RECT  69.012 44.923 73.638 45.031 ;
     RECT  96.66 44.917 97.074 45.121 ;
     RECT  97.848 45.005 107.154 45.121 ;
     RECT  10.116 44.987 10.494 45.149 ;
     RECT  27.144 44.789 28.098 45.185 ;
     RECT  58.644 44.971 68.058 45.193 ;
     RECT  69.012 45.031 74.07 45.193 ;
     RECT  13.215 43.331 13.497 45.229 ;
     RECT  58.644 45.193 74.07 45.229 ;
     RECT  0.072 45.005 0.234 45.245 ;
     RECT  58.644 45.229 74.142 45.257 ;
     RECT  63.396 45.257 74.142 45.293 ;
     RECT  27.288 45.185 28.098 45.419 ;
     RECT  75.132 45.229 75.15 45.419 ;
     RECT  28.944 44.879 32.094 45.427 ;
     RECT  32.904 44.915 57.906 45.527 ;
     RECT  22.824 45.463 22.842 45.563 ;
     RECT  17.1 45.391 17.406 45.571 ;
     RECT  75.096 45.499 75.114 45.571 ;
     RECT  32.904 45.527 36.882 45.599 ;
     RECT  27.576 45.419 28.098 45.643 ;
     RECT  28.836 45.427 32.094 45.643 ;
     RECT  9.288 44.789 9.306 45.661 ;
     RECT  15.48 45.463 15.57 45.661 ;
     RECT  37.62 45.527 57.906 45.689 ;
     RECT  74.988 45.571 75.114 45.689 ;
     RECT  107.892 45.643 107.91 45.689 ;
     RECT  1.224 44.789 8.097 45.691 ;
     RECT  27.576 45.643 32.094 45.691 ;
     RECT  32.904 45.599 36.738 45.691 ;
     RECT  12.636 45.229 13.59 45.697 ;
     RECT  17.064 45.571 17.406 45.697 ;
     RECT  42.948 45.689 57.906 45.697 ;
     RECT  58.644 45.257 62.478 45.697 ;
     RECT  42.948 45.697 62.478 45.725 ;
     RECT  74.988 45.689 75.006 45.725 ;
     RECT  12.564 45.697 13.59 45.769 ;
     RECT  14.328 45.661 15.57 45.769 ;
     RECT  94.215 43.709 94.497 45.769 ;
     RECT  96.66 45.121 107.154 45.787 ;
     RECT  96.552 45.787 107.154 45.805 ;
     RECT  78.015 2.413 78.297 45.832 ;
     RECT  88.815 2.413 89.097 45.832 ;
     RECT  9.108 45.661 9.306 45.833 ;
     RECT  12.564 45.769 15.57 45.835 ;
     RECT  11.376 44.987 11.61 45.841 ;
     RECT  12.564 45.835 15.642 45.841 ;
     RECT  18.615 40.925 18.897 45.841 ;
     RECT  25.2 44.725 25.65 45.841 ;
     RECT  27.576 45.691 36.738 45.869 ;
     RECT  77.904 45.832 78.297 45.869 ;
     RECT  88.704 45.832 89.097 45.869 ;
     RECT  94.215 45.769 94.662 45.869 ;
     RECT  11.376 45.841 15.642 45.959 ;
     RECT  28.656 45.869 36.738 45.959 ;
     RECT  10.116 45.149 10.314 45.967 ;
     RECT  16.992 45.697 17.406 45.967 ;
     RECT  28.656 45.959 32.094 45.995 ;
     RECT  43.2 45.725 62.478 45.995 ;
     RECT  63.396 45.293 74.106 46.003 ;
     RECT  96.552 45.805 107.226 46.013 ;
     RECT  11.592 45.959 15.642 46.067 ;
     RECT  33.012 45.959 36.738 46.067 ;
     RECT  18.615 45.841 19.062 46.075 ;
     RECT  53.784 45.995 62.478 46.075 ;
     RECT  63.288 46.003 74.106 46.075 ;
     RECT  30.564 45.995 32.094 46.103 ;
     RECT  43.2 45.995 53.046 46.109 ;
     RECT  53.784 46.075 74.106 46.111 ;
     RECT  103.788 46.013 107.226 46.157 ;
     RECT  1.224 45.691 8.154 46.201 ;
     RECT  36.72 46.067 36.738 46.229 ;
     RECT  16.992 45.967 17.442 46.237 ;
     RECT  106.56 46.157 107.226 46.265 ;
     RECT  1.224 46.201 8.19 46.267 ;
     RECT  11.988 46.067 15.642 46.273 ;
     RECT  11.988 46.273 15.894 46.309 ;
     RECT  11.988 46.309 16.074 46.345 ;
     RECT  16.992 46.237 17.622 46.345 ;
     RECT  26.856 46.381 26.874 46.535 ;
     RECT  11.988 46.345 17.838 46.615 ;
     RECT  18.615 46.075 19.53 46.615 ;
     RECT  43.2 46.109 52.902 46.615 ;
     RECT  1.224 46.267 8.838 46.643 ;
     RECT  1.224 46.643 8.154 46.679 ;
     RECT  106.596 46.265 107.226 46.733 ;
     RECT  96.552 46.013 103.05 46.741 ;
     RECT  103.788 46.157 105.606 46.741 ;
     RECT  53.784 46.111 74.142 46.747 ;
     RECT  78.015 45.869 78.297 46.747 ;
     RECT  28.656 45.995 29.697 46.777 ;
     RECT  76.896 46.507 76.914 46.777 ;
     RECT  53.712 46.747 74.142 46.795 ;
     RECT  33.012 46.067 35.946 46.813 ;
     RECT  37.62 45.689 42.21 46.813 ;
     RECT  76.572 46.777 76.914 46.829 ;
     RECT  9.648 45.967 10.314 46.849 ;
     RECT  30.96 46.103 32.094 46.849 ;
     RECT  53.712 46.795 74.178 46.849 ;
     RECT  25.02 45.841 25.65 46.877 ;
     RECT  78.015 46.747 78.642 46.877 ;
     RECT  36.972 46.813 42.21 46.885 ;
     RECT  42.948 46.615 52.902 46.885 ;
     RECT  0.072 45.245 0.198 46.913 ;
     RECT  107.892 46.795 107.91 46.913 ;
     RECT  30.852 46.849 32.094 46.921 ;
     RECT  36.972 46.885 52.902 46.921 ;
     RECT  53.712 46.849 74.394 46.921 ;
     RECT  106.596 46.733 107.154 46.987 ;
     RECT  28.476 46.777 29.697 47.083 ;
     RECT  11.988 46.615 19.53 47.111 ;
     RECT  30.78 46.921 32.094 47.119 ;
     RECT  33.012 46.813 36.234 47.119 ;
     RECT  36.972 46.921 75.222 47.119 ;
     RECT  26.532 47.047 26.55 47.165 ;
     RECT  96.552 46.741 105.606 47.191 ;
     RECT  1.224 46.679 8.097 47.219 ;
     RECT  30.78 47.119 75.222 47.219 ;
     RECT  106.56 46.987 107.154 47.275 ;
     RECT  9.144 46.849 10.314 47.309 ;
     RECT  30.78 47.219 74.574 47.353 ;
     RECT  77.04 47.323 77.058 47.417 ;
     RECT  28.224 47.083 29.697 47.425 ;
     RECT  30.744 47.353 74.574 47.425 ;
     RECT  25.632 46.877 25.65 47.461 ;
     RECT  78.015 46.877 78.297 47.551 ;
     RECT  88.815 45.869 89.097 47.551 ;
     RECT  106.524 47.275 107.154 47.551 ;
     RECT  96.552 47.191 105.714 47.563 ;
     RECT  106.524 47.551 107.19 47.563 ;
     RECT  28.224 47.425 74.574 47.615 ;
     RECT  21.312 47.011 21.33 47.659 ;
     RECT  1.836 47.219 8.097 47.687 ;
     RECT  96.552 47.563 107.19 47.755 ;
     RECT  95.94 47.755 107.19 47.789 ;
     RECT  28.224 47.615 39.402 47.803 ;
     RECT  28.08 47.803 39.402 47.821 ;
     RECT  75.348 47.425 75.402 47.821 ;
     RECT  9.648 47.309 10.314 47.849 ;
     RECT  40.176 47.615 74.574 47.849 ;
     RECT  24.015 44.249 24.297 47.851 ;
     RECT  25.632 47.461 26.19 47.851 ;
     RECT  27.936 47.821 39.402 47.857 ;
     RECT  1.836 47.687 6.966 47.885 ;
     RECT  27.36 47.857 39.402 47.885 ;
     RECT  75.348 47.821 75.438 47.885 ;
     RECT  25.452 47.851 26.19 47.893 ;
     RECT  12.564 47.111 19.53 47.965 ;
     RECT  12.564 47.965 19.854 48.001 ;
     RECT  21.06 47.659 21.33 48.001 ;
     RECT  2.304 47.885 6.966 48.029 ;
     RECT  22.176 47.155 22.194 48.091 ;
     RECT  23.472 47.851 24.297 48.091 ;
     RECT  77.904 47.551 78.297 48.128 ;
     RECT  88.704 47.551 89.097 48.128 ;
     RECT  94.215 45.869 94.497 48.163 ;
     RECT  25.452 47.893 26.262 48.187 ;
     RECT  27.36 47.885 39.33 48.187 ;
     RECT  22.176 48.091 24.297 48.199 ;
     RECT  25.308 48.187 39.33 48.199 ;
     RECT  40.176 47.849 74.25 48.263 ;
     RECT  95.94 47.789 106.686 48.271 ;
     RECT  0.108 46.913 0.198 48.299 ;
     RECT  75.384 47.885 75.438 48.299 ;
     RECT  40.176 48.263 69.282 48.425 ;
     RECT  63.468 48.425 69.282 48.461 ;
     RECT  63.468 48.461 69.21 48.497 ;
     RECT  95.868 48.271 106.686 48.557 ;
     RECT  12.564 48.001 21.33 48.569 ;
     RECT  13.068 48.569 21.33 48.631 ;
     RECT  22.176 48.199 39.33 48.631 ;
     RECT  83.415 2.413 83.697 48.667 ;
     RECT  13.068 48.631 39.33 48.695 ;
     RECT  0.108 48.299 0.126 48.767 ;
     RECT  94.215 48.163 94.662 48.775 ;
     RECT  6.948 48.029 6.966 48.811 ;
     RECT  7.815 47.687 8.097 48.811 ;
     RECT  70.2 48.263 74.25 48.811 ;
     RECT  93.852 48.775 95.13 48.901 ;
     RECT  95.868 48.557 105.498 48.901 ;
     RECT  86.616 48.811 86.634 48.929 ;
     RECT  83.415 48.667 83.79 48.937 ;
     RECT  70.2 48.811 74.826 48.965 ;
     RECT  93.852 48.901 105.498 48.989 ;
     RECT  2.304 48.029 6.102 49.009 ;
     RECT  6.948 48.811 8.097 49.009 ;
     RECT  13.215 48.695 39.33 49.009 ;
     RECT  40.176 48.425 62.73 49.009 ;
     RECT  83.376 48.937 83.79 49.009 ;
     RECT  13.215 49.009 62.73 49.037 ;
     RECT  70.2 48.965 74.754 49.073 ;
     RECT  83.016 49.009 83.79 49.081 ;
     RECT  92.916 49.009 92.934 49.081 ;
     RECT  93.852 48.989 95.166 49.081 ;
     RECT  106.524 48.557 106.686 49.099 ;
     RECT  9.648 47.849 9.666 49.147 ;
     RECT  22.86 49.037 62.73 49.171 ;
     RECT  63.468 48.497 68.958 49.171 ;
     RECT  92.484 49.081 92.934 49.171 ;
     RECT  13.215 49.037 21.87 49.199 ;
     RECT  74.628 49.073 74.754 49.199 ;
     RECT  82.98 49.081 83.79 49.199 ;
     RECT  106.524 49.099 107.154 49.199 ;
     RECT  82.98 49.199 83.754 49.207 ;
     RECT  82.908 49.207 83.754 49.243 ;
     RECT  8.964 49.147 10.242 49.271 ;
     RECT  74.628 49.199 74.682 49.271 ;
     RECT  9.252 49.271 10.242 49.279 ;
     RECT  92.484 49.171 92.97 49.279 ;
     RECT  93.708 49.081 95.166 49.279 ;
     RECT  2.304 49.009 8.097 49.291 ;
     RECT  14.724 49.199 21.87 49.307 ;
     RECT  9.252 49.279 10.782 49.315 ;
     RECT  14.796 49.307 21.87 49.343 ;
     RECT  22.86 49.171 68.958 49.351 ;
     RECT  13.215 49.199 13.842 49.379 ;
     RECT  82.656 49.243 83.754 49.379 ;
     RECT  92.196 49.279 95.166 49.441 ;
     RECT  9.252 49.315 10.854 49.469 ;
     RECT  14.832 49.343 21.87 49.469 ;
     RECT  1.728 49.291 8.442 49.475 ;
     RECT  22.86 49.351 69.138 49.477 ;
     RECT  70.2 49.073 73.674 49.477 ;
     RECT  95.94 48.989 105.498 49.477 ;
     RECT  106.524 49.199 106.686 49.477 ;
     RECT  13.215 49.379 13.698 49.505 ;
     RECT  82.908 49.379 83.697 49.505 ;
     RECT  22.86 49.477 73.674 49.517 ;
     RECT  81.072 49.477 81.09 49.517 ;
     RECT  22.86 49.517 68.814 49.541 ;
     RECT  9.432 49.469 10.242 49.577 ;
     RECT  14.832 49.469 19.386 49.577 ;
     RECT  20.34 49.469 21.474 49.649 ;
     RECT  1.728 49.475 8.097 49.739 ;
     RECT  22.86 49.541 68.67 49.775 ;
     RECT  15.12 49.577 19.386 49.847 ;
     RECT  22.86 49.775 68.31 49.847 ;
     RECT  22.86 49.847 51.297 49.855 ;
     RECT  95.94 49.477 106.686 49.963 ;
     RECT  74.664 49.271 74.682 49.981 ;
     RECT  92.124 49.441 95.166 49.981 ;
     RECT  52.092 49.847 68.31 49.997 ;
     RECT  1.728 49.739 4.842 50.009 ;
     RECT  6.552 49.739 8.097 50.009 ;
     RECT  20.484 49.649 21.474 50.009 ;
     RECT  15.408 49.847 19.386 50.045 ;
     RECT  20.484 50.009 21.294 50.045 ;
     RECT  79.524 49.003 79.542 50.045 ;
     RECT  91.944 49.981 95.166 50.045 ;
     RECT  95.94 49.963 107.118 50.059 ;
     RECT  92.412 50.045 95.166 50.093 ;
     RECT  15.444 50.045 19.386 50.117 ;
     RECT  21.204 50.045 21.222 50.117 ;
     RECT  69.768 49.517 73.674 50.125 ;
     RECT  74.664 49.981 74.754 50.125 ;
     RECT  92.844 50.093 95.166 50.203 ;
     RECT  95.94 50.059 107.154 50.203 ;
     RECT  1.728 50.009 4.806 50.279 ;
     RECT  6.552 50.009 6.966 50.279 ;
     RECT  92.844 50.203 107.154 50.347 ;
     RECT  107.892 49.675 107.91 50.347 ;
     RECT  1.728 50.279 4.59 50.459 ;
     RECT  22.248 49.855 51.297 50.459 ;
     RECT  69.768 50.125 74.754 50.459 ;
     RECT  2.304 50.459 4.59 50.549 ;
     RECT  9.648 49.577 10.242 50.549 ;
     RECT  15.444 50.117 19.206 50.549 ;
     RECT  22.572 50.459 51.297 50.549 ;
     RECT  69.768 50.459 74.142 50.557 ;
     RECT  15.444 50.549 17.406 50.669 ;
     RECT  18.144 50.549 19.206 50.669 ;
     RECT  15.516 50.669 15.822 50.693 ;
     RECT  16.632 50.669 17.406 50.693 ;
     RECT  18.18 50.669 19.206 50.693 ;
     RECT  15.804 50.693 15.822 50.729 ;
     RECT  0.036 50.701 0.054 50.746 ;
     RECT  0.036 50.746 0.126 50.774 ;
     RECT  5.688 49.739 5.706 50.819 ;
     RECT  52.092 49.997 68.274 50.819 ;
     RECT  52.848 50.819 68.274 50.827 ;
     RECT  69.516 50.557 74.142 50.827 ;
     RECT  16.632 50.693 17.37 50.855 ;
     RECT  52.092 50.819 52.11 50.855 ;
     RECT  20.016 50.791 20.142 50.875 ;
     RECT  18.288 50.693 19.206 50.891 ;
     RECT  6.948 50.279 6.966 50.899 ;
     RECT  7.815 50.009 8.097 50.899 ;
     RECT  92.844 50.347 107.91 50.899 ;
     RECT  92.772 50.899 107.91 50.927 ;
     RECT  18.288 50.891 18.954 50.963 ;
     RECT  20.016 50.875 20.502 50.963 ;
     RECT  18.324 50.963 18.954 50.999 ;
     RECT  18.36 50.999 18.954 51.089 ;
     RECT  20.016 50.963 20.178 51.089 ;
     RECT  22.572 50.549 49.59 51.089 ;
     RECT  97.704 50.927 107.91 51.089 ;
     RECT  90.72 50.923 90.738 51.101 ;
     RECT  20.016 51.089 20.07 51.125 ;
     RECT  22.572 51.089 24.426 51.125 ;
     RECT  25.308 51.089 49.59 51.149 ;
     RECT  20.052 51.125 20.07 51.197 ;
     RECT  22.932 51.125 24.426 51.197 ;
     RECT  92.772 50.927 96.966 51.197 ;
     RECT  2.304 50.549 4.266 51.233 ;
     RECT  23.004 51.197 24.426 51.233 ;
     RECT  0.108 50.774 0.126 51.241 ;
     RECT  92.988 51.197 96.966 51.245 ;
     RECT  18.615 51.089 18.954 51.269 ;
     RECT  25.308 51.149 28.026 51.269 ;
     RECT  107.892 51.089 107.91 51.269 ;
     RECT  93.42 51.245 96.966 51.293 ;
     RECT  97.74 51.089 107.154 51.341 ;
     RECT  23.112 51.233 24.426 51.359 ;
     RECT  25.308 51.269 27.882 51.359 ;
     RECT  28.836 51.149 49.59 51.359 ;
     RECT  52.848 50.827 74.142 51.359 ;
     RECT  28.836 51.359 49.446 51.395 ;
     RECT  23.148 51.359 24.426 51.467 ;
     RECT  23.148 51.467 23.166 51.503 ;
     RECT  25.308 51.359 25.326 51.503 ;
     RECT  26.136 51.359 27.882 51.503 ;
     RECT  53.208 51.359 74.142 51.503 ;
     RECT  94.104 51.293 95.526 51.503 ;
     RECT  55.368 51.503 74.142 51.511 ;
     RECT  23.976 51.467 24.426 51.629 ;
     RECT  55.368 51.511 74.358 51.637 ;
     RECT  94.215 51.503 95.526 51.665 ;
     RECT  26.244 51.503 27.882 51.701 ;
     RECT  0.108 51.241 0.162 51.709 ;
     RECT  1.152 51.511 1.17 51.709 ;
     RECT  28.836 51.395 40.914 51.737 ;
     RECT  26.532 51.701 26.55 51.773 ;
     RECT  27.504 51.701 27.594 51.773 ;
     RECT  30.78 51.737 40.914 51.773 ;
     RECT  55.368 51.637 74.394 51.773 ;
     RECT  27.504 51.773 27.522 51.809 ;
     RECT  53.208 51.503 54.486 51.809 ;
     RECT  31.14 51.773 40.914 51.821 ;
     RECT  55.368 51.773 57.834 51.821 ;
     RECT  58.716 51.773 74.394 51.821 ;
     RECT  10.836 51.739 10.854 51.869 ;
     RECT  78.015 48.128 78.297 51.871 ;
     RECT  88.815 48.128 89.097 51.871 ;
     RECT  58.824 51.821 74.394 51.899 ;
     RECT  96.336 51.293 96.966 51.899 ;
     RECT  77.904 51.871 78.297 51.917 ;
     RECT  88.704 51.871 89.097 51.917 ;
     RECT  31.14 51.821 37.53 51.935 ;
     RECT  9.648 50.549 9.666 51.979 ;
     RECT  2.34 51.233 4.266 52.051 ;
     RECT  41.652 51.395 49.446 52.079 ;
     RECT  31.32 51.935 37.53 52.169 ;
     RECT  97.74 51.341 105.714 52.171 ;
     RECT  106.56 51.341 107.154 52.171 ;
     RECT  31.32 52.169 34.038 52.205 ;
     RECT  38.304 51.821 40.914 52.205 ;
     RECT  31.356 52.205 32.418 52.211 ;
     RECT  2.34 52.051 5.058 52.213 ;
     RECT  96.696 51.899 96.966 52.213 ;
     RECT  97.74 52.171 107.154 52.213 ;
     RECT  33.444 52.205 34.038 52.241 ;
     RECT  28.836 51.737 29.697 52.249 ;
     RECT  96.696 52.213 107.154 52.277 ;
     RECT  33.444 52.241 33.462 52.313 ;
     RECT  2.34 52.213 5.13 52.321 ;
     RECT  9.072 51.979 9.666 52.321 ;
     RECT  38.772 52.205 40.914 52.321 ;
     RECT  41.652 52.079 48.798 52.321 ;
     RECT  53.568 51.809 54.486 52.321 ;
     RECT  55.368 51.821 57.618 52.321 ;
     RECT  6.948 50.899 8.097 52.411 ;
     RECT  94.215 51.665 94.698 52.411 ;
     RECT  31.356 52.211 31.59 52.439 ;
     RECT  32.4 52.211 32.418 52.439 ;
     RECT  95.868 52.177 95.922 52.439 ;
     RECT  96.696 52.277 105.642 52.439 ;
     RECT  34.815 52.169 37.53 52.475 ;
     RECT  95.868 52.439 95.886 52.493 ;
     RECT  17.28 50.855 17.298 52.511 ;
     RECT  2.304 52.321 5.274 52.591 ;
     RECT  36.936 52.475 37.53 52.591 ;
     RECT  53.568 52.321 57.618 52.591 ;
     RECT  58.824 51.899 74.07 52.681 ;
     RECT  34.815 52.475 36.162 52.709 ;
     RECT  52.92 52.591 57.618 52.709 ;
     RECT  2.268 52.591 5.418 52.717 ;
     RECT  50.436 50.549 51.297 52.745 ;
     RECT  106.524 52.277 107.154 52.745 ;
     RECT  34.815 52.709 35.838 52.781 ;
     RECT  53.568 52.709 57.618 52.781 ;
     RECT  106.524 52.745 107.118 52.781 ;
     RECT  54.468 52.781 57.618 52.789 ;
     RECT  50.544 52.745 51.297 52.817 ;
     RECT  2.268 52.717 5.598 52.825 ;
     RECT  6.804 52.411 8.097 52.825 ;
     RECT  58.824 52.681 74.214 52.825 ;
     RECT  22.824 52.753 22.842 52.853 ;
     RECT  53.568 52.781 53.586 52.853 ;
     RECT  25.488 52.825 25.506 52.861 ;
     RECT  18.615 51.269 18.897 52.951 ;
     RECT  38.772 52.321 48.798 52.951 ;
     RECT  58.788 52.825 74.214 52.951 ;
     RECT  36.936 52.591 37.638 52.979 ;
     RECT  38.772 52.951 49.086 52.979 ;
     RECT  96.696 52.439 97.83 52.979 ;
     RECT  18.576 52.951 18.897 52.981 ;
     RECT  2.268 52.825 8.097 52.987 ;
     RECT  18.36 52.981 18.897 52.987 ;
     RECT  96.696 52.979 97.074 53.015 ;
     RECT  18.36 52.987 19.602 53.023 ;
     RECT  20.52 52.951 20.538 53.023 ;
     RECT  27 52.753 27.018 53.023 ;
     RECT  28.512 52.249 29.697 53.023 ;
     RECT  33.264 52.951 33.282 53.023 ;
     RECT  34.815 52.781 35.694 53.023 ;
     RECT  38.772 52.979 47.61 53.035 ;
     RECT  107.892 52.075 107.91 53.035 ;
     RECT  54.468 52.789 57.654 53.059 ;
     RECT  15.984 52.951 16.002 53.095 ;
     RECT  23.976 51.629 24.297 53.095 ;
     RECT  26.82 53.023 27.018 53.095 ;
     RECT  28.44 53.023 29.697 53.095 ;
     RECT  38.412 53.035 47.61 53.095 ;
     RECT  9.072 52.321 9.738 53.131 ;
     RECT  10.764 53.095 10.782 53.131 ;
     RECT  15.84 53.095 16.362 53.131 ;
     RECT  17.424 53.023 19.602 53.131 ;
     RECT  25.488 52.861 25.686 53.131 ;
     RECT  26.748 53.095 27.018 53.131 ;
     RECT  54.468 53.059 57.762 53.131 ;
     RECT  58.788 52.951 74.286 53.131 ;
     RECT  50.58 52.817 51.297 53.159 ;
     RECT  107.856 53.035 107.91 53.159 ;
     RECT  15.84 53.131 16.434 53.221 ;
     RECT  17.424 53.131 19.638 53.221 ;
     RECT  22.104 53.131 22.77 53.221 ;
     RECT  23.76 53.095 24.297 53.221 ;
     RECT  48.348 52.979 49.086 53.221 ;
     RECT  54.468 53.131 57.798 53.221 ;
     RECT  58.788 53.131 74.358 53.221 ;
     RECT  48.348 53.221 49.338 53.227 ;
     RECT  98.604 52.439 105.642 53.227 ;
     RECT  106.524 52.781 106.578 53.227 ;
     RECT  17.424 53.221 19.674 53.248 ;
     RECT  10.764 53.131 10.818 53.249 ;
     RECT  50.976 53.159 51.297 53.249 ;
     RECT  2.268 52.987 8.334 53.257 ;
     RECT  9.072 53.131 9.846 53.257 ;
     RECT  15.372 53.221 16.434 53.275 ;
     RECT  17.388 53.248 19.674 53.275 ;
     RECT  25.488 53.131 25.722 53.275 ;
     RECT  17.388 53.275 19.746 53.293 ;
     RECT  10.8 53.249 10.818 53.321 ;
     RECT  98.604 53.227 106.578 53.321 ;
     RECT  21.996 53.221 22.77 53.329 ;
     RECT  23.76 53.221 24.426 53.329 ;
     RECT  25.488 53.275 25.794 53.329 ;
     RECT  30.78 53.131 30.798 53.357 ;
     RECT  94.215 52.411 95.13 53.357 ;
     RECT  17.28 53.293 19.746 53.365 ;
     RECT  20.52 53.023 20.754 53.365 ;
     RECT  14.832 53.275 16.434 53.401 ;
     RECT  17.28 53.365 20.754 53.401 ;
     RECT  23.688 53.329 24.426 53.401 ;
     RECT  25.344 53.329 25.794 53.401 ;
     RECT  26.604 53.131 27.018 53.401 ;
     RECT  32.688 53.023 33.282 53.401 ;
     RECT  38.232 53.095 47.61 53.429 ;
     RECT  54.468 53.221 74.358 53.429 ;
     RECT  21.78 53.329 22.77 53.515 ;
     RECT  34.524 53.023 35.694 53.515 ;
     RECT  97.848 53.401 97.866 53.515 ;
     RECT  98.604 53.321 105.678 53.515 ;
     RECT  75.132 53.401 75.222 53.519 ;
     RECT  23.652 53.401 25.794 53.527 ;
     RECT  36.936 52.979 37.386 53.527 ;
     RECT  106.524 53.321 106.578 53.527 ;
     RECT  26.604 53.401 27.558 53.555 ;
     RECT  75.132 53.519 75.15 53.555 ;
     RECT  32.688 53.401 33.57 53.563 ;
     RECT  34.524 53.515 35.802 53.563 ;
     RECT  36.792 53.527 37.386 53.563 ;
     RECT  38.232 53.429 43.974 53.591 ;
     RECT  106.524 53.527 106.65 53.599 ;
     RECT  107.856 53.159 107.874 53.599 ;
     RECT  97.848 53.515 105.678 53.645 ;
     RECT  21.744 53.515 22.77 53.671 ;
     RECT  23.616 53.527 25.794 53.671 ;
     RECT  28.368 53.095 29.697 53.671 ;
     RECT  28.296 53.671 29.697 53.707 ;
     RECT  106.524 53.599 107.874 53.741 ;
     RECT  32.688 53.563 33.642 53.761 ;
     RECT  34.524 53.563 37.386 53.761 ;
     RECT  48.348 53.227 49.446 53.761 ;
     RECT  55.8 53.429 74.358 53.761 ;
     RECT  55.8 53.761 74.574 53.789 ;
     RECT  21.744 53.671 25.794 53.797 ;
     RECT  31.572 52.439 31.59 53.797 ;
     RECT  14.832 53.401 20.826 53.825 ;
     RECT  27.792 53.707 29.697 53.825 ;
     RECT  31.572 53.797 31.698 53.833 ;
     RECT  38.232 53.591 42.138 53.833 ;
     RECT  44.712 53.429 47.61 53.869 ;
     RECT  48.348 53.761 49.554 53.869 ;
     RECT  55.008 53.429 55.026 53.897 ;
     RECT  107.82 53.741 107.874 53.899 ;
     RECT  31.428 53.833 31.698 53.905 ;
     RECT  32.688 53.761 37.386 53.905 ;
     RECT  44.712 53.869 49.554 53.933 ;
     RECT  0.108 51.709 1.17 54.029 ;
     RECT  31.428 53.905 37.386 54.031 ;
     RECT  38.124 53.833 42.138 54.031 ;
     RECT  55.8 53.789 71.874 54.059 ;
     RECT  14.832 53.825 17.838 54.067 ;
     RECT  96.912 53.015 97.074 54.067 ;
     RECT  97.848 53.645 105.606 54.067 ;
     RECT  21.744 53.797 25.866 54.103 ;
     RECT  26.604 53.555 27.018 54.103 ;
     RECT  31.428 54.031 42.138 54.103 ;
     RECT  14.508 54.067 17.838 54.125 ;
     RECT  72.615 53.789 74.574 54.131 ;
     RECT  18.576 53.825 20.826 54.139 ;
     RECT  21.744 54.103 27.018 54.139 ;
     RECT  96.912 54.067 105.606 54.167 ;
     RECT  59.436 54.059 71.874 54.203 ;
     RECT  28.152 53.825 29.697 54.211 ;
     RECT  0.108 54.029 0.558 54.221 ;
     RECT  2.268 53.257 9.846 54.283 ;
     RECT  13.215 49.505 13.497 54.283 ;
     RECT  28.152 54.211 30.402 54.301 ;
     RECT  31.356 54.103 42.138 54.301 ;
     RECT  13.215 54.283 13.59 54.329 ;
     RECT  72.615 54.131 73.71 54.329 ;
     RECT  28.152 54.301 42.138 54.331 ;
     RECT  42.912 53.591 43.974 54.331 ;
     RECT  28.152 54.331 43.974 54.337 ;
     RECT  44.712 53.933 49.518 54.337 ;
     RECT  55.8 54.059 58.518 54.365 ;
     RECT  59.436 54.203 60.642 54.365 ;
     RECT  56.415 54.365 57.726 54.401 ;
     RECT  72.615 54.329 73.638 54.401 ;
     RECT  0.108 54.221 0.522 54.413 ;
     RECT  106.524 53.741 106.65 54.475 ;
     RECT  107.82 53.899 107.91 54.475 ;
     RECT  2.268 54.283 10.242 54.481 ;
     RECT  74.664 54.379 74.682 54.509 ;
     RECT  86.652 54.379 86.67 54.509 ;
     RECT  28.152 54.337 49.518 54.571 ;
     RECT  58.5 54.365 58.518 54.599 ;
     RECT  14.832 54.125 17.838 54.607 ;
     RECT  18.576 54.139 27.018 54.607 ;
     RECT  2.268 54.481 10.854 54.635 ;
     RECT  27.972 54.571 49.518 54.643 ;
     RECT  96.912 54.167 97.146 54.653 ;
     RECT  56.415 54.401 57.654 54.671 ;
     RECT  14.832 54.607 27.018 54.679 ;
     RECT  27.864 54.643 49.518 54.679 ;
     RECT  0.108 54.413 0.45 54.701 ;
     RECT  57.636 54.671 57.654 54.707 ;
     RECT  106.524 54.475 107.91 54.715 ;
     RECT  59.652 54.365 60.642 54.743 ;
     RECT  61.452 54.203 71.874 54.749 ;
     RECT  14.832 54.679 49.518 54.751 ;
     RECT  0.108 54.701 0.126 54.797 ;
     RECT  59.904 54.743 60.642 54.869 ;
     RECT  97.128 54.653 97.146 54.869 ;
     RECT  14.832 54.751 49.626 54.905 ;
     RECT  106.488 54.715 107.91 54.905 ;
     RECT  97.92 54.167 105.606 54.907 ;
     RECT  60.192 54.869 60.642 54.949 ;
     RECT  61.452 54.749 70.506 54.949 ;
     RECT  47.412 54.905 49.626 55.013 ;
     RECT  71.316 54.749 71.874 55.021 ;
     RECT  72.615 54.401 73.566 55.021 ;
     RECT  97.92 54.907 105.642 55.021 ;
     RECT  2.304 54.635 10.854 55.111 ;
     RECT  71.316 55.021 73.566 55.139 ;
     RECT  71.316 55.139 73.422 55.175 ;
     RECT  97.164 55.021 105.714 55.175 ;
     RECT  98.388 55.175 105.714 55.181 ;
     RECT  98.388 55.181 98.73 55.211 ;
     RECT  14.832 54.905 46.638 55.247 ;
     RECT  60.192 54.949 70.506 55.247 ;
     RECT  71.316 55.175 71.334 55.247 ;
     RECT  98.388 55.211 98.658 55.247 ;
     RECT  2.304 55.111 10.926 55.283 ;
     RECT  60.984 55.247 70.506 55.283 ;
     RECT  96.084 53.851 96.102 55.291 ;
     RECT  60.192 55.247 60.21 55.325 ;
     RECT  96.084 55.291 96.21 55.381 ;
     RECT  96.084 55.381 96.39 55.409 ;
     RECT  99.468 55.181 105.714 55.409 ;
     RECT  14.4 55.417 14.418 55.469 ;
     RECT  2.304 55.283 10.854 55.517 ;
     RECT  106.524 54.905 107.91 55.517 ;
     RECT  96.192 55.409 96.39 55.553 ;
     RECT  97.164 55.175 97.47 55.565 ;
     RECT  47.412 55.013 49.302 55.589 ;
     RECT  15.336 55.247 46.638 55.651 ;
     RECT  47.412 55.589 48.87 55.651 ;
     RECT  15.336 55.651 48.87 55.679 ;
     RECT  61.308 55.283 70.506 55.679 ;
     RECT  95.292 55.381 95.31 55.679 ;
     RECT  15.336 55.679 48.438 55.715 ;
     RECT  10.836 55.517 10.854 55.787 ;
     RECT  61.308 55.679 69.57 55.853 ;
     RECT  96.372 55.553 96.39 55.853 ;
     RECT  61.308 55.853 68.202 55.859 ;
     RECT  15.444 55.715 48.438 55.949 ;
     RECT  98.388 55.247 98.622 55.949 ;
     RECT  61.596 55.859 68.202 55.985 ;
     RECT  0.54 55.915 0.558 56.011 ;
     RECT  97.452 55.565 97.47 56.029 ;
     RECT  98.46 55.949 98.622 56.029 ;
     RECT  0.504 56.011 0.558 56.107 ;
     RECT  99.54 55.409 105.714 56.129 ;
     RECT  99.615 56.129 105.714 56.203 ;
     RECT  106.524 55.517 107.154 56.203 ;
     RECT  61.74 55.985 68.202 56.327 ;
     RECT  2.304 55.517 9.918 56.347 ;
     RECT  2.304 56.347 10.026 56.399 ;
     RECT  36.54 55.949 48.438 56.399 ;
     RECT  15.444 55.949 35.802 56.461 ;
     RECT  36.54 56.399 48.33 56.525 ;
     RECT  14.904 56.461 35.802 56.533 ;
     RECT  49.248 56.461 49.266 56.569 ;
     RECT  95.616 56.497 95.634 56.569 ;
     RECT  13.215 54.329 13.497 56.632 ;
     RECT  56.415 54.671 56.697 56.632 ;
     RECT  78.015 51.917 78.297 56.632 ;
     RECT  88.815 51.917 89.097 56.632 ;
     RECT  97.452 56.029 97.614 56.641 ;
     RECT  98.46 56.029 98.694 56.669 ;
     RECT  10.836 56.533 10.854 56.731 ;
     RECT  95.616 56.569 95.778 56.731 ;
     RECT  95.58 56.731 95.778 56.759 ;
     RECT  68.976 55.853 68.994 56.765 ;
     RECT  49.248 56.569 49.446 56.795 ;
     RECT  61.815 56.327 68.202 56.831 ;
     RECT  95.58 56.759 95.706 56.831 ;
     RECT  10.8 56.731 10.854 56.861 ;
     RECT  95.616 56.831 95.706 56.861 ;
     RECT  94.215 53.357 94.497 56.875 ;
     RECT  49.428 56.795 49.446 56.903 ;
     RECT  61.815 56.831 68.166 56.903 ;
     RECT  97.452 56.641 97.686 56.971 ;
     RECT  14.832 56.533 35.802 57.001 ;
     RECT  36.54 56.525 48.258 57.001 ;
     RECT  96.912 56.971 97.686 57.001 ;
     RECT  94.215 56.875 94.77 57.005 ;
     RECT  95.616 56.861 95.634 57.005 ;
     RECT  98.604 56.669 98.694 57.019 ;
     RECT  10.836 56.861 10.854 57.037 ;
     RECT  13.104 56.632 13.497 57.037 ;
     RECT  61.815 56.903 67.497 57.053 ;
     RECT  14.832 57.001 48.258 57.065 ;
     RECT  64.116 57.053 67.497 57.065 ;
     RECT  13.032 57.037 13.698 57.073 ;
     RECT  14.832 57.065 47.07 57.073 ;
     RECT  99.615 56.203 107.154 57.073 ;
     RECT  107.892 55.517 107.91 57.073 ;
     RECT  98.604 57.019 98.766 57.109 ;
     RECT  99.615 57.073 107.91 57.109 ;
     RECT  2.304 56.399 9.954 57.137 ;
     RECT  13.032 57.073 47.07 57.137 ;
     RECT  47.844 57.065 48.258 57.137 ;
     RECT  54.72 56.569 54.738 57.173 ;
     RECT  74.664 56.569 74.682 57.173 ;
     RECT  86.652 56.569 86.67 57.173 ;
     RECT  56.304 56.632 56.697 57.197 ;
     RECT  77.904 56.632 78.297 57.197 ;
     RECT  88.704 56.632 89.097 57.197 ;
     RECT  13.032 57.137 46.314 57.245 ;
     RECT  13.032 57.245 13.497 57.299 ;
     RECT  47.052 57.137 47.07 57.299 ;
     RECT  58.716 57.145 58.734 57.299 ;
     RECT  66.708 57.065 67.497 57.299 ;
     RECT  96.912 57.001 97.866 57.307 ;
     RECT  2.34 57.137 9.954 57.335 ;
     RECT  64.116 57.065 65.97 57.335 ;
     RECT  14.256 57.245 46.314 57.371 ;
     RECT  10.836 57.037 10.89 57.379 ;
     RECT  64.548 57.335 65.97 57.389 ;
     RECT  98.604 57.109 107.91 57.389 ;
     RECT  14.256 57.371 45.897 57.407 ;
     RECT  64.548 57.389 65.79 57.407 ;
     RECT  2.34 57.335 8.154 57.443 ;
     RECT  64.62 57.407 64.638 57.443 ;
     RECT  65.412 57.407 65.79 57.443 ;
     RECT  96.876 57.307 97.866 57.443 ;
     RECT  10.836 57.379 10.926 57.451 ;
     RECT  6.588 57.443 8.154 57.479 ;
     RECT  6.84 57.479 8.154 57.485 ;
     RECT  8.892 57.335 9.954 57.485 ;
     RECT  10.836 57.451 10.998 57.485 ;
     RECT  61.815 57.053 62.766 57.485 ;
     RECT  10.872 57.485 10.998 57.488 ;
     RECT  14.256 57.407 27.162 57.533 ;
     RECT  2.34 57.443 5.49 57.569 ;
     RECT  6.912 57.485 8.154 57.569 ;
     RECT  8.892 57.485 9.054 57.569 ;
     RECT  14.328 57.533 27.162 57.569 ;
     RECT  33.624 57.407 41.13 57.569 ;
     RECT  41.904 57.407 45.897 57.569 ;
     RECT  61.815 57.485 62.73 57.569 ;
     RECT  65.772 57.443 65.79 57.569 ;
     RECT  98.604 57.389 106.578 57.569 ;
     RECT  98.604 57.569 102.69 57.577 ;
     RECT  2.34 57.569 5.418 57.581 ;
     RECT  28.008 57.407 32.706 57.581 ;
     RECT  33.624 57.569 40.986 57.605 ;
     RECT  10.872 57.488 10.89 57.629 ;
     RECT  98.208 57.577 102.69 57.629 ;
     RECT  7.02 57.569 8.154 57.641 ;
     RECT  9.036 57.569 9.054 57.641 ;
     RECT  96.876 57.443 97.29 57.685 ;
     RECT  7.815 57.641 8.154 57.713 ;
     RECT  14.724 57.569 27.162 57.713 ;
     RECT  96.336 57.685 97.29 57.713 ;
     RECT  33.732 57.605 40.986 57.725 ;
     RECT  98.604 57.629 102.69 57.749 ;
     RECT  15.552 57.713 27.162 57.839 ;
     RECT  28.008 57.581 32.49 57.839 ;
     RECT  33.732 57.725 40.698 57.839 ;
     RECT  96.336 57.713 96.354 57.839 ;
     RECT  97.2 57.713 97.29 57.839 ;
     RECT  99.615 57.749 102.69 57.839 ;
     RECT  42.48 57.569 45.897 57.875 ;
     RECT  33.984 57.839 40.497 57.917 ;
     RECT  97.272 57.839 97.29 57.917 ;
     RECT  28.008 57.839 31.122 57.92 ;
     RECT  85.5 57.883 85.518 57.92 ;
     RECT  98.604 57.749 98.622 57.947 ;
     RECT  33.984 57.917 37.314 57.983 ;
     RECT  85.68 57.931 85.698 58.019 ;
     RECT  100.836 57.839 102.69 58.019 ;
     RECT  2.34 57.581 5.13 58.109 ;
     RECT  14.724 57.713 14.742 58.109 ;
     RECT  30.636 57.92 31.122 58.109 ;
     RECT  31.932 57.839 32.49 58.109 ;
     RECT  33.984 57.983 36.99 58.109 ;
     RECT  42.732 57.875 45.897 58.109 ;
     RECT  2.34 58.109 4.194 58.123 ;
     RECT  5.04 58.109 5.13 58.145 ;
     RECT  30.708 58.109 30.726 58.145 ;
     RECT  31.932 58.109 31.95 58.145 ;
     RECT  33.984 58.109 36.882 58.145 ;
     RECT  39.132 57.917 40.497 58.145 ;
     RECT  43.344 58.109 43.506 58.145 ;
     RECT  102.168 58.019 102.618 58.145 ;
     RECT  103.572 57.569 106.578 58.145 ;
     RECT  87.228 58.123 87.246 58.171 ;
     RECT  103.572 58.145 106.002 58.217 ;
     RECT  2.304 58.123 4.194 58.379 ;
     RECT  28.008 57.92 29.754 58.379 ;
     RECT  38.124 57.917 38.394 58.379 ;
     RECT  87.228 58.171 87.426 58.379 ;
     RECT  28.008 58.379 29.697 58.415 ;
     RECT  44.784 58.109 45.897 58.415 ;
     RECT  103.932 58.217 106.002 58.415 ;
     RECT  38.124 58.379 38.142 58.487 ;
     RECT  99.615 57.839 100.062 58.487 ;
     RECT  107.892 57.389 107.91 58.487 ;
     RECT  39.528 58.145 40.497 58.523 ;
     RECT  45.036 58.415 45.897 58.559 ;
     RECT  15.66 57.839 27.162 58.621 ;
     RECT  28.008 58.415 28.602 58.621 ;
     RECT  100.836 58.019 100.998 58.649 ;
     RECT  103.932 58.415 105.462 58.649 ;
     RECT  15.156 58.621 28.602 58.685 ;
     RECT  34.02 58.145 36.27 58.685 ;
     RECT  15.156 58.685 24.93 58.691 ;
     RECT  100.836 58.649 100.854 58.691 ;
     RECT  5.04 58.145 5.058 58.721 ;
     RECT  15.408 58.691 24.93 58.919 ;
     RECT  25.668 58.685 28.602 58.919 ;
     RECT  104.616 58.649 105.462 58.955 ;
     RECT  34.164 58.685 36.27 59.063 ;
     RECT  0.108 56.107 0.558 59.099 ;
     RECT  15.516 58.919 24.93 59.099 ;
     RECT  34.164 59.063 35.694 59.099 ;
     RECT  102.6 58.145 102.618 59.099 ;
     RECT  7.02 57.641 7.038 59.189 ;
     RECT  15.516 59.099 22.878 59.189 ;
     RECT  23.652 59.099 24.93 59.189 ;
     RECT  28.008 58.919 28.602 59.189 ;
     RECT  34.815 59.099 35.694 59.189 ;
     RECT  15.516 59.189 22.698 59.225 ;
     RECT  28.008 59.189 28.026 59.225 ;
     RECT  34.815 59.189 35.586 59.225 ;
     RECT  104.616 58.955 105.354 59.261 ;
     RECT  2.34 58.379 4.194 59.305 ;
     RECT  0.108 59.099 0.198 59.369 ;
     RECT  104.616 59.261 105.297 59.431 ;
     RECT  15.588 59.225 22.698 59.459 ;
     RECT  25.668 58.919 26.766 59.459 ;
     RECT  24.015 59.189 24.93 59.467 ;
     RECT  25.668 59.459 26.226 59.467 ;
     RECT  15.588 59.459 20.79 59.495 ;
     RECT  104.436 59.431 105.297 59.501 ;
     RECT  21.564 59.459 22.698 59.531 ;
     RECT  2.304 59.305 4.194 59.603 ;
     RECT  15.588 59.495 20.034 59.603 ;
     RECT  21.564 59.531 21.942 59.603 ;
     RECT  0.108 59.369 0.162 59.639 ;
     RECT  2.304 59.603 3.474 59.729 ;
     RECT  15.588 59.603 15.75 59.729 ;
     RECT  16.524 59.603 20.034 59.729 ;
     RECT  22.68 59.531 22.698 59.729 ;
     RECT  24.015 59.467 26.226 59.729 ;
     RECT  24.015 59.729 25.11 59.741 ;
     RECT  2.304 59.729 3.366 59.765 ;
     RECT  15.588 59.729 15.606 59.765 ;
     RECT  24.015 59.741 24.39 59.837 ;
     RECT  17.784 59.729 20.034 59.999 ;
     RECT  2.415 59.765 3.366 60.035 ;
     RECT  16.524 59.729 16.578 60.035 ;
     RECT  17.784 59.999 17.802 60.035 ;
     RECT  18.615 59.999 19.278 60.035 ;
     RECT  21.564 59.603 21.762 60.035 ;
     RECT  0.108 59.639 0.126 60.107 ;
     RECT  16.56 60.035 16.578 60.107 ;
     RECT  21.564 60.035 21.582 60.179 ;
     RECT  2.415 60.035 2.754 60.269 ;
     RECT  18.615 60.035 19.17 60.269 ;
     RECT  18.615 60.269 19.062 60.305 ;
     RECT  2.415 60.269 2.697 105.587 ;
     RECT  7.815 57.713 8.097 105.587 ;
     RECT  13.215 57.299 13.497 105.587 ;
     RECT  18.615 60.305 18.897 105.587 ;
     RECT  24.015 59.837 24.297 105.587 ;
     RECT  29.415 58.415 29.697 105.587 ;
     RECT  34.815 59.225 35.097 105.587 ;
     RECT  40.215 58.523 40.497 105.587 ;
     RECT  45.615 58.559 45.897 105.587 ;
     RECT  51.015 53.249 51.297 105.587 ;
     RECT  56.415 57.197 56.697 105.587 ;
     RECT  61.815 57.569 62.097 105.587 ;
     RECT  67.215 57.299 67.497 105.587 ;
     RECT  72.615 55.175 72.897 105.587 ;
     RECT  78.015 57.197 78.297 105.587 ;
     RECT  83.415 49.505 83.697 105.587 ;
     RECT  88.815 57.197 89.097 105.587 ;
     RECT  94.215 57.005 94.497 105.587 ;
     RECT  99.615 58.487 99.897 105.587 ;
     RECT  105.015 59.501 105.297 105.587 ;
     RECT  2.415 105.587 2.505 105.857 ;
     RECT  7.815 105.587 7.905 105.857 ;
     RECT  13.215 105.587 13.305 105.857 ;
     RECT  18.615 105.587 18.705 105.857 ;
     RECT  24.015 105.587 24.105 105.857 ;
     RECT  29.415 105.587 29.505 105.857 ;
     RECT  34.815 105.587 34.905 105.857 ;
     RECT  40.215 105.587 40.305 105.857 ;
     RECT  45.615 105.587 45.705 105.857 ;
     RECT  51.015 105.587 51.105 105.857 ;
     RECT  56.415 105.587 56.505 105.857 ;
     RECT  61.815 105.587 61.905 105.857 ;
     RECT  67.215 105.587 67.305 105.857 ;
     RECT  72.615 105.587 72.705 105.857 ;
     RECT  78.015 105.587 78.105 105.857 ;
     RECT  83.415 105.587 83.505 105.857 ;
     RECT  88.815 105.587 88.905 105.857 ;
     RECT  94.215 105.587 94.305 105.857 ;
     RECT  99.615 105.587 99.705 105.857 ;
     RECT  105.015 105.587 105.105 105.857 ;
    LAYER M4 ;
     RECT  0.06 40.464 0.137 46.536 ;
     RECT  0.137 40.56 0.173 46.536 ;
     RECT  2.252 38.928 2.293 38.952 ;
     RECT  0.06 48.816 2.293 49.608 ;
     RECT  0.133 36.912 2.408 36.936 ;
     RECT  2.293 38.928 2.408 39.24 ;
     RECT  0.173 40.656 2.408 46.536 ;
     RECT  2.293 48.48 2.408 49.608 ;
     RECT  0.06 53.52 2.408 56.52 ;
     RECT  2.293 58.128 2.408 58.152 ;
     RECT  2.293 59.856 2.408 59.88 ;
     RECT  2.408 2.148 2.512 105.852 ;
     RECT  2.512 2.418 2.704 105.582 ;
     RECT  2.704 59.856 2.765 59.88 ;
     RECT  2.704 53.232 2.801 58.68 ;
     RECT  2.704 38.688 2.837 41.16 ;
     RECT  2.801 53.232 2.837 58.536 ;
     RECT  2.837 56.304 2.867 58.152 ;
     RECT  2.704 42.192 2.945 47.88 ;
     RECT  2.704 36.912 2.981 37.608 ;
     RECT  2.837 53.232 2.981 55.272 ;
     RECT  2.837 38.88 3.053 41.16 ;
     RECT  2.981 37.584 3.059 37.608 ;
     RECT  3.053 38.88 3.305 40.68 ;
     RECT  2.945 43.536 3.341 47.736 ;
     RECT  3.305 38.88 3.413 40.488 ;
     RECT  3.341 43.536 3.413 46.728 ;
     RECT  3.413 39.168 3.485 40.488 ;
     RECT  2.704 49.008 3.817 49.512 ;
     RECT  2.867 56.304 3.877 57.624 ;
     RECT  3.877 56.304 3.913 58.104 ;
     RECT  2.945 42.192 3.949 42.504 ;
     RECT  3.949 42.192 4.021 42.744 ;
     RECT  3.341 47.712 4.057 47.736 ;
     RECT  3.817 49.488 4.165 49.512 ;
     RECT  2.981 53.232 4.165 54.984 ;
     RECT  3.913 55.968 4.165 58.104 ;
     RECT  3.485 39.264 4.453 40.488 ;
     RECT  4.021 41.952 4.453 42.744 ;
     RECT  4.057 47.712 4.547 48.504 ;
     RECT  4.453 39.264 4.561 42.744 ;
     RECT  3.413 43.824 4.561 46.728 ;
     RECT  4.165 53.232 4.601 58.104 ;
     RECT  4.561 39.264 4.705 46.728 ;
     RECT  4.601 53.232 4.739 57.624 ;
     RECT  4.705 38.784 4.777 46.728 ;
     RECT  4.739 53.232 4.853 57.576 ;
     RECT  4.777 38.496 4.981 46.728 ;
     RECT  4.547 47.712 4.981 47.928 ;
     RECT  4.981 38.496 5.123 47.928 ;
     RECT  5.123 38.496 5.249 47.88 ;
     RECT  5.249 39.216 5.285 47.88 ;
     RECT  5.285 39.504 5.501 47.88 ;
     RECT  4.853 53.328 5.821 57.576 ;
     RECT  5.821 53.28 6.001 57.576 ;
     RECT  5.501 39.504 6.221 47.832 ;
     RECT  6.221 39.504 6.445 47.352 ;
     RECT  4.165 49.488 6.613 49.608 ;
     RECT  6.445 39.504 7.153 47.256 ;
     RECT  7.153 38.736 7.808 47.256 ;
     RECT  6.613 49.2 7.808 49.608 ;
     RECT  7.669 51.36 7.808 51.384 ;
     RECT  6.001 53.04 7.808 57.576 ;
     RECT  7.808 2.148 7.912 105.852 ;
     RECT  7.912 2.418 8.104 105.582 ;
     RECT  8.104 53.04 8.201 57.576 ;
     RECT  8.104 38.736 8.243 47.16 ;
     RECT  8.104 51.84 8.243 52.008 ;
     RECT  8.201 53.04 8.273 54.216 ;
     RECT  8.243 46.272 8.849 47.16 ;
     RECT  8.243 38.736 9.245 45.24 ;
     RECT  8.273 53.088 9.313 54.216 ;
     RECT  9.245 38.736 9.389 44.184 ;
     RECT  9.313 53.04 10.213 54.216 ;
     RECT  8.201 55.248 10.213 57.576 ;
     RECT  8.104 49.152 10.253 49.56 ;
     RECT  10.213 53.04 10.325 57.576 ;
     RECT  8.243 51.84 10.825 51.864 ;
     RECT  10.325 55.44 10.861 57.576 ;
     RECT  10.825 51.744 10.865 51.864 ;
     RECT  9.389 42.576 10.933 44.184 ;
     RECT  9.245 45.216 10.933 45.24 ;
     RECT  10.933 42.576 11.077 45.24 ;
     RECT  11.077 42.528 11.257 45.24 ;
     RECT  9.389 38.736 11.473 40.968 ;
     RECT  11.257 42.48 11.473 45.24 ;
     RECT  11.473 38.736 13.208 45.24 ;
     RECT  8.849 46.32 13.208 47.16 ;
     RECT  10.253 49.536 13.208 49.56 ;
     RECT  10.865 51.744 13.208 51.768 ;
     RECT  10.325 53.04 13.208 54.312 ;
     RECT  10.861 55.44 13.208 57.624 ;
     RECT  13.208 2.148 13.312 105.852 ;
     RECT  13.312 2.418 13.504 105.582 ;
     RECT  13.504 38.736 14.357 47.304 ;
     RECT  13.504 55.44 14.713 57.624 ;
     RECT  13.504 48.768 14.821 49.56 ;
     RECT  13.504 53.04 14.821 54.312 ;
     RECT  14.821 48.72 14.933 49.56 ;
     RECT  14.713 55.44 15.145 58.104 ;
     RECT  14.821 53.04 15.325 54.408 ;
     RECT  15.145 55.44 15.577 58.68 ;
     RECT  14.357 38.736 15.653 47.16 ;
     RECT  15.325 53.04 15.692 54.456 ;
     RECT  15.577 55.44 15.692 59.256 ;
     RECT  15.692 53.04 15.733 59.256 ;
     RECT  13.504 51.744 15.779 51.768 ;
     RECT  15.653 46.32 15.901 47.16 ;
     RECT  14.933 48.768 15.901 49.56 ;
     RECT  15.433 50.64 16.085 50.664 ;
     RECT  15.901 46.32 16.153 47.304 ;
     RECT  15.901 48.288 16.153 49.56 ;
     RECT  15.733 53.04 17.173 59.736 ;
     RECT  17.173 52.992 17.201 59.736 ;
     RECT  16.153 46.32 17.413 49.56 ;
     RECT  17.201 59.232 18.169 59.736 ;
     RECT  18.169 59.232 18.421 59.784 ;
     RECT  17.201 52.992 18.469 57.96 ;
     RECT  18.469 52.992 18.565 58.008 ;
     RECT  18.421 58.992 18.565 59.784 ;
     RECT  15.653 38.736 18.608 45.24 ;
     RECT  17.413 46.32 18.608 49.608 ;
     RECT  18.133 50.64 18.608 50.664 ;
     RECT  18.565 52.992 18.608 59.784 ;
     RECT  18.608 2.148 18.712 105.852 ;
     RECT  18.712 2.418 18.904 105.582 ;
     RECT  18.904 52.992 19.331 60.024 ;
     RECT  19.331 52.992 19.613 59.736 ;
     RECT  18.904 46.32 20.045 49.56 ;
     RECT  19.613 53.04 21.661 59.736 ;
     RECT  21.661 53.04 21.809 59.832 ;
     RECT  21.809 53.04 22.241 58.2 ;
     RECT  20.045 46.32 22.381 48.12 ;
     RECT  20.045 49.536 22.381 49.56 ;
     RECT  20.473 50.88 22.669 50.904 ;
     RECT  22.669 50.832 22.705 50.904 ;
     RECT  22.705 50.832 22.789 51 ;
     RECT  22.241 53.04 23.209 54.456 ;
     RECT  22.241 55.488 23.209 58.2 ;
     RECT  22.381 46.32 23.461 49.56 ;
     RECT  22.789 50.832 23.461 51.24 ;
     RECT  18.904 38.736 24.008 45.24 ;
     RECT  23.461 46.32 24.008 51.24 ;
     RECT  23.209 53.04 24.008 58.2 ;
     RECT  21.809 59.808 24.008 59.832 ;
     RECT  24.008 2.148 24.112 105.852 ;
     RECT  24.112 2.418 24.304 105.582 ;
     RECT  24.304 59.472 24.401 59.832 ;
     RECT  24.401 59.472 25.121 59.736 ;
     RECT  24.304 53.04 25.373 58.392 ;
     RECT  24.304 46.32 25.619 51.288 ;
     RECT  25.121 59.472 26.125 59.592 ;
     RECT  25.619 50.688 26.492 51.288 ;
     RECT  26.492 50.688 26.579 51.768 ;
     RECT  25.373 53.04 26.773 58.2 ;
     RECT  26.125 59.28 26.773 59.592 ;
     RECT  26.773 53.04 27.173 59.592 ;
     RECT  26.579 50.688 27.301 51.192 ;
     RECT  27.301 50.544 28.037 51.192 ;
     RECT  27.173 55.488 28.037 59.592 ;
     RECT  28.037 50.544 28.217 51.144 ;
     RECT  28.217 50.544 28.397 50.952 ;
     RECT  24.304 38.736 28.597 45.24 ;
     RECT  25.619 46.32 28.597 49.56 ;
     RECT  28.597 38.688 28.604 49.56 ;
     RECT  28.397 50.544 28.604 50.904 ;
     RECT  27.173 53.04 28.609 54.504 ;
     RECT  28.037 55.488 28.609 58.392 ;
     RECT  28.604 38.688 29.077 50.904 ;
     RECT  29.077 38.4 29.408 50.904 ;
     RECT  28.609 53.04 29.408 58.392 ;
     RECT  28.037 59.568 29.408 59.592 ;
     RECT  29.408 2.148 29.512 105.852 ;
     RECT  29.512 2.418 29.704 105.582 ;
     RECT  29.704 59.568 29.843 59.592 ;
     RECT  29.704 37.584 30.275 51.96 ;
     RECT  30.275 38.16 31.309 51.96 ;
     RECT  29.704 53.04 31.309 58.2 ;
     RECT  31.309 38.16 31.345 58.2 ;
     RECT  31.345 37.92 31.565 58.2 ;
     RECT  31.565 38.112 31.637 58.2 ;
     RECT  31.637 38.112 32.609 49.752 ;
     RECT  32.609 38.256 33.001 49.752 ;
     RECT  31.637 50.832 33.001 58.2 ;
     RECT  33.001 38.256 33.005 58.2 ;
     RECT  33.005 38.64 34.081 58.2 ;
     RECT  34.081 37.968 34.22 58.2 ;
     RECT  34.22 37.584 34.808 58.2 ;
     RECT  34.808 2.148 34.912 105.852 ;
     RECT  34.912 2.418 35.104 105.582 ;
     RECT  35.104 53.232 35.356 58.632 ;
     RECT  35.104 37.968 35.381 45.288 ;
     RECT  35.104 52.128 35.954 52.2 ;
     RECT  35.954 52.128 36.179 52.152 ;
     RECT  35.381 38.016 36.205 45.288 ;
     RECT  35.104 46.32 36.205 51 ;
     RECT  36.205 38.016 36.277 51 ;
     RECT  36.277 38.016 36.425 51.768 ;
     RECT  36.425 38.016 36.563 50.328 ;
     RECT  36.563 38.496 36.785 50.328 ;
     RECT  36.785 38.688 36.821 50.328 ;
     RECT  36.821 38.736 37.253 50.328 ;
     RECT  36.425 51.744 38.221 51.768 ;
     RECT  38.221 51.744 38.329 51.816 ;
     RECT  35.356 53.232 38.401 58.2 ;
     RECT  37.253 38.736 38.549 50.232 ;
     RECT  38.329 51.744 38.585 51.96 ;
     RECT  38.585 51.744 38.869 51.816 ;
     RECT  38.549 38.736 39.589 44.76 ;
     RECT  38.549 45.792 39.589 50.04 ;
     RECT  39.589 38.736 40.201 50.04 ;
     RECT  39.205 23.376 40.208 23.4 ;
     RECT  40.201 38.736 40.208 50.088 ;
     RECT  38.869 51.168 40.208 51.816 ;
     RECT  38.401 53.04 40.208 58.2 ;
     RECT  40.208 2.148 40.312 105.852 ;
     RECT  40.312 2.418 40.504 105.582 ;
     RECT  40.504 38.736 41.605 51.288 ;
     RECT  41.605 38.544 42.109 51.288 ;
     RECT  40.504 52.992 42.221 58.2 ;
     RECT  42.109 38.544 43.085 51.816 ;
     RECT  43.285 38.16 44.197 38.184 ;
     RECT  44.197 37.584 44.629 38.184 ;
     RECT  43.085 39.312 44.629 51.816 ;
     RECT  44.629 37.584 45.133 51.816 ;
     RECT  45.133 37.584 45.205 51.96 ;
     RECT  45.205 37.584 45.241 52.056 ;
     RECT  42.221 53.04 45.241 58.2 ;
     RECT  45.241 37.584 45.608 58.2 ;
     RECT  45.608 2.148 45.712 105.852 ;
     RECT  45.712 2.418 45.904 105.582 ;
     RECT  45.904 39.84 46.865 58.2 ;
     RECT  46.865 39.984 46.901 58.2 ;
     RECT  45.904 38.16 48.521 38.856 ;
     RECT  46.901 39.984 48.593 52.056 ;
     RECT  48.521 38.736 48.949 38.856 ;
     RECT  48.593 39.984 48.949 51.24 ;
     RECT  48.949 38.736 48.995 51.24 ;
     RECT  46.901 53.232 49.457 58.2 ;
     RECT  48.995 39.216 51.008 51.24 ;
     RECT  49.457 53.376 51.008 58.2 ;
     RECT  51.008 2.148 51.112 105.852 ;
     RECT  51.112 2.418 51.304 105.582 ;
     RECT  51.304 39.84 51.761 51.24 ;
     RECT  51.761 40.08 52.553 51.24 ;
     RECT  52.553 40.08 53.701 46.104 ;
     RECT  52.553 47.424 53.701 51.24 ;
     RECT  53.701 40.08 54.889 51.24 ;
     RECT  54.889 40.08 55.001 51.432 ;
     RECT  51.304 53.376 55.141 58.2 ;
     RECT  55.001 47.088 55.429 51.432 ;
     RECT  55.429 47.088 56.293 51.48 ;
     RECT  55.141 52.992 56.293 58.2 ;
     RECT  55.001 40.08 56.408 46.104 ;
     RECT  56.293 47.088 56.408 58.2 ;
     RECT  56.408 2.148 56.512 105.852 ;
     RECT  56.512 2.418 56.704 105.582 ;
     RECT  56.704 47.568 56.909 58.2 ;
     RECT  56.909 53.136 57.809 58.2 ;
     RECT  56.704 40.656 58.061 46.248 ;
     RECT  56.909 47.568 58.705 51.816 ;
     RECT  58.705 47.088 59.069 51.816 ;
     RECT  58.061 40.656 59.141 46.056 ;
     RECT  59.141 43.008 59.173 46.056 ;
     RECT  59.069 47.088 59.173 48.456 ;
     RECT  59.173 43.008 59.285 48.456 ;
     RECT  59.069 49.488 59.425 51.816 ;
     RECT  59.425 49.488 59.612 52.2 ;
     RECT  57.809 53.376 59.612 58.2 ;
     RECT  59.612 49.488 59.699 58.2 ;
     RECT  59.285 43.008 60.185 48.312 ;
     RECT  59.699 53.328 60.257 58.2 ;
     RECT  60.185 43.056 60.289 48.312 ;
     RECT  59.699 49.488 60.289 52.2 ;
     RECT  60.289 43.056 61.117 52.2 ;
     RECT  59.141 40.656 61.153 42.024 ;
     RECT  61.117 43.056 61.153 52.248 ;
     RECT  61.153 40.656 61.513 52.248 ;
     RECT  60.257 53.376 61.513 58.2 ;
     RECT  61.513 40.656 61.808 58.2 ;
     RECT  61.808 2.148 61.912 105.852 ;
     RECT  61.912 2.418 62.104 105.582 ;
     RECT  62.104 40.656 62.201 51.24 ;
     RECT  62.201 40.656 63.425 48.264 ;
     RECT  62.201 49.536 63.541 51.24 ;
     RECT  62.104 52.224 63.541 58.2 ;
     RECT  63.425 47.664 63.745 48.264 ;
     RECT  63.541 49.536 63.745 58.2 ;
     RECT  63.425 40.656 64.937 46.68 ;
     RECT  64.937 43.056 65.473 46.68 ;
     RECT  63.745 47.664 65.473 58.2 ;
     RECT  64.937 40.656 67.208 42.024 ;
     RECT  65.473 43.056 67.208 58.2 ;
     RECT  67.208 2.148 67.312 105.852 ;
     RECT  67.312 2.418 67.504 105.582 ;
     RECT  67.504 43.056 67.709 58.2 ;
     RECT  67.709 43.056 68.573 52.2 ;
     RECT  68.573 43.056 68.969 48.456 ;
     RECT  68.573 49.488 69.001 52.2 ;
     RECT  67.709 53.28 69.001 58.2 ;
     RECT  68.969 47.568 70.261 48.456 ;
     RECT  69.001 49.488 70.261 58.2 ;
     RECT  68.969 43.056 70.945 46.536 ;
     RECT  70.261 47.568 70.945 58.2 ;
     RECT  67.504 40.656 72.608 42.024 ;
     RECT  70.945 43.056 72.608 58.2 ;
     RECT  72.608 2.148 72.712 105.852 ;
     RECT  72.712 2.418 72.904 105.582 ;
     RECT  72.904 43.056 73.289 58.2 ;
     RECT  73.289 43.056 73.685 52.2 ;
     RECT  73.685 43.056 74.189 51.96 ;
     RECT  74.189 47.568 74.693 51.96 ;
     RECT  74.189 43.056 76.561 46.536 ;
     RECT  74.693 47.568 76.561 48.456 ;
     RECT  76.561 43.056 76.645 48.456 ;
     RECT  74.693 49.536 76.645 51.96 ;
     RECT  72.904 40.656 78.008 42.024 ;
     RECT  76.645 43.056 78.008 51.96 ;
     RECT  73.289 53.376 78.008 58.2 ;
     RECT  78.008 2.148 78.112 105.852 ;
     RECT  78.112 2.418 78.304 105.582 ;
     RECT  78.304 43.056 79.553 51.96 ;
     RECT  79.553 49.536 81.02 51.96 ;
     RECT  81.02 49.488 81.107 51.96 ;
     RECT  78.304 40.656 83.408 42.024 ;
     RECT  79.553 43.056 83.408 48.12 ;
     RECT  81.107 49.536 83.408 51.96 ;
     RECT  78.304 53.376 83.408 58.2 ;
     RECT  83.408 2.148 83.512 105.852 ;
     RECT  83.512 2.418 83.704 105.582 ;
     RECT  83.704 53.376 87.437 58.2 ;
     RECT  87.437 53.376 87.779 58.152 ;
     RECT  83.704 40.656 88.808 42.024 ;
     RECT  83.704 43.056 88.808 48.12 ;
     RECT  83.704 49.584 88.808 51.96 ;
     RECT  87.779 53.376 88.808 57.912 ;
     RECT  88.808 2.148 88.912 105.852 ;
     RECT  88.912 2.418 89.104 105.582 ;
     RECT  89.104 43.056 93.985 48.12 ;
     RECT  89.104 49.584 93.985 51.96 ;
     RECT  89.104 40.656 94.208 42.024 ;
     RECT  93.985 43.056 94.208 51.96 ;
     RECT  89.104 53.376 94.208 57.912 ;
     RECT  94.208 2.148 94.312 105.852 ;
     RECT  94.312 2.418 94.504 105.582 ;
     RECT  94.504 40.656 96.113 57.912 ;
     RECT  96.113 40.656 96.257 53.4 ;
     RECT  96.113 54.432 97.045 57.912 ;
     RECT  96.257 40.656 97.337 43.08 ;
     RECT  97.337 42 97.697 43.08 ;
     RECT  97.697 43.056 97.801 43.08 ;
     RECT  96.257 44.064 97.801 53.4 ;
     RECT  97.801 43.056 98.057 53.4 ;
     RECT  98.057 43.584 98.125 53.4 ;
     RECT  97.045 54.432 98.125 58.536 ;
     RECT  97.337 40.656 98.633 40.92 ;
     RECT  97.697 42 98.917 42.024 ;
     RECT  98.633 40.896 99.608 40.92 ;
     RECT  98.917 41.952 99.608 42.024 ;
     RECT  98.125 43.584 99.608 58.536 ;
     RECT  99.608 2.148 99.712 105.852 ;
     RECT  99.712 2.418 99.904 105.582 ;
     RECT  99.904 41.952 100.001 59.496 ;
     RECT  100.001 41.952 100.109 55.752 ;
     RECT  100.109 41.952 100.253 42.792 ;
     RECT  100.253 42 100.649 42.792 ;
     RECT  100.649 42.144 100.973 42.792 ;
     RECT  100.109 43.92 101.113 55.752 ;
     RECT  100.001 56.784 101.113 59.496 ;
     RECT  100.973 42.768 101.617 42.792 ;
     RECT  101.113 43.92 101.617 59.496 ;
     RECT  101.617 42.768 102.277 59.496 ;
     RECT  102.277 42.72 102.323 59.496 ;
     RECT  102.323 44.256 102.413 59.496 ;
     RECT  102.413 44.256 102.593 48.456 ;
     RECT  102.323 42.72 102.665 42.744 ;
     RECT  102.593 44.88 102.701 48.456 ;
     RECT  102.701 44.88 102.737 48.408 ;
     RECT  102.737 44.88 103.061 46.056 ;
     RECT  103.061 44.88 103.205 46.008 ;
     RECT  102.413 55.248 103.241 59.496 ;
     RECT  102.413 49.632 103.277 54.264 ;
     RECT  103.277 50.304 103.853 54.264 ;
     RECT  103.853 50.304 103.925 51.384 ;
     RECT  103.241 56.4 103.961 59.496 ;
     RECT  103.853 52.416 104.137 54.264 ;
     RECT  103.241 55.248 104.137 55.272 ;
     RECT  103.205 44.88 104.317 45.96 ;
     RECT  102.737 47.04 104.317 48.408 ;
     RECT  104.317 44.88 104.821 48.408 ;
     RECT  103.925 51.12 104.893 51.384 ;
     RECT  104.137 52.416 104.893 55.272 ;
     RECT  103.813 43.392 105.008 43.416 ;
     RECT  104.821 44.88 105.008 48.744 ;
     RECT  104.893 51.12 105.008 55.272 ;
     RECT  103.961 56.4 105.008 57.912 ;
     RECT  103.961 59.472 105.008 59.496 ;
     RECT  105.008 2.148 105.112 105.852 ;
     RECT  105.112 2.418 105.304 105.582 ;
     RECT  105.304 44.928 105.473 57.288 ;
     RECT  105.304 42.192 106.477 43.752 ;
     RECT  105.473 44.928 106.477 53.64 ;
     RECT  106.477 42.192 106.513 53.64 ;
     RECT  105.473 54.768 106.513 57.288 ;
     RECT  106.513 42.192 107.161 57.288 ;
     RECT  107.161 42.192 107.881 57.384 ;
     RECT  107.881 42.192 107.964 57.48 ;
    LAYER M5 ;
     RECT  39.12 0.016 39.24 2.137 ;
     RECT  2.4 2.137 2.52 2.151 ;
     RECT  7.8 2.137 7.92 2.151 ;
     RECT  13.2 2.137 13.32 2.151 ;
     RECT  18.6 2.137 18.72 2.151 ;
     RECT  24 2.137 24.12 2.151 ;
     RECT  29.4 2.137 29.52 2.151 ;
     RECT  34.8 2.137 34.92 2.151 ;
     RECT  39.12 2.137 40.32 2.151 ;
     RECT  45.6 2.137 45.72 2.151 ;
     RECT  51 2.137 51.12 2.151 ;
     RECT  56.4 2.137 56.52 2.151 ;
     RECT  61.8 2.137 61.92 2.151 ;
     RECT  67.2 2.137 67.32 2.151 ;
     RECT  72.6 2.137 72.72 2.151 ;
     RECT  78 2.137 78.12 2.151 ;
     RECT  83.4 2.137 83.52 2.151 ;
     RECT  88.8 2.137 88.92 2.151 ;
     RECT  94.2 2.137 94.32 2.151 ;
     RECT  99.6 2.137 99.72 2.151 ;
     RECT  105 2.137 105.12 2.151 ;
     RECT  39.12 2.151 40.512 23.411 ;
     RECT  2.4 2.151 2.712 37.573 ;
     RECT  29.4 2.151 29.712 37.573 ;
     RECT  34.8 2.151 35.112 37.573 ;
     RECT  45.6 2.151 45.912 37.573 ;
     RECT  29.4 37.573 30.264 38.195 ;
     RECT  43.296 38.149 43.32 38.533 ;
     RECT  29.4 38.195 29.712 38.677 ;
     RECT  31.92 38.149 31.944 38.723 ;
     RECT  2.4 37.573 3.048 38.917 ;
     RECT  36.528 38.005 36.552 39.205 ;
     RECT  2.304 38.917 3.048 39.251 ;
     RECT  36.528 39.205 37.032 39.299 ;
     RECT  42.672 38.533 43.32 39.347 ;
     RECT  44.976 37.573 45.912 39.347 ;
     RECT  28.608 38.677 29.712 39.395 ;
     RECT  48.96 38.725 48.984 40.019 ;
     RECT  34.272 37.573 35.112 40.213 ;
     RECT  33.648 40.213 35.112 40.259 ;
     RECT  51 2.151 51.312 40.405 ;
     RECT  32.208 39.109 32.232 40.549 ;
     RECT  31.728 40.549 32.232 40.595 ;
     RECT  39.12 23.411 39.144 40.741 ;
     RECT  40.2 23.411 40.512 40.741 ;
     RECT  47.952 39.973 47.976 40.835 ;
     RECT  56.4 2.151 56.712 40.981 ;
     RECT  9.168 40.837 9.192 41.027 ;
     RECT  33.648 40.259 33.672 41.075 ;
     RECT  4.656 40.405 4.68 41.219 ;
     RECT  37.008 39.299 37.032 41.269 ;
     RECT  34.8 40.259 35.112 41.413 ;
     RECT  43.296 39.347 43.32 41.509 ;
     RECT  50.16 40.405 51.312 41.509 ;
     RECT  49.536 41.509 51.312 41.651 ;
     RECT  45.504 39.347 45.912 41.699 ;
     RECT  0.144 36.901 0.168 42.035 ;
     RECT  34.8 41.413 35.592 42.085 ;
     RECT  37.008 41.269 37.464 42.085 ;
     RECT  2.4 39.251 3.048 42.227 ;
     RECT  34.8 42.085 37.464 42.275 ;
     RECT  39.12 40.741 40.512 42.275 ;
     RECT  27.312 39.205 27.336 42.323 ;
     RECT  34.8 42.275 36.504 42.323 ;
     RECT  55.44 40.981 56.712 42.469 ;
     RECT  61.8 2.151 62.112 42.709 ;
     RECT  45.6 41.699 45.912 43.141 ;
     RECT  29.4 39.395 29.712 43.285 ;
     RECT  6.432 40.981 6.456 43.379 ;
     RECT  36.48 42.323 36.504 43.379 ;
     RECT  49.536 41.651 49.56 43.379 ;
     RECT  102.288 42.709 102.312 43.523 ;
     RECT  99.6 2.151 99.912 43.621 ;
     RECT  2.4 42.227 2.712 43.813 ;
     RECT  45.504 43.141 45.912 44.051 ;
     RECT  47.376 43.237 47.4 44.051 ;
     RECT  70.656 43.525 70.68 44.099 ;
     RECT  55.296 42.469 56.712 44.243 ;
     RECT  58.56 42.997 58.584 44.339 ;
     RECT  68.544 41.941 68.568 44.339 ;
     RECT  40.2 42.275 40.512 44.437 ;
     RECT  55.632 44.243 56.712 44.483 ;
     RECT  7.8 2.151 8.112 44.485 ;
     RECT  37.008 44.725 37.032 44.867 ;
     RECT  101.808 44.389 101.832 44.915 ;
     RECT  72.6 2.151 72.912 44.917 ;
     RECT  0.192 44.725 0.216 45.011 ;
     RECT  28.512 43.285 29.712 45.059 ;
     RECT  40.2 44.437 41.352 45.059 ;
     RECT  53.424 44.197 53.448 45.059 ;
     RECT  65.808 44.197 65.832 45.059 ;
     RECT  61.2 42.709 62.112 45.203 ;
     RECT  43.296 41.509 43.368 45.205 ;
     RECT  5.088 45.157 5.112 45.253 ;
     RECT  6.384 43.765 6.408 45.253 ;
     RECT  67.2 2.151 67.512 45.253 ;
     RECT  61.536 45.203 62.112 45.299 ;
     RECT  2.4 43.813 2.856 45.397 ;
     RECT  97.056 44.917 97.08 45.443 ;
     RECT  2.4 45.397 3.768 45.445 ;
     RECT  99.312 43.621 99.912 45.445 ;
     RECT  98.592 45.445 99.912 45.541 ;
     RECT  45.6 44.051 45.912 45.589 ;
     RECT  5.088 45.253 6.408 45.685 ;
     RECT  31.728 40.595 31.752 45.685 ;
     RECT  7.8 44.485 8.232 45.731 ;
     RECT  45.6 45.589 46.056 46.115 ;
     RECT  55.056 45.301 55.08 46.115 ;
     RECT  70.656 45.301 70.68 46.115 ;
     RECT  29.04 45.059 29.712 46.117 ;
     RECT  43.296 45.205 43.704 46.117 ;
     RECT  31.008 45.685 31.752 46.211 ;
     RECT  102 45.397 102.024 46.211 ;
     RECT  5.088 45.685 6.504 46.261 ;
     RECT  39.12 42.275 39.144 46.357 ;
     RECT  40.2 45.059 40.512 46.357 ;
     RECT  98.352 45.541 99.912 46.403 ;
     RECT  31.008 46.211 31.032 46.499 ;
     RECT  67.2 45.253 67.848 46.501 ;
     RECT  61.68 45.299 62.112 46.645 ;
     RECT  4.992 46.261 6.504 46.739 ;
     RECT  4.992 46.739 6.408 46.787 ;
     RECT  99.312 46.403 99.912 46.787 ;
     RECT  76.992 46.501 77.016 46.789 ;
     RECT  72.6 44.917 73.032 46.835 ;
     RECT  49.536 45.541 49.56 47.173 ;
     RECT  49.536 47.173 49.944 47.315 ;
     RECT  6.384 46.787 6.408 47.363 ;
     RECT  61.68 46.645 62.952 47.363 ;
     RECT  76.656 46.789 77.016 47.363 ;
     RECT  38.112 46.789 38.136 47.651 ;
     RECT  2.304 45.445 3.768 47.797 ;
     RECT  4.992 46.787 5.112 47.797 ;
     RECT  28.608 46.117 29.712 47.843 ;
     RECT  2.304 47.797 5.112 47.939 ;
     RECT  102 47.269 102.024 47.939 ;
     RECT  39.12 46.357 40.512 47.987 ;
     RECT  45.6 46.115 45.912 48.037 ;
     RECT  49.92 47.315 49.944 48.037 ;
     RECT  51 41.651 51.312 48.037 ;
     RECT  40.08 47.987 40.512 48.085 ;
     RECT  30.864 47.269 30.888 48.227 ;
     RECT  45.072 48.037 45.912 48.227 ;
     RECT  58.704 47.989 58.728 48.227 ;
     RECT  34.8 42.323 35.112 48.277 ;
     RECT  42.864 46.117 43.704 48.277 ;
     RECT  45.6 48.227 45.912 48.277 ;
     RECT  34.08 48.277 35.112 48.467 ;
     RECT  40.08 48.085 40.632 48.467 ;
     RECT  2.304 47.939 4.536 48.515 ;
     RECT  49.92 48.037 51.312 48.515 ;
     RECT  50.688 48.515 51.312 48.707 ;
     RECT  42.432 48.277 43.704 48.755 ;
     RECT  30.768 48.757 30.792 48.899 ;
     RECT  99.504 46.787 99.912 48.901 ;
     RECT  45.6 48.277 46.488 48.949 ;
     RECT  2.4 48.515 3.768 49.043 ;
     RECT  76.656 47.363 76.68 49.043 ;
     RECT  42.432 48.755 43.368 49.235 ;
     RECT  7.8 45.731 8.112 49.285 ;
     RECT  67.2 46.501 68.28 49.285 ;
     RECT  29.4 47.843 29.712 49.333 ;
     RECT  51 48.707 51.312 49.333 ;
     RECT  43.344 49.235 43.368 49.475 ;
     RECT  61.68 47.363 62.112 49.477 ;
     RECT  40.08 48.467 40.512 49.523 ;
     RECT  49.536 48.997 49.56 49.667 ;
     RECT  61.536 49.477 62.112 49.715 ;
     RECT  56.4 44.483 56.712 49.717 ;
     RECT  28.656 49.333 29.712 49.813 ;
     RECT  72.6 46.835 72.912 49.861 ;
     RECT  56.304 49.717 56.712 49.907 ;
     RECT  69.504 49.477 69.528 50.003 ;
     RECT  81.072 49.477 81.096 50.051 ;
     RECT  45.6 48.949 46.536 50.101 ;
     RECT  99.024 48.901 99.912 50.339 ;
     RECT  45.6 50.101 47.112 50.389 ;
     RECT  51 49.333 51.768 50.435 ;
     RECT  27.312 48.373 27.336 50.579 ;
     RECT  63.888 48.997 63.912 50.579 ;
     RECT  28.656 49.813 30.312 50.675 ;
     RECT  45.6 50.389 47.448 50.771 ;
     RECT  72.48 49.861 72.912 50.771 ;
     RECT  90.624 50.821 90.648 50.963 ;
     RECT  25.584 50.389 25.608 51.109 ;
     RECT  22.8 50.965 22.824 51.251 ;
     RECT  34.8 48.467 35.112 51.253 ;
     RECT  25.584 51.109 26.568 51.299 ;
     RECT  42.72 50.869 42.744 51.299 ;
     RECT  67.2 49.285 68.376 51.347 ;
     RECT  7.68 49.285 8.112 51.395 ;
     RECT  45.6 50.771 46.056 51.395 ;
     RECT  92.88 49.621 92.904 51.923 ;
     RECT  95.904 51.253 95.928 51.923 ;
     RECT  29.4 50.675 30.312 51.971 ;
     RECT  47.04 50.771 47.448 51.971 ;
     RECT  73.968 50.677 73.992 51.971 ;
     RECT  7.8 51.395 8.112 51.973 ;
     RECT  99.504 50.339 99.912 52.069 ;
     RECT  36.144 49.525 36.168 52.163 ;
     RECT  34.32 51.253 35.112 52.211 ;
     RECT  63.552 51.013 63.576 52.259 ;
     RECT  56.4 49.907 56.712 52.261 ;
     RECT  99.504 52.069 100.728 52.357 ;
     RECT  67.2 51.347 67.512 52.981 ;
     RECT  99.504 52.357 100.824 52.981 ;
     RECT  56.304 52.261 56.712 53.027 ;
     RECT  40.2 49.523 40.512 53.029 ;
     RECT  26.544 51.299 26.568 53.171 ;
     RECT  99.504 52.981 100.872 53.173 ;
     RECT  34.8 52.211 35.112 53.269 ;
     RECT  7.8 51.973 8.232 53.459 ;
     RECT  64.992 53.077 65.016 53.459 ;
     RECT  15.744 51.733 15.768 53.461 ;
     RECT  24 2.151 24.312 53.509 ;
     RECT  59.664 52.741 59.688 53.603 ;
     RECT  72.6 50.771 72.912 53.605 ;
     RECT  40.2 53.029 41.112 53.941 ;
     RECT  40.08 53.941 41.112 54.083 ;
     RECT  34.224 53.269 35.112 54.085 ;
     RECT  99.216 53.173 100.872 54.085 ;
     RECT  17.184 52.981 17.208 54.131 ;
     RECT  47.04 51.971 47.064 54.131 ;
     RECT  53.28 45.493 53.304 54.179 ;
     RECT  70.656 53.509 70.68 54.179 ;
     RECT  99.216 54.085 100.968 54.179 ;
     RECT  103.152 53.509 103.176 54.227 ;
     RECT  15.456 53.461 15.768 54.371 ;
     RECT  21.696 53.509 21.72 54.371 ;
     RECT  100.944 54.179 100.968 54.565 ;
     RECT  24 53.509 24.408 54.611 ;
     RECT  97.056 54.517 97.08 54.613 ;
     RECT  20.112 54.085 20.136 54.659 ;
     RECT  29.4 51.971 30.024 54.659 ;
     RECT  67.2 52.981 67.608 54.755 ;
     RECT  100.944 54.565 101.448 54.803 ;
     RECT  37.056 53.941 37.08 54.851 ;
     RECT  72.48 53.605 72.912 54.899 ;
     RECT  34.224 54.085 35.208 54.947 ;
     RECT  66.048 49.861 66.072 54.949 ;
     RECT  96.288 54.613 97.08 55.043 ;
     RECT  45.6 51.395 45.912 55.045 ;
     RECT  34.224 54.947 35.112 55.139 ;
     RECT  7.8 53.459 8.112 55.285 ;
     RECT  9.36 51.829 9.384 55.285 ;
     RECT  24 54.611 24.312 55.285 ;
     RECT  96.288 55.043 96.888 55.331 ;
     RECT  7.8 55.285 9.384 55.475 ;
     RECT  44.832 55.045 45.912 55.861 ;
     RECT  23.328 55.285 24.312 55.907 ;
     RECT  99.216 54.179 99.912 56.003 ;
     RECT  15.6 54.371 15.768 56.243 ;
     RECT  38.592 54.565 38.616 56.339 ;
     RECT  40.08 54.083 40.512 56.387 ;
     RECT  44.832 55.861 46.008 56.387 ;
     RECT  27.12 55.669 27.144 56.483 ;
     RECT  101.424 54.803 101.448 56.483 ;
     RECT  2.4 49.043 2.712 56.485 ;
     RECT  65.856 54.949 66.072 56.533 ;
     RECT  45.6 56.387 46.008 56.723 ;
     RECT  40.2 56.387 40.512 56.725 ;
     RECT  2.304 56.485 2.712 56.773 ;
     RECT  6.576 56.677 6.6 56.819 ;
     RECT  96.864 55.331 96.888 56.867 ;
     RECT  40.2 56.725 41.016 56.915 ;
     RECT  98.592 56.389 98.616 56.965 ;
     RECT  9.36 55.475 9.384 57.011 ;
     RECT  34.8 55.139 35.112 57.013 ;
     RECT  63.264 54.853 63.288 57.059 ;
     RECT  65.568 56.533 66.072 57.059 ;
     RECT  15.744 56.243 15.768 57.205 ;
     RECT  14.832 57.205 15.768 57.347 ;
     RECT  42.72 54.037 42.744 57.347 ;
     RECT  98.016 56.965 98.616 57.397 ;
     RECT  15.744 57.347 15.768 57.445 ;
     RECT  29.4 54.659 29.832 57.445 ;
     RECT  66.048 57.059 66.072 57.491 ;
     RECT  4.704 56.869 4.728 57.635 ;
     RECT  97.056 57.397 98.616 57.635 ;
     RECT  97.056 57.635 98.04 57.875 ;
     RECT  20.688 57.445 20.712 57.925 ;
     RECT  18.6 2.151 18.912 57.973 ;
     RECT  34.8 57.013 35.544 58.115 ;
     RECT  2.304 56.773 2.856 58.163 ;
     RECT  22.944 57.205 22.968 58.163 ;
     RECT  87.744 57.013 87.768 58.163 ;
     RECT  29.28 57.445 29.832 58.403 ;
     RECT  97.056 57.875 97.08 58.547 ;
     RECT  34.8 58.115 35.304 58.643 ;
     RECT  101.424 58.117 101.448 58.643 ;
     RECT  99.6 56.003 99.912 58.645 ;
     RECT  20.4 57.925 20.712 58.691 ;
     RECT  18.48 57.973 18.912 58.789 ;
     RECT  20.688 58.691 20.712 58.835 ;
     RECT  18.48 58.789 19.32 59.027 ;
     RECT  26.784 57.685 26.808 59.315 ;
     RECT  99.6 58.645 100.872 59.507 ;
     RECT  29.4 58.403 29.832 59.603 ;
     RECT  15.744 57.445 16.584 59.699 ;
     RECT  15.744 59.699 15.768 59.747 ;
     RECT  2.304 58.163 2.712 59.891 ;
     RECT  18.6 59.027 19.32 60.035 ;
     RECT  2.4 59.891 2.712 105.849 ;
     RECT  7.8 55.475 8.112 105.849 ;
     RECT  13.2 2.151 13.512 105.849 ;
     RECT  18.6 60.035 18.912 105.849 ;
     RECT  24 55.907 24.312 105.849 ;
     RECT  29.4 59.603 29.712 105.849 ;
     RECT  34.8 58.643 35.112 105.849 ;
     RECT  40.2 56.915 40.512 105.849 ;
     RECT  45.6 56.723 45.912 105.849 ;
     RECT  51 50.435 51.312 105.849 ;
     RECT  56.4 53.027 56.712 105.849 ;
     RECT  61.8 49.715 62.112 105.849 ;
     RECT  67.2 54.755 67.512 105.849 ;
     RECT  72.6 54.899 72.912 105.849 ;
     RECT  78 2.151 78.312 105.849 ;
     RECT  83.4 2.151 83.712 105.849 ;
     RECT  88.8 2.151 89.112 105.849 ;
     RECT  94.2 2.151 94.512 105.849 ;
     RECT  99.6 59.507 99.912 105.849 ;
     RECT  105 2.151 105.312 105.849 ;
     RECT  2.4 105.849 2.52 105.863 ;
     RECT  7.8 105.849 7.92 105.863 ;
     RECT  13.2 105.849 13.32 105.863 ;
     RECT  18.6 105.849 18.72 105.863 ;
     RECT  24 105.849 24.12 105.863 ;
     RECT  29.4 105.849 29.52 105.863 ;
     RECT  34.8 105.849 34.92 105.863 ;
     RECT  40.2 105.849 40.32 105.863 ;
     RECT  45.6 105.849 45.72 105.863 ;
     RECT  51 105.849 51.12 105.863 ;
     RECT  56.4 105.849 56.52 105.863 ;
     RECT  61.8 105.849 61.92 105.863 ;
     RECT  67.2 105.849 67.32 105.863 ;
     RECT  72.6 105.849 72.72 105.863 ;
     RECT  78 105.849 78.12 105.863 ;
     RECT  83.4 105.849 83.52 105.863 ;
     RECT  88.8 105.849 88.92 105.863 ;
     RECT  94.2 105.849 94.32 105.863 ;
     RECT  99.6 105.849 99.72 105.863 ;
     RECT  105 105.849 105.12 105.863 ;
     RECT  39.144 23.411 40.2 40.741 ;
     RECT  35.112 38.005 36.528 39.299 ;
     RECT  27.336 39.205 28.608 39.395 ;
     RECT  47.976 39.973 48.96 40.019 ;
     RECT  32.232 40.213 33.648 40.595 ;
     RECT  33.672 40.259 34.8 41.075 ;
     RECT  8.112 40.837 9.168 41.027 ;
     RECT  6.456 40.981 7.8 43.379 ;
     RECT  35.592 41.413 37.008 42.085 ;
     RECT  49.56 41.651 51 43.379 ;
     RECT  45.504 41.699 45.6 43.141 ;
     RECT  67.512 41.941 68.544 44.339 ;
     RECT  39.144 42.275 40.2 46.357 ;
     RECT  35.112 42.323 36.48 43.379 ;
     RECT  45.912 43.237 47.376 44.051 ;
     RECT  6.432 43.379 7.8 43.765 ;
     RECT  6.408 43.765 7.8 45.685 ;
     RECT  70.656 44.099 70.68 45.301 ;
     RECT  65.832 44.197 67.2 45.059 ;
     RECT  55.296 44.243 55.632 44.483 ;
     RECT  67.512 44.339 67.848 45.253 ;
     RECT  55.296 44.483 56.4 45.301 ;
     RECT  28.608 45.059 29.04 46.117 ;
     RECT  5.112 45.157 6.384 45.253 ;
     RECT  55.08 45.301 56.4 46.115 ;
     RECT  3.768 45.397 5.088 46.261 ;
     RECT  49.56 45.541 51 47.173 ;
     RECT  6.504 45.685 7.8 46.739 ;
     RECT  29.712 45.685 31.008 46.499 ;
     RECT  102 46.211 102.024 47.269 ;
     RECT  3.768 46.261 4.992 47.797 ;
     RECT  29.712 46.499 30.888 47.269 ;
     RECT  77.016 46.501 78 47.363 ;
     RECT  6.408 46.739 7.8 47.363 ;
     RECT  5.112 46.787 6.384 47.363 ;
     RECT  38.136 46.789 39.12 47.651 ;
     RECT  49.944 47.173 51 48.037 ;
     RECT  29.712 47.269 30.864 48.227 ;
     RECT  76.68 47.363 78 49.043 ;
     RECT  28.608 47.843 29.4 48.373 ;
     RECT  43.704 48.037 45.072 48.227 ;
     RECT  29.712 48.227 30.792 48.757 ;
     RECT  27.336 48.373 29.4 49.333 ;
     RECT  49.92 48.515 50.688 48.707 ;
     RECT  49.92 48.707 51 48.997 ;
     RECT  29.712 48.757 30.768 48.899 ;
     RECT  29.712 48.899 30.312 49.813 ;
     RECT  49.56 48.997 51 49.667 ;
     RECT  27.336 49.333 28.656 50.579 ;
     RECT  51.768 49.333 53.28 50.435 ;
     RECT  68.376 49.477 69.504 50.003 ;
     RECT  35.112 49.525 36.144 52.163 ;
     RECT  92.904 49.621 94.2 51.923 ;
     RECT  66.072 49.861 67.2 57.491 ;
     RECT  24.312 50.389 25.584 51.299 ;
     RECT  72.912 50.677 73.968 51.971 ;
     RECT  46.056 50.771 47.04 51.395 ;
     RECT  89.112 50.821 90.624 50.963 ;
     RECT  22.824 50.965 24 51.251 ;
     RECT  62.112 51.013 63.552 52.259 ;
     RECT  94.512 51.253 95.904 51.923 ;
     RECT  45.912 51.395 47.04 54.131 ;
     RECT  8.112 51.829 9.36 51.973 ;
     RECT  8.232 51.973 9.36 53.459 ;
     RECT  34.32 52.211 34.8 53.269 ;
     RECT  15.768 52.981 17.184 54.131 ;
     RECT  17.208 52.981 18.6 54.131 ;
     RECT  65.016 53.077 66.048 53.459 ;
     RECT  8.112 53.459 9.36 55.285 ;
     RECT  65.856 53.459 66.048 54.949 ;
     RECT  18.912 54.085 20.112 54.659 ;
     RECT  99.912 54.179 100.944 54.803 ;
     RECT  37.08 54.565 38.592 54.851 ;
     RECT  38.616 54.565 40.08 56.339 ;
     RECT  99.912 54.803 101.424 56.483 ;
     RECT  62.112 54.853 63.264 57.059 ;
     RECT  8.112 55.475 9.36 57.011 ;
     RECT  23.328 55.907 24 57.205 ;
     RECT  99.216 56.003 99.6 56.389 ;
     RECT  15.6 56.243 15.744 57.205 ;
     RECT  98.616 56.389 99.6 57.635 ;
     RECT  6.6 56.677 7.8 56.819 ;
     RECT  87.768 57.013 88.8 58.163 ;
     RECT  13.512 57.205 14.832 57.347 ;
     RECT  22.968 57.205 24 58.163 ;
     RECT  18.912 57.925 20.4 58.691 ;
     RECT  99.912 58.117 101.424 58.643 ;
     RECT  99.912 58.643 100.872 58.645 ;
     RECT  18.912 58.691 20.688 58.789 ;
     RECT  19.32 58.789 20.688 58.835 ;
  END
END ot_s81_pq_calendar_reader
END LIBRARY
